VERSION 5.8 ;
BUSBITCHARS "[]" ;
DIVIDERCHAR "/" ;
UNITS
    DATABASE MICRONS 1000 ;
END UNITS

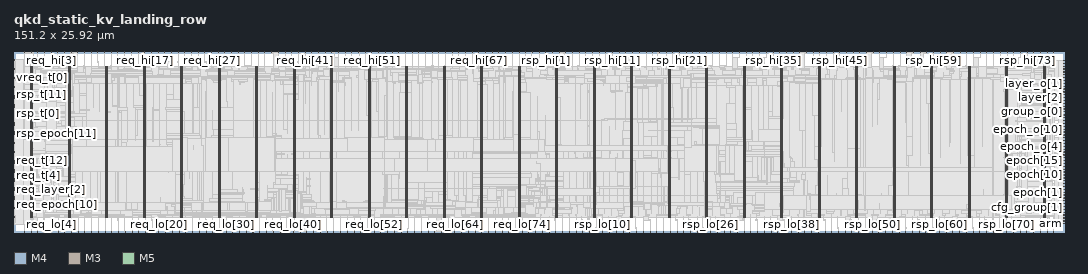
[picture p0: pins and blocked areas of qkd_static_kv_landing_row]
MACRO qkd_static_kv_landing_row
  FOREIGN qkd_static_kv_landing_row 0 0 ;
  CLASS BLOCK ;
  SIZE 151.2 BY 25.92 ;
  PIN arm
    DIRECTION INPUT ;
    USE SIGNAL ;
    PORT
      LAYER M4 ;
        RECT  151.116 1.2 151.2 1.224 ;
    END
  END arm
  PIN arm_o
    DIRECTION OUTPUT ;
    USE SIGNAL ;
    PORT
      LAYER M4 ;
        RECT  151.116 1.584 151.2 1.608 ;
    END
  END arm_o
  PIN cfg_group[0]
    DIRECTION INPUT ;
    USE SIGNAL ;
    PORT
      LAYER M4 ;
        RECT  151.116 2.016 151.2 2.04 ;
    END
  END cfg_group[0]
  PIN cfg_group[1]
    DIRECTION INPUT ;
    USE SIGNAL ;
    PORT
      LAYER M4 ;
        RECT  151.116 2.448 151.2 2.472 ;
    END
  END cfg_group[1]
  PIN cfg_group[2]
    DIRECTION INPUT ;
    USE SIGNAL ;
    PORT
      LAYER M4 ;
        RECT  151.116 2.832 151.2 2.856 ;
    END
  END cfg_group[2]
  PIN cfg_stack[0]
    DIRECTION INPUT ;
    USE SIGNAL ;
    PORT
      LAYER M4 ;
        RECT  151.116 3.264 151.2 3.288 ;
    END
  END cfg_stack[0]
  PIN cfg_stack[1]
    DIRECTION INPUT ;
    USE SIGNAL ;
    PORT
      LAYER M4 ;
        RECT  151.116 3.648 151.2 3.672 ;
    END
  END cfg_stack[1]
  PIN ck
    DIRECTION INPUT ;
    USE SIGNAL ;
    PORT
      LAYER M3 ;
        RECT  1.476 25.882 1.494 25.92 ;
    END
  END ck
  PIN epoch[0]
    DIRECTION INPUT ;
    USE SIGNAL ;
    PORT
      LAYER M4 ;
        RECT  151.116 4.08 151.2 4.104 ;
    END
  END epoch[0]
  PIN epoch[10]
    DIRECTION INPUT ;
    USE SIGNAL ;
    PORT
      LAYER M4 ;
        RECT  151.116 8.208 151.2 8.232 ;
    END
  END epoch[10]
  PIN epoch[11]
    DIRECTION INPUT ;
    USE SIGNAL ;
    PORT
      LAYER M4 ;
        RECT  151.116 8.64 151.2 8.664 ;
    END
  END epoch[11]
  PIN epoch[12]
    DIRECTION INPUT ;
    USE SIGNAL ;
    PORT
      LAYER M4 ;
        RECT  151.116 9.024 151.2 9.048 ;
    END
  END epoch[12]
  PIN epoch[13]
    DIRECTION INPUT ;
    USE SIGNAL ;
    PORT
      LAYER M4 ;
        RECT  151.116 9.456 151.2 9.48 ;
    END
  END epoch[13]
  PIN epoch[14]
    DIRECTION INPUT ;
    USE SIGNAL ;
    PORT
      LAYER M4 ;
        RECT  151.116 9.84 151.2 9.864 ;
    END
  END epoch[14]
  PIN epoch[15]
    DIRECTION INPUT ;
    USE SIGNAL ;
    PORT
      LAYER M4 ;
        RECT  151.116 10.272 151.2 10.296 ;
    END
  END epoch[15]
  PIN epoch[1]
    DIRECTION INPUT ;
    USE SIGNAL ;
    PORT
      LAYER M4 ;
        RECT  151.116 4.512 151.2 4.536 ;
    END
  END epoch[1]
  PIN epoch[2]
    DIRECTION INPUT ;
    USE SIGNAL ;
    PORT
      LAYER M4 ;
        RECT  151.116 4.896 151.2 4.92 ;
    END
  END epoch[2]
  PIN epoch[3]
    DIRECTION INPUT ;
    USE SIGNAL ;
    PORT
      LAYER M4 ;
        RECT  151.116 5.328 151.2 5.352 ;
    END
  END epoch[3]
  PIN epoch[4]
    DIRECTION INPUT ;
    USE SIGNAL ;
    PORT
      LAYER M4 ;
        RECT  151.116 5.712 151.2 5.736 ;
    END
  END epoch[4]
  PIN epoch[5]
    DIRECTION INPUT ;
    USE SIGNAL ;
    PORT
      LAYER M4 ;
        RECT  151.116 6.144 151.2 6.168 ;
    END
  END epoch[5]
  PIN epoch[6]
    DIRECTION INPUT ;
    USE SIGNAL ;
    PORT
      LAYER M4 ;
        RECT  151.116 6.576 151.2 6.6 ;
    END
  END epoch[6]
  PIN epoch[7]
    DIRECTION INPUT ;
    USE SIGNAL ;
    PORT
      LAYER M4 ;
        RECT  151.116 6.96 151.2 6.984 ;
    END
  END epoch[7]
  PIN epoch[8]
    DIRECTION INPUT ;
    USE SIGNAL ;
    PORT
      LAYER M4 ;
        RECT  151.116 7.392 151.2 7.416 ;
    END
  END epoch[8]
  PIN epoch[9]
    DIRECTION INPUT ;
    USE SIGNAL ;
    PORT
      LAYER M4 ;
        RECT  151.116 7.776 151.2 7.8 ;
    END
  END epoch[9]
  PIN epoch_o[0]
    DIRECTION OUTPUT ;
    USE SIGNAL ;
    PORT
      LAYER M4 ;
        RECT  151.116 10.704 151.2 10.728 ;
    END
  END epoch_o[0]
  PIN epoch_o[10]
    DIRECTION OUTPUT ;
    USE SIGNAL ;
    PORT
      LAYER M4 ;
        RECT  151.116 14.784 151.2 14.808 ;
    END
  END epoch_o[10]
  PIN epoch_o[11]
    DIRECTION OUTPUT ;
    USE SIGNAL ;
    PORT
      LAYER M4 ;
        RECT  151.116 15.216 151.2 15.24 ;
    END
  END epoch_o[11]
  PIN epoch_o[12]
    DIRECTION OUTPUT ;
    USE SIGNAL ;
    PORT
      LAYER M4 ;
        RECT  151.116 15.648 151.2 15.672 ;
    END
  END epoch_o[12]
  PIN epoch_o[13]
    DIRECTION OUTPUT ;
    USE SIGNAL ;
    PORT
      LAYER M4 ;
        RECT  151.116 16.032 151.2 16.056 ;
    END
  END epoch_o[13]
  PIN epoch_o[14]
    DIRECTION OUTPUT ;
    USE SIGNAL ;
    PORT
      LAYER M4 ;
        RECT  151.116 16.464 151.2 16.488 ;
    END
  END epoch_o[14]
  PIN epoch_o[15]
    DIRECTION OUTPUT ;
    USE SIGNAL ;
    PORT
      LAYER M4 ;
        RECT  151.116 16.848 151.2 16.872 ;
    END
  END epoch_o[15]
  PIN epoch_o[1]
    DIRECTION OUTPUT ;
    USE SIGNAL ;
    PORT
      LAYER M4 ;
        RECT  151.116 11.088 151.2 11.112 ;
    END
  END epoch_o[1]
  PIN epoch_o[2]
    DIRECTION OUTPUT ;
    USE SIGNAL ;
    PORT
      LAYER M4 ;
        RECT  151.116 11.52 151.2 11.544 ;
    END
  END epoch_o[2]
  PIN epoch_o[3]
    DIRECTION OUTPUT ;
    USE SIGNAL ;
    PORT
      LAYER M4 ;
        RECT  151.116 11.904 151.2 11.928 ;
    END
  END epoch_o[3]
  PIN epoch_o[4]
    DIRECTION OUTPUT ;
    USE SIGNAL ;
    PORT
      LAYER M4 ;
        RECT  151.116 12.336 151.2 12.36 ;
    END
  END epoch_o[4]
  PIN epoch_o[5]
    DIRECTION OUTPUT ;
    USE SIGNAL ;
    PORT
      LAYER M4 ;
        RECT  151.116 12.72 151.2 12.744 ;
    END
  END epoch_o[5]
  PIN epoch_o[6]
    DIRECTION OUTPUT ;
    USE SIGNAL ;
    PORT
      LAYER M4 ;
        RECT  151.116 13.152 151.2 13.176 ;
    END
  END epoch_o[6]
  PIN epoch_o[7]
    DIRECTION OUTPUT ;
    USE SIGNAL ;
    PORT
      LAYER M4 ;
        RECT  151.116 13.584 151.2 13.608 ;
    END
  END epoch_o[7]
  PIN epoch_o[8]
    DIRECTION OUTPUT ;
    USE SIGNAL ;
    PORT
      LAYER M4 ;
        RECT  151.116 13.968 151.2 13.992 ;
    END
  END epoch_o[8]
  PIN epoch_o[9]
    DIRECTION OUTPUT ;
    USE SIGNAL ;
    PORT
      LAYER M4 ;
        RECT  151.116 14.4 151.2 14.424 ;
    END
  END epoch_o[9]
  PIN fault
    DIRECTION OUTPUT ;
    USE SIGNAL ;
    PORT
      LAYER M4 ;
        RECT  0 1.104 0.084 1.128 ;
    END
  END fault
  PIN group_o[0]
    DIRECTION OUTPUT ;
    USE SIGNAL ;
    PORT
      LAYER M4 ;
        RECT  151.116 17.28 151.2 17.304 ;
    END
  END group_o[0]
  PIN group_o[1]
    DIRECTION OUTPUT ;
    USE SIGNAL ;
    PORT
      LAYER M4 ;
        RECT  151.116 17.712 151.2 17.736 ;
    END
  END group_o[1]
  PIN group_o[2]
    DIRECTION OUTPUT ;
    USE SIGNAL ;
    PORT
      LAYER M4 ;
        RECT  151.116 18.096 151.2 18.12 ;
    END
  END group_o[2]
  PIN layer[0]
    DIRECTION INPUT ;
    USE SIGNAL ;
    PORT
      LAYER M4 ;
        RECT  151.116 18.528 151.2 18.552 ;
    END
  END layer[0]
  PIN layer[1]
    DIRECTION INPUT ;
    USE SIGNAL ;
    PORT
      LAYER M4 ;
        RECT  151.116 18.912 151.2 18.936 ;
    END
  END layer[1]
  PIN layer[2]
    DIRECTION INPUT ;
    USE SIGNAL ;
    PORT
      LAYER M4 ;
        RECT  151.116 19.344 151.2 19.368 ;
    END
  END layer[2]
  PIN layer[3]
    DIRECTION INPUT ;
    USE SIGNAL ;
    PORT
      LAYER M4 ;
        RECT  151.116 19.776 151.2 19.8 ;
    END
  END layer[3]
  PIN layer[4]
    DIRECTION INPUT ;
    USE SIGNAL ;
    PORT
      LAYER M4 ;
        RECT  151.116 20.16 151.2 20.184 ;
    END
  END layer[4]
  PIN layer[5]
    DIRECTION INPUT ;
    USE SIGNAL ;
    PORT
      LAYER M4 ;
        RECT  151.116 20.592 151.2 20.616 ;
    END
  END layer[5]
  PIN layer_o[0]
    DIRECTION OUTPUT ;
    USE SIGNAL ;
    PORT
      LAYER M4 ;
        RECT  151.116 20.976 151.2 21 ;
    END
  END layer_o[0]
  PIN layer_o[1]
    DIRECTION OUTPUT ;
    USE SIGNAL ;
    PORT
      LAYER M4 ;
        RECT  151.116 21.408 151.2 21.432 ;
    END
  END layer_o[1]
  PIN layer_o[2]
    DIRECTION OUTPUT ;
    USE SIGNAL ;
    PORT
      LAYER M4 ;
        RECT  151.116 21.792 151.2 21.816 ;
    END
  END layer_o[2]
  PIN layer_o[3]
    DIRECTION OUTPUT ;
    USE SIGNAL ;
    PORT
      LAYER M4 ;
        RECT  151.116 22.224 151.2 22.248 ;
    END
  END layer_o[3]
  PIN layer_o[4]
    DIRECTION OUTPUT ;
    USE SIGNAL ;
    PORT
      LAYER M4 ;
        RECT  151.116 22.656 151.2 22.68 ;
    END
  END layer_o[4]
  PIN layer_o[5]
    DIRECTION OUTPUT ;
    USE SIGNAL ;
    PORT
      LAYER M4 ;
        RECT  151.116 23.04 151.2 23.064 ;
    END
  END layer_o[5]
  PIN req_epoch[0]
    DIRECTION INPUT ;
    USE SIGNAL ;
    PORT
      LAYER M4 ;
        RECT  0 1.392 0.084 1.416 ;
    END
  END req_epoch[0]
  PIN req_epoch[10]
    DIRECTION INPUT ;
    USE SIGNAL ;
    PORT
      LAYER M4 ;
        RECT  0 3.984 0.084 4.008 ;
    END
  END req_epoch[10]
  PIN req_epoch[11]
    DIRECTION INPUT ;
    USE SIGNAL ;
    PORT
      LAYER M4 ;
        RECT  0 4.224 0.084 4.248 ;
    END
  END req_epoch[11]
  PIN req_epoch[12]
    DIRECTION INPUT ;
    USE SIGNAL ;
    PORT
      LAYER M4 ;
        RECT  0 4.512 0.084 4.536 ;
    END
  END req_epoch[12]
  PIN req_epoch[13]
    DIRECTION INPUT ;
    USE SIGNAL ;
    PORT
      LAYER M4 ;
        RECT  0 4.752 0.084 4.776 ;
    END
  END req_epoch[13]
  PIN req_epoch[14]
    DIRECTION INPUT ;
    USE SIGNAL ;
    PORT
      LAYER M4 ;
        RECT  0 5.04 0.084 5.064 ;
    END
  END req_epoch[14]
  PIN req_epoch[15]
    DIRECTION INPUT ;
    USE SIGNAL ;
    PORT
      LAYER M4 ;
        RECT  0 5.28 0.084 5.304 ;
    END
  END req_epoch[15]
  PIN req_epoch[1]
    DIRECTION INPUT ;
    USE SIGNAL ;
    PORT
      LAYER M4 ;
        RECT  0 1.632 0.084 1.656 ;
    END
  END req_epoch[1]
  PIN req_epoch[2]
    DIRECTION INPUT ;
    USE SIGNAL ;
    PORT
      LAYER M4 ;
        RECT  0 1.92 0.084 1.944 ;
    END
  END req_epoch[2]
  PIN req_epoch[3]
    DIRECTION INPUT ;
    USE SIGNAL ;
    PORT
      LAYER M4 ;
        RECT  0 2.16 0.084 2.184 ;
    END
  END req_epoch[3]
  PIN req_epoch[4]
    DIRECTION INPUT ;
    USE SIGNAL ;
    PORT
      LAYER M4 ;
        RECT  0 2.4 0.084 2.424 ;
    END
  END req_epoch[4]
  PIN req_epoch[5]
    DIRECTION INPUT ;
    USE SIGNAL ;
    PORT
      LAYER M4 ;
        RECT  0 2.688 0.084 2.712 ;
    END
  END req_epoch[5]
  PIN req_epoch[6]
    DIRECTION INPUT ;
    USE SIGNAL ;
    PORT
      LAYER M4 ;
        RECT  0 2.928 0.084 2.952 ;
    END
  END req_epoch[6]
  PIN req_epoch[7]
    DIRECTION INPUT ;
    USE SIGNAL ;
    PORT
      LAYER M4 ;
        RECT  0 3.216 0.084 3.24 ;
    END
  END req_epoch[7]
  PIN req_epoch[8]
    DIRECTION INPUT ;
    USE SIGNAL ;
    PORT
      LAYER M4 ;
        RECT  0 3.456 0.084 3.48 ;
    END
  END req_epoch[8]
  PIN req_epoch[9]
    DIRECTION INPUT ;
    USE SIGNAL ;
    PORT
      LAYER M4 ;
        RECT  0 3.696 0.084 3.72 ;
    END
  END req_epoch[9]
  PIN req_hi[0]
    DIRECTION OUTPUT ;
    USE SIGNAL ;
    PORT
      LAYER M5 ;
        RECT  2.448 25.836 2.472 25.92 ;
    END
  END req_hi[0]
  PIN req_hi[10]
    DIRECTION OUTPUT ;
    USE SIGNAL ;
    PORT
      LAYER M5 ;
        RECT  12.048 25.836 12.072 25.92 ;
    END
  END req_hi[10]
  PIN req_hi[11]
    DIRECTION OUTPUT ;
    USE SIGNAL ;
    PORT
      LAYER M3 ;
        RECT  13.032 25.882 13.05 25.92 ;
    END
  END req_hi[11]
  PIN req_hi[12]
    DIRECTION OUTPUT ;
    USE SIGNAL ;
    PORT
      LAYER M5 ;
        RECT  13.968 25.836 13.992 25.92 ;
    END
  END req_hi[12]
  PIN req_hi[13]
    DIRECTION OUTPUT ;
    USE SIGNAL ;
    PORT
      LAYER M3 ;
        RECT  14.94 25.882 14.958 25.92 ;
    END
  END req_hi[13]
  PIN req_hi[14]
    DIRECTION OUTPUT ;
    USE SIGNAL ;
    PORT
      LAYER M5 ;
        RECT  15.888 25.836 15.912 25.92 ;
    END
  END req_hi[14]
  PIN req_hi[15]
    DIRECTION OUTPUT ;
    USE SIGNAL ;
    PORT
      LAYER M3 ;
        RECT  16.884 25.882 16.902 25.92 ;
    END
  END req_hi[15]
  PIN req_hi[16]
    DIRECTION OUTPUT ;
    USE SIGNAL ;
    PORT
      LAYER M5 ;
        RECT  17.856 25.836 17.88 25.92 ;
    END
  END req_hi[16]
  PIN req_hi[17]
    DIRECTION OUTPUT ;
    USE SIGNAL ;
    PORT
      LAYER M3 ;
        RECT  18.792 25.882 18.81 25.92 ;
    END
  END req_hi[17]
  PIN req_hi[18]
    DIRECTION OUTPUT ;
    USE SIGNAL ;
    PORT
      LAYER M5 ;
        RECT  19.776 25.836 19.8 25.92 ;
    END
  END req_hi[18]
  PIN req_hi[19]
    DIRECTION OUTPUT ;
    USE SIGNAL ;
    PORT
      LAYER M3 ;
        RECT  20.736 25.882 20.754 25.92 ;
    END
  END req_hi[19]
  PIN req_hi[1]
    DIRECTION OUTPUT ;
    USE SIGNAL ;
    PORT
      LAYER M3 ;
        RECT  3.384 25.882 3.402 25.92 ;
    END
  END req_hi[1]
  PIN req_hi[20]
    DIRECTION OUTPUT ;
    USE SIGNAL ;
    PORT
      LAYER M5 ;
        RECT  21.696 25.836 21.72 25.92 ;
    END
  END req_hi[20]
  PIN req_hi[21]
    DIRECTION OUTPUT ;
    USE SIGNAL ;
    PORT
      LAYER M3 ;
        RECT  22.644 25.882 22.662 25.92 ;
    END
  END req_hi[21]
  PIN req_hi[22]
    DIRECTION OUTPUT ;
    USE SIGNAL ;
    PORT
      LAYER M5 ;
        RECT  23.616 25.836 23.64 25.92 ;
    END
  END req_hi[22]
  PIN req_hi[23]
    DIRECTION OUTPUT ;
    USE SIGNAL ;
    PORT
      LAYER M3 ;
        RECT  24.588 25.882 24.606 25.92 ;
    END
  END req_hi[23]
  PIN req_hi[24]
    DIRECTION OUTPUT ;
    USE SIGNAL ;
    PORT
      LAYER M5 ;
        RECT  25.536 25.836 25.56 25.92 ;
    END
  END req_hi[24]
  PIN req_hi[25]
    DIRECTION OUTPUT ;
    USE SIGNAL ;
    PORT
      LAYER M3 ;
        RECT  26.496 25.882 26.514 25.92 ;
    END
  END req_hi[25]
  PIN req_hi[26]
    DIRECTION OUTPUT ;
    USE SIGNAL ;
    PORT
      LAYER M5 ;
        RECT  27.456 25.836 27.48 25.92 ;
    END
  END req_hi[26]
  PIN req_hi[27]
    DIRECTION OUTPUT ;
    USE SIGNAL ;
    PORT
      LAYER M3 ;
        RECT  28.44 25.882 28.458 25.92 ;
    END
  END req_hi[27]
  PIN req_hi[28]
    DIRECTION OUTPUT ;
    USE SIGNAL ;
    PORT
      LAYER M5 ;
        RECT  29.376 25.836 29.4 25.92 ;
    END
  END req_hi[28]
  PIN req_hi[29]
    DIRECTION OUTPUT ;
    USE SIGNAL ;
    PORT
      LAYER M3 ;
        RECT  30.348 25.882 30.366 25.92 ;
    END
  END req_hi[29]
  PIN req_hi[2]
    DIRECTION OUTPUT ;
    USE SIGNAL ;
    PORT
      LAYER M5 ;
        RECT  4.368 25.836 4.392 25.92 ;
    END
  END req_hi[2]
  PIN req_hi[30]
    DIRECTION OUTPUT ;
    USE SIGNAL ;
    PORT
      LAYER M5 ;
        RECT  31.296 25.836 31.32 25.92 ;
    END
  END req_hi[30]
  PIN req_hi[31]
    DIRECTION OUTPUT ;
    USE SIGNAL ;
    PORT
      LAYER M3 ;
        RECT  32.292 25.882 32.31 25.92 ;
    END
  END req_hi[31]
  PIN req_hi[32]
    DIRECTION OUTPUT ;
    USE SIGNAL ;
    PORT
      LAYER M5 ;
        RECT  33.216 25.836 33.24 25.92 ;
    END
  END req_hi[32]
  PIN req_hi[33]
    DIRECTION OUTPUT ;
    USE SIGNAL ;
    PORT
      LAYER M3 ;
        RECT  34.2 25.882 34.218 25.92 ;
    END
  END req_hi[33]
  PIN req_hi[34]
    DIRECTION OUTPUT ;
    USE SIGNAL ;
    PORT
      LAYER M5 ;
        RECT  35.184 25.836 35.208 25.92 ;
    END
  END req_hi[34]
  PIN req_hi[35]
    DIRECTION OUTPUT ;
    USE SIGNAL ;
    PORT
      LAYER M3 ;
        RECT  36.108 25.882 36.126 25.92 ;
    END
  END req_hi[35]
  PIN req_hi[36]
    DIRECTION OUTPUT ;
    USE SIGNAL ;
    PORT
      LAYER M5 ;
        RECT  37.104 25.836 37.128 25.92 ;
    END
  END req_hi[36]
  PIN req_hi[37]
    DIRECTION OUTPUT ;
    USE SIGNAL ;
    PORT
      LAYER M3 ;
        RECT  38.052 25.882 38.07 25.92 ;
    END
  END req_hi[37]
  PIN req_hi[38]
    DIRECTION OUTPUT ;
    USE SIGNAL ;
    PORT
      LAYER M5 ;
        RECT  39.024 25.836 39.048 25.92 ;
    END
  END req_hi[38]
  PIN req_hi[39]
    DIRECTION OUTPUT ;
    USE SIGNAL ;
    PORT
      LAYER M3 ;
        RECT  39.96 25.882 39.978 25.92 ;
    END
  END req_hi[39]
  PIN req_hi[3]
    DIRECTION OUTPUT ;
    USE SIGNAL ;
    PORT
      LAYER M3 ;
        RECT  5.328 25.882 5.346 25.92 ;
    END
  END req_hi[3]
  PIN req_hi[40]
    DIRECTION OUTPUT ;
    USE SIGNAL ;
    PORT
      LAYER M5 ;
        RECT  40.944 25.836 40.968 25.92 ;
    END
  END req_hi[40]
  PIN req_hi[41]
    DIRECTION OUTPUT ;
    USE SIGNAL ;
    PORT
      LAYER M3 ;
        RECT  41.904 25.882 41.922 25.92 ;
    END
  END req_hi[41]
  PIN req_hi[42]
    DIRECTION OUTPUT ;
    USE SIGNAL ;
    PORT
      LAYER M5 ;
        RECT  42.864 25.836 42.888 25.92 ;
    END
  END req_hi[42]
  PIN req_hi[43]
    DIRECTION OUTPUT ;
    USE SIGNAL ;
    PORT
      LAYER M3 ;
        RECT  43.812 25.882 43.83 25.92 ;
    END
  END req_hi[43]
  PIN req_hi[44]
    DIRECTION OUTPUT ;
    USE SIGNAL ;
    PORT
      LAYER M5 ;
        RECT  44.784 25.836 44.808 25.92 ;
    END
  END req_hi[44]
  PIN req_hi[45]
    DIRECTION OUTPUT ;
    USE SIGNAL ;
    PORT
      LAYER M3 ;
        RECT  45.756 25.882 45.774 25.92 ;
    END
  END req_hi[45]
  PIN req_hi[46]
    DIRECTION OUTPUT ;
    USE SIGNAL ;
    PORT
      LAYER M5 ;
        RECT  46.704 25.836 46.728 25.92 ;
    END
  END req_hi[46]
  PIN req_hi[47]
    DIRECTION OUTPUT ;
    USE SIGNAL ;
    PORT
      LAYER M3 ;
        RECT  47.664 25.882 47.682 25.92 ;
    END
  END req_hi[47]
  PIN req_hi[48]
    DIRECTION OUTPUT ;
    USE SIGNAL ;
    PORT
      LAYER M5 ;
        RECT  48.624 25.836 48.648 25.92 ;
    END
  END req_hi[48]
  PIN req_hi[49]
    DIRECTION OUTPUT ;
    USE SIGNAL ;
    PORT
      LAYER M3 ;
        RECT  49.608 25.882 49.626 25.92 ;
    END
  END req_hi[49]
  PIN req_hi[4]
    DIRECTION OUTPUT ;
    USE SIGNAL ;
    PORT
      LAYER M5 ;
        RECT  6.288 25.836 6.312 25.92 ;
    END
  END req_hi[4]
  PIN req_hi[50]
    DIRECTION OUTPUT ;
    USE SIGNAL ;
    PORT
      LAYER M5 ;
        RECT  50.544 25.836 50.568 25.92 ;
    END
  END req_hi[50]
  PIN req_hi[51]
    DIRECTION OUTPUT ;
    USE SIGNAL ;
    PORT
      LAYER M3 ;
        RECT  51.516 25.882 51.534 25.92 ;
    END
  END req_hi[51]
  PIN req_hi[52]
    DIRECTION OUTPUT ;
    USE SIGNAL ;
    PORT
      LAYER M5 ;
        RECT  52.464 25.836 52.488 25.92 ;
    END
  END req_hi[52]
  PIN req_hi[53]
    DIRECTION OUTPUT ;
    USE SIGNAL ;
    PORT
      LAYER M3 ;
        RECT  53.46 25.882 53.478 25.92 ;
    END
  END req_hi[53]
  PIN req_hi[54]
    DIRECTION OUTPUT ;
    USE SIGNAL ;
    PORT
      LAYER M5 ;
        RECT  54.432 25.836 54.456 25.92 ;
    END
  END req_hi[54]
  PIN req_hi[55]
    DIRECTION OUTPUT ;
    USE SIGNAL ;
    PORT
      LAYER M3 ;
        RECT  55.368 25.882 55.386 25.92 ;
    END
  END req_hi[55]
  PIN req_hi[56]
    DIRECTION OUTPUT ;
    USE SIGNAL ;
    PORT
      LAYER M5 ;
        RECT  56.352 25.836 56.376 25.92 ;
    END
  END req_hi[56]
  PIN req_hi[57]
    DIRECTION OUTPUT ;
    USE SIGNAL ;
    PORT
      LAYER M3 ;
        RECT  57.312 25.882 57.33 25.92 ;
    END
  END req_hi[57]
  PIN req_hi[58]
    DIRECTION OUTPUT ;
    USE SIGNAL ;
    PORT
      LAYER M5 ;
        RECT  58.272 25.836 58.296 25.92 ;
    END
  END req_hi[58]
  PIN req_hi[59]
    DIRECTION OUTPUT ;
    USE SIGNAL ;
    PORT
      LAYER M3 ;
        RECT  59.22 25.882 59.238 25.92 ;
    END
  END req_hi[59]
  PIN req_hi[5]
    DIRECTION OUTPUT ;
    USE SIGNAL ;
    PORT
      LAYER M3 ;
        RECT  7.236 25.882 7.254 25.92 ;
    END
  END req_hi[5]
  PIN req_hi[60]
    DIRECTION OUTPUT ;
    USE SIGNAL ;
    PORT
      LAYER M5 ;
        RECT  60.192 25.836 60.216 25.92 ;
    END
  END req_hi[60]
  PIN req_hi[61]
    DIRECTION OUTPUT ;
    USE SIGNAL ;
    PORT
      LAYER M3 ;
        RECT  61.164 25.882 61.182 25.92 ;
    END
  END req_hi[61]
  PIN req_hi[62]
    DIRECTION OUTPUT ;
    USE SIGNAL ;
    PORT
      LAYER M5 ;
        RECT  62.112 25.836 62.136 25.92 ;
    END
  END req_hi[62]
  PIN req_hi[63]
    DIRECTION OUTPUT ;
    USE SIGNAL ;
    PORT
      LAYER M3 ;
        RECT  63.072 25.882 63.09 25.92 ;
    END
  END req_hi[63]
  PIN req_hi[64]
    DIRECTION OUTPUT ;
    USE SIGNAL ;
    PORT
      LAYER M5 ;
        RECT  64.032 25.836 64.056 25.92 ;
    END
  END req_hi[64]
  PIN req_hi[65]
    DIRECTION OUTPUT ;
    USE SIGNAL ;
    PORT
      LAYER M3 ;
        RECT  65.016 25.882 65.034 25.92 ;
    END
  END req_hi[65]
  PIN req_hi[66]
    DIRECTION OUTPUT ;
    USE SIGNAL ;
    PORT
      LAYER M5 ;
        RECT  65.952 25.836 65.976 25.92 ;
    END
  END req_hi[66]
  PIN req_hi[67]
    DIRECTION OUTPUT ;
    USE SIGNAL ;
    PORT
      LAYER M3 ;
        RECT  66.924 25.882 66.942 25.92 ;
    END
  END req_hi[67]
  PIN req_hi[68]
    DIRECTION OUTPUT ;
    USE SIGNAL ;
    PORT
      LAYER M5 ;
        RECT  67.872 25.836 67.896 25.92 ;
    END
  END req_hi[68]
  PIN req_hi[69]
    DIRECTION OUTPUT ;
    USE SIGNAL ;
    PORT
      LAYER M3 ;
        RECT  68.868 25.882 68.886 25.92 ;
    END
  END req_hi[69]
  PIN req_hi[6]
    DIRECTION OUTPUT ;
    USE SIGNAL ;
    PORT
      LAYER M5 ;
        RECT  8.208 25.836 8.232 25.92 ;
    END
  END req_hi[6]
  PIN req_hi[70]
    DIRECTION OUTPUT ;
    USE SIGNAL ;
    PORT
      LAYER M5 ;
        RECT  69.792 25.836 69.816 25.92 ;
    END
  END req_hi[70]
  PIN req_hi[71]
    DIRECTION OUTPUT ;
    USE SIGNAL ;
    PORT
      LAYER M3 ;
        RECT  70.776 25.882 70.794 25.92 ;
    END
  END req_hi[71]
  PIN req_hi[72]
    DIRECTION OUTPUT ;
    USE SIGNAL ;
    PORT
      LAYER M5 ;
        RECT  71.76 25.836 71.784 25.92 ;
    END
  END req_hi[72]
  PIN req_hi[73]
    DIRECTION OUTPUT ;
    USE SIGNAL ;
    PORT
      LAYER M3 ;
        RECT  72.72 25.882 72.738 25.92 ;
    END
  END req_hi[73]
  PIN req_hi[74]
    DIRECTION OUTPUT ;
    USE SIGNAL ;
    PORT
      LAYER M5 ;
        RECT  73.68 25.836 73.704 25.92 ;
    END
  END req_hi[74]
  PIN req_hi[75]
    DIRECTION OUTPUT ;
    USE SIGNAL ;
    PORT
      LAYER M3 ;
        RECT  74.628 25.882 74.646 25.92 ;
    END
  END req_hi[75]
  PIN req_hi[7]
    DIRECTION OUTPUT ;
    USE SIGNAL ;
    PORT
      LAYER M3 ;
        RECT  9.18 25.882 9.198 25.92 ;
    END
  END req_hi[7]
  PIN req_hi[8]
    DIRECTION OUTPUT ;
    USE SIGNAL ;
    PORT
      LAYER M5 ;
        RECT  10.128 25.836 10.152 25.92 ;
    END
  END req_hi[8]
  PIN req_hi[9]
    DIRECTION OUTPUT ;
    USE SIGNAL ;
    PORT
      LAYER M3 ;
        RECT  11.088 25.882 11.106 25.92 ;
    END
  END req_hi[9]
  PIN req_layer[0]
    DIRECTION INPUT ;
    USE SIGNAL ;
    PORT
      LAYER M4 ;
        RECT  0 5.52 0.084 5.544 ;
    END
  END req_layer[0]
  PIN req_layer[1]
    DIRECTION INPUT ;
    USE SIGNAL ;
    PORT
      LAYER M4 ;
        RECT  0 5.808 0.084 5.832 ;
    END
  END req_layer[1]
  PIN req_layer[2]
    DIRECTION INPUT ;
    USE SIGNAL ;
    PORT
      LAYER M4 ;
        RECT  0 6.048 0.084 6.072 ;
    END
  END req_layer[2]
  PIN req_layer[3]
    DIRECTION INPUT ;
    USE SIGNAL ;
    PORT
      LAYER M4 ;
        RECT  0 6.336 0.084 6.36 ;
    END
  END req_layer[3]
  PIN req_layer[4]
    DIRECTION INPUT ;
    USE SIGNAL ;
    PORT
      LAYER M4 ;
        RECT  0 6.576 0.084 6.6 ;
    END
  END req_layer[4]
  PIN req_layer[5]
    DIRECTION INPUT ;
    USE SIGNAL ;
    PORT
      LAYER M4 ;
        RECT  0 6.816 0.084 6.84 ;
    END
  END req_layer[5]
  PIN req_lo[0]
    DIRECTION OUTPUT ;
    USE SIGNAL ;
    PORT
      LAYER M3 ;
        RECT  1.476 0 1.494 0.038 ;
    END
  END req_lo[0]
  PIN req_lo[10]
    DIRECTION OUTPUT ;
    USE SIGNAL ;
    PORT
      LAYER M3 ;
        RECT  11.16 0 11.178 0.038 ;
    END
  END req_lo[10]
  PIN req_lo[11]
    DIRECTION OUTPUT ;
    USE SIGNAL ;
    PORT
      LAYER M5 ;
        RECT  12.144 0 12.168 0.084 ;
    END
  END req_lo[11]
  PIN req_lo[12]
    DIRECTION OUTPUT ;
    USE SIGNAL ;
    PORT
      LAYER M3 ;
        RECT  13.104 0 13.122 0.038 ;
    END
  END req_lo[12]
  PIN req_lo[13]
    DIRECTION OUTPUT ;
    USE SIGNAL ;
    PORT
      LAYER M5 ;
        RECT  14.064 0 14.088 0.084 ;
    END
  END req_lo[13]
  PIN req_lo[14]
    DIRECTION OUTPUT ;
    USE SIGNAL ;
    PORT
      LAYER M3 ;
        RECT  15.048 0 15.066 0.038 ;
    END
  END req_lo[14]
  PIN req_lo[15]
    DIRECTION OUTPUT ;
    USE SIGNAL ;
    PORT
      LAYER M5 ;
        RECT  15.984 0 16.008 0.084 ;
    END
  END req_lo[15]
  PIN req_lo[16]
    DIRECTION OUTPUT ;
    USE SIGNAL ;
    PORT
      LAYER M3 ;
        RECT  16.992 0 17.01 0.038 ;
    END
  END req_lo[16]
  PIN req_lo[17]
    DIRECTION OUTPUT ;
    USE SIGNAL ;
    PORT
      LAYER M5 ;
        RECT  17.952 0 17.976 0.084 ;
    END
  END req_lo[17]
  PIN req_lo[18]
    DIRECTION OUTPUT ;
    USE SIGNAL ;
    PORT
      LAYER M3 ;
        RECT  18.9 0 18.918 0.038 ;
    END
  END req_lo[18]
  PIN req_lo[19]
    DIRECTION OUTPUT ;
    USE SIGNAL ;
    PORT
      LAYER M5 ;
        RECT  19.872 0 19.896 0.084 ;
    END
  END req_lo[19]
  PIN req_lo[1]
    DIRECTION OUTPUT ;
    USE SIGNAL ;
    PORT
      LAYER M5 ;
        RECT  2.448 0 2.472 0.084 ;
    END
  END req_lo[1]
  PIN req_lo[20]
    DIRECTION OUTPUT ;
    USE SIGNAL ;
    PORT
      LAYER M3 ;
        RECT  20.844 0 20.862 0.038 ;
    END
  END req_lo[20]
  PIN req_lo[21]
    DIRECTION OUTPUT ;
    USE SIGNAL ;
    PORT
      LAYER M5 ;
        RECT  21.84 0 21.864 0.084 ;
    END
  END req_lo[21]
  PIN req_lo[22]
    DIRECTION OUTPUT ;
    USE SIGNAL ;
    PORT
      LAYER M3 ;
        RECT  22.788 0 22.806 0.038 ;
    END
  END req_lo[22]
  PIN req_lo[23]
    DIRECTION OUTPUT ;
    USE SIGNAL ;
    PORT
      LAYER M5 ;
        RECT  23.76 0 23.784 0.084 ;
    END
  END req_lo[23]
  PIN req_lo[24]
    DIRECTION OUTPUT ;
    USE SIGNAL ;
    PORT
      LAYER M3 ;
        RECT  24.732 0 24.75 0.038 ;
    END
  END req_lo[24]
  PIN req_lo[25]
    DIRECTION OUTPUT ;
    USE SIGNAL ;
    PORT
      LAYER M5 ;
        RECT  25.68 0 25.704 0.084 ;
    END
  END req_lo[25]
  PIN req_lo[26]
    DIRECTION OUTPUT ;
    USE SIGNAL ;
    PORT
      LAYER M3 ;
        RECT  26.676 0 26.694 0.038 ;
    END
  END req_lo[26]
  PIN req_lo[27]
    DIRECTION OUTPUT ;
    USE SIGNAL ;
    PORT
      LAYER M5 ;
        RECT  27.648 0 27.672 0.084 ;
    END
  END req_lo[27]
  PIN req_lo[28]
    DIRECTION OUTPUT ;
    USE SIGNAL ;
    PORT
      LAYER M3 ;
        RECT  28.62 0 28.638 0.038 ;
    END
  END req_lo[28]
  PIN req_lo[29]
    DIRECTION OUTPUT ;
    USE SIGNAL ;
    PORT
      LAYER M5 ;
        RECT  29.568 0 29.592 0.084 ;
    END
  END req_lo[29]
  PIN req_lo[2]
    DIRECTION OUTPUT ;
    USE SIGNAL ;
    PORT
      LAYER M3 ;
        RECT  3.42 0 3.438 0.038 ;
    END
  END req_lo[2]
  PIN req_lo[30]
    DIRECTION OUTPUT ;
    USE SIGNAL ;
    PORT
      LAYER M3 ;
        RECT  30.528 0 30.546 0.038 ;
    END
  END req_lo[30]
  PIN req_lo[31]
    DIRECTION OUTPUT ;
    USE SIGNAL ;
    PORT
      LAYER M5 ;
        RECT  31.488 0 31.512 0.084 ;
    END
  END req_lo[31]
  PIN req_lo[32]
    DIRECTION OUTPUT ;
    USE SIGNAL ;
    PORT
      LAYER M3 ;
        RECT  32.472 0 32.49 0.038 ;
    END
  END req_lo[32]
  PIN req_lo[33]
    DIRECTION OUTPUT ;
    USE SIGNAL ;
    PORT
      LAYER M5 ;
        RECT  33.456 0 33.48 0.084 ;
    END
  END req_lo[33]
  PIN req_lo[34]
    DIRECTION OUTPUT ;
    USE SIGNAL ;
    PORT
      LAYER M3 ;
        RECT  34.416 0 34.434 0.038 ;
    END
  END req_lo[34]
  PIN req_lo[35]
    DIRECTION OUTPUT ;
    USE SIGNAL ;
    PORT
      LAYER M5 ;
        RECT  35.376 0 35.4 0.084 ;
    END
  END req_lo[35]
  PIN req_lo[36]
    DIRECTION OUTPUT ;
    USE SIGNAL ;
    PORT
      LAYER M3 ;
        RECT  36.36 0 36.378 0.038 ;
    END
  END req_lo[36]
  PIN req_lo[37]
    DIRECTION OUTPUT ;
    USE SIGNAL ;
    PORT
      LAYER M5 ;
        RECT  37.296 0 37.32 0.084 ;
    END
  END req_lo[37]
  PIN req_lo[38]
    DIRECTION OUTPUT ;
    USE SIGNAL ;
    PORT
      LAYER M3 ;
        RECT  38.304 0 38.322 0.038 ;
    END
  END req_lo[38]
  PIN req_lo[39]
    DIRECTION OUTPUT ;
    USE SIGNAL ;
    PORT
      LAYER M5 ;
        RECT  39.264 0 39.288 0.084 ;
    END
  END req_lo[39]
  PIN req_lo[3]
    DIRECTION OUTPUT ;
    USE SIGNAL ;
    PORT
      LAYER M5 ;
        RECT  4.368 0 4.392 0.084 ;
    END
  END req_lo[3]
  PIN req_lo[40]
    DIRECTION OUTPUT ;
    USE SIGNAL ;
    PORT
      LAYER M3 ;
        RECT  40.212 0 40.23 0.038 ;
    END
  END req_lo[40]
  PIN req_lo[41]
    DIRECTION OUTPUT ;
    USE SIGNAL ;
    PORT
      LAYER M5 ;
        RECT  41.184 0 41.208 0.084 ;
    END
  END req_lo[41]
  PIN req_lo[42]
    DIRECTION OUTPUT ;
    USE SIGNAL ;
    PORT
      LAYER M3 ;
        RECT  42.156 0 42.174 0.038 ;
    END
  END req_lo[42]
  PIN req_lo[43]
    DIRECTION OUTPUT ;
    USE SIGNAL ;
    PORT
      LAYER M5 ;
        RECT  43.152 0 43.176 0.084 ;
    END
  END req_lo[43]
  PIN req_lo[44]
    DIRECTION OUTPUT ;
    USE SIGNAL ;
    PORT
      LAYER M3 ;
        RECT  44.1 0 44.118 0.038 ;
    END
  END req_lo[44]
  PIN req_lo[45]
    DIRECTION OUTPUT ;
    USE SIGNAL ;
    PORT
      LAYER M5 ;
        RECT  45.072 0 45.096 0.084 ;
    END
  END req_lo[45]
  PIN req_lo[46]
    DIRECTION OUTPUT ;
    USE SIGNAL ;
    PORT
      LAYER M3 ;
        RECT  46.044 0 46.062 0.038 ;
    END
  END req_lo[46]
  PIN req_lo[47]
    DIRECTION OUTPUT ;
    USE SIGNAL ;
    PORT
      LAYER M5 ;
        RECT  46.992 0 47.016 0.084 ;
    END
  END req_lo[47]
  PIN req_lo[48]
    DIRECTION OUTPUT ;
    USE SIGNAL ;
    PORT
      LAYER M3 ;
        RECT  47.988 0 48.006 0.038 ;
    END
  END req_lo[48]
  PIN req_lo[49]
    DIRECTION OUTPUT ;
    USE SIGNAL ;
    PORT
      LAYER M5 ;
        RECT  48.96 0 48.984 0.084 ;
    END
  END req_lo[49]
  PIN req_lo[4]
    DIRECTION OUTPUT ;
    USE SIGNAL ;
    PORT
      LAYER M3 ;
        RECT  5.364 0 5.382 0.038 ;
    END
  END req_lo[4]
  PIN req_lo[50]
    DIRECTION OUTPUT ;
    USE SIGNAL ;
    PORT
      LAYER M3 ;
        RECT  49.932 0 49.95 0.038 ;
    END
  END req_lo[50]
  PIN req_lo[51]
    DIRECTION OUTPUT ;
    USE SIGNAL ;
    PORT
      LAYER M5 ;
        RECT  50.88 0 50.904 0.084 ;
    END
  END req_lo[51]
  PIN req_lo[52]
    DIRECTION OUTPUT ;
    USE SIGNAL ;
    PORT
      LAYER M3 ;
        RECT  51.84 0 51.858 0.038 ;
    END
  END req_lo[52]
  PIN req_lo[53]
    DIRECTION OUTPUT ;
    USE SIGNAL ;
    PORT
      LAYER M5 ;
        RECT  52.8 0 52.824 0.084 ;
    END
  END req_lo[53]
  PIN req_lo[54]
    DIRECTION OUTPUT ;
    USE SIGNAL ;
    PORT
      LAYER M3 ;
        RECT  53.784 0 53.802 0.038 ;
    END
  END req_lo[54]
  PIN req_lo[55]
    DIRECTION OUTPUT ;
    USE SIGNAL ;
    PORT
      LAYER M5 ;
        RECT  54.768 0 54.792 0.084 ;
    END
  END req_lo[55]
  PIN req_lo[56]
    DIRECTION OUTPUT ;
    USE SIGNAL ;
    PORT
      LAYER M3 ;
        RECT  55.728 0 55.746 0.038 ;
    END
  END req_lo[56]
  PIN req_lo[57]
    DIRECTION OUTPUT ;
    USE SIGNAL ;
    PORT
      LAYER M5 ;
        RECT  56.688 0 56.712 0.084 ;
    END
  END req_lo[57]
  PIN req_lo[58]
    DIRECTION OUTPUT ;
    USE SIGNAL ;
    PORT
      LAYER M3 ;
        RECT  57.672 0 57.69 0.038 ;
    END
  END req_lo[58]
  PIN req_lo[59]
    DIRECTION OUTPUT ;
    USE SIGNAL ;
    PORT
      LAYER M5 ;
        RECT  58.656 0 58.68 0.084 ;
    END
  END req_lo[59]
  PIN req_lo[5]
    DIRECTION OUTPUT ;
    USE SIGNAL ;
    PORT
      LAYER M5 ;
        RECT  6.336 0 6.36 0.084 ;
    END
  END req_lo[5]
  PIN req_lo[60]
    DIRECTION OUTPUT ;
    USE SIGNAL ;
    PORT
      LAYER M3 ;
        RECT  59.616 0 59.634 0.038 ;
    END
  END req_lo[60]
  PIN req_lo[61]
    DIRECTION OUTPUT ;
    USE SIGNAL ;
    PORT
      LAYER M5 ;
        RECT  60.576 0 60.6 0.084 ;
    END
  END req_lo[61]
  PIN req_lo[62]
    DIRECTION OUTPUT ;
    USE SIGNAL ;
    PORT
      LAYER M3 ;
        RECT  61.56 0 61.578 0.038 ;
    END
  END req_lo[62]
  PIN req_lo[63]
    DIRECTION OUTPUT ;
    USE SIGNAL ;
    PORT
      LAYER M5 ;
        RECT  62.496 0 62.52 0.084 ;
    END
  END req_lo[63]
  PIN req_lo[64]
    DIRECTION OUTPUT ;
    USE SIGNAL ;
    PORT
      LAYER M3 ;
        RECT  63.468 0 63.486 0.038 ;
    END
  END req_lo[64]
  PIN req_lo[65]
    DIRECTION OUTPUT ;
    USE SIGNAL ;
    PORT
      LAYER M5 ;
        RECT  64.464 0 64.488 0.084 ;
    END
  END req_lo[65]
  PIN req_lo[66]
    DIRECTION OUTPUT ;
    USE SIGNAL ;
    PORT
      LAYER M3 ;
        RECT  65.412 0 65.43 0.038 ;
    END
  END req_lo[66]
  PIN req_lo[67]
    DIRECTION OUTPUT ;
    USE SIGNAL ;
    PORT
      LAYER M5 ;
        RECT  66.384 0 66.408 0.084 ;
    END
  END req_lo[67]
  PIN req_lo[68]
    DIRECTION OUTPUT ;
    USE SIGNAL ;
    PORT
      LAYER M3 ;
        RECT  67.356 0 67.374 0.038 ;
    END
  END req_lo[68]
  PIN req_lo[69]
    DIRECTION OUTPUT ;
    USE SIGNAL ;
    PORT
      LAYER M5 ;
        RECT  68.304 0 68.328 0.084 ;
    END
  END req_lo[69]
  PIN req_lo[6]
    DIRECTION OUTPUT ;
    USE SIGNAL ;
    PORT
      LAYER M3 ;
        RECT  7.272 0 7.29 0.038 ;
    END
  END req_lo[6]
  PIN req_lo[70]
    DIRECTION OUTPUT ;
    USE SIGNAL ;
    PORT
      LAYER M3 ;
        RECT  69.3 0 69.318 0.038 ;
    END
  END req_lo[70]
  PIN req_lo[71]
    DIRECTION OUTPUT ;
    USE SIGNAL ;
    PORT
      LAYER M5 ;
        RECT  70.272 0 70.296 0.084 ;
    END
  END req_lo[71]
  PIN req_lo[72]
    DIRECTION OUTPUT ;
    USE SIGNAL ;
    PORT
      LAYER M3 ;
        RECT  71.244 0 71.262 0.038 ;
    END
  END req_lo[72]
  PIN req_lo[73]
    DIRECTION OUTPUT ;
    USE SIGNAL ;
    PORT
      LAYER M5 ;
        RECT  72.192 0 72.216 0.084 ;
    END
  END req_lo[73]
  PIN req_lo[74]
    DIRECTION OUTPUT ;
    USE SIGNAL ;
    PORT
      LAYER M3 ;
        RECT  73.152 0 73.17 0.038 ;
    END
  END req_lo[74]
  PIN req_lo[75]
    DIRECTION OUTPUT ;
    USE SIGNAL ;
    PORT
      LAYER M5 ;
        RECT  74.112 0 74.136 0.084 ;
    END
  END req_lo[75]
  PIN req_lo[7]
    DIRECTION OUTPUT ;
    USE SIGNAL ;
    PORT
      LAYER M5 ;
        RECT  8.256 0 8.28 0.084 ;
    END
  END req_lo[7]
  PIN req_lo[8]
    DIRECTION OUTPUT ;
    USE SIGNAL ;
    PORT
      LAYER M3 ;
        RECT  9.216 0 9.234 0.038 ;
    END
  END req_lo[8]
  PIN req_lo[9]
    DIRECTION OUTPUT ;
    USE SIGNAL ;
    PORT
      LAYER M5 ;
        RECT  10.176 0 10.2 0.084 ;
    END
  END req_lo[9]
  PIN req_t[0]
    DIRECTION INPUT ;
    USE SIGNAL ;
    PORT
      LAYER M4 ;
        RECT  0 7.104 0.084 7.128 ;
    END
  END req_t[0]
  PIN req_t[10]
    DIRECTION INPUT ;
    USE SIGNAL ;
    PORT
      LAYER M4 ;
        RECT  0 9.696 0.084 9.72 ;
    END
  END req_t[10]
  PIN req_t[11]
    DIRECTION INPUT ;
    USE SIGNAL ;
    PORT
      LAYER M4 ;
        RECT  0 9.936 0.084 9.96 ;
    END
  END req_t[11]
  PIN req_t[12]
    DIRECTION INPUT ;
    USE SIGNAL ;
    PORT
      LAYER M4 ;
        RECT  0 10.224 0.084 10.248 ;
    END
  END req_t[12]
  PIN req_t[13]
    DIRECTION INPUT ;
    USE SIGNAL ;
    PORT
      LAYER M4 ;
        RECT  0 10.464 0.084 10.488 ;
    END
  END req_t[13]
  PIN req_t[1]
    DIRECTION INPUT ;
    USE SIGNAL ;
    PORT
      LAYER M4 ;
        RECT  0 7.344 0.084 7.368 ;
    END
  END req_t[1]
  PIN req_t[2]
    DIRECTION INPUT ;
    USE SIGNAL ;
    PORT
      LAYER M4 ;
        RECT  0 7.632 0.084 7.656 ;
    END
  END req_t[2]
  PIN req_t[3]
    DIRECTION INPUT ;
    USE SIGNAL ;
    PORT
      LAYER M4 ;
        RECT  0 7.872 0.084 7.896 ;
    END
  END req_t[3]
  PIN req_t[4]
    DIRECTION INPUT ;
    USE SIGNAL ;
    PORT
      LAYER M4 ;
        RECT  0 8.16 0.084 8.184 ;
    END
  END req_t[4]
  PIN req_t[5]
    DIRECTION INPUT ;
    USE SIGNAL ;
    PORT
      LAYER M4 ;
        RECT  0 8.4 0.084 8.424 ;
    END
  END req_t[5]
  PIN req_t[6]
    DIRECTION INPUT ;
    USE SIGNAL ;
    PORT
      LAYER M4 ;
        RECT  0 8.64 0.084 8.664 ;
    END
  END req_t[6]
  PIN req_t[7]
    DIRECTION INPUT ;
    USE SIGNAL ;
    PORT
      LAYER M4 ;
        RECT  0 8.928 0.084 8.952 ;
    END
  END req_t[7]
  PIN req_t[8]
    DIRECTION INPUT ;
    USE SIGNAL ;
    PORT
      LAYER M4 ;
        RECT  0 9.168 0.084 9.192 ;
    END
  END req_t[8]
  PIN req_t[9]
    DIRECTION INPUT ;
    USE SIGNAL ;
    PORT
      LAYER M4 ;
        RECT  0 9.456 0.084 9.48 ;
    END
  END req_t[9]
  PIN req_v
    DIRECTION INPUT ;
    USE SIGNAL ;
    PORT
      LAYER M4 ;
        RECT  0 10.752 0.084 10.776 ;
    END
  END req_v
  PIN req_valid
    DIRECTION INPUT ;
    USE SIGNAL ;
    PORT
      LAYER M4 ;
        RECT  0 10.992 0.084 11.016 ;
    END
  END req_valid
  PIN rsp_epoch[0]
    DIRECTION OUTPUT ;
    USE SIGNAL ;
    PORT
      LAYER M4 ;
        RECT  0 11.28 0.084 11.304 ;
    END
  END rsp_epoch[0]
  PIN rsp_epoch[10]
    DIRECTION OUTPUT ;
    USE SIGNAL ;
    PORT
      LAYER M4 ;
        RECT  0 13.872 0.084 13.896 ;
    END
  END rsp_epoch[10]
  PIN rsp_epoch[11]
    DIRECTION OUTPUT ;
    USE SIGNAL ;
    PORT
      LAYER M4 ;
        RECT  0 14.112 0.084 14.136 ;
    END
  END rsp_epoch[11]
  PIN rsp_epoch[12]
    DIRECTION OUTPUT ;
    USE SIGNAL ;
    PORT
      LAYER M4 ;
        RECT  0 14.4 0.084 14.424 ;
    END
  END rsp_epoch[12]
  PIN rsp_epoch[13]
    DIRECTION OUTPUT ;
    USE SIGNAL ;
    PORT
      LAYER M4 ;
        RECT  0 14.64 0.084 14.664 ;
    END
  END rsp_epoch[13]
  PIN rsp_epoch[14]
    DIRECTION OUTPUT ;
    USE SIGNAL ;
    PORT
      LAYER M4 ;
        RECT  0 14.88 0.084 14.904 ;
    END
  END rsp_epoch[14]
  PIN rsp_epoch[15]
    DIRECTION OUTPUT ;
    USE SIGNAL ;
    PORT
      LAYER M4 ;
        RECT  0 15.168 0.084 15.192 ;
    END
  END rsp_epoch[15]
  PIN rsp_epoch[1]
    DIRECTION OUTPUT ;
    USE SIGNAL ;
    PORT
      LAYER M4 ;
        RECT  0 11.52 0.084 11.544 ;
    END
  END rsp_epoch[1]
  PIN rsp_epoch[2]
    DIRECTION OUTPUT ;
    USE SIGNAL ;
    PORT
      LAYER M4 ;
        RECT  0 11.76 0.084 11.784 ;
    END
  END rsp_epoch[2]
  PIN rsp_epoch[3]
    DIRECTION OUTPUT ;
    USE SIGNAL ;
    PORT
      LAYER M4 ;
        RECT  0 12.048 0.084 12.072 ;
    END
  END rsp_epoch[3]
  PIN rsp_epoch[4]
    DIRECTION OUTPUT ;
    USE SIGNAL ;
    PORT
      LAYER M4 ;
        RECT  0 12.288 0.084 12.312 ;
    END
  END rsp_epoch[4]
  PIN rsp_epoch[5]
    DIRECTION OUTPUT ;
    USE SIGNAL ;
    PORT
      LAYER M4 ;
        RECT  0 12.576 0.084 12.6 ;
    END
  END rsp_epoch[5]
  PIN rsp_epoch[6]
    DIRECTION OUTPUT ;
    USE SIGNAL ;
    PORT
      LAYER M4 ;
        RECT  0 12.816 0.084 12.84 ;
    END
  END rsp_epoch[6]
  PIN rsp_epoch[7]
    DIRECTION OUTPUT ;
    USE SIGNAL ;
    PORT
      LAYER M4 ;
        RECT  0 13.056 0.084 13.08 ;
    END
  END rsp_epoch[7]
  PIN rsp_epoch[8]
    DIRECTION OUTPUT ;
    USE SIGNAL ;
    PORT
      LAYER M4 ;
        RECT  0 13.344 0.084 13.368 ;
    END
  END rsp_epoch[8]
  PIN rsp_epoch[9]
    DIRECTION OUTPUT ;
    USE SIGNAL ;
    PORT
      LAYER M4 ;
        RECT  0 13.584 0.084 13.608 ;
    END
  END rsp_epoch[9]
  PIN rsp_hi[0]
    DIRECTION INPUT ;
    USE SIGNAL ;
    PORT
      LAYER M5 ;
        RECT  75.6 25.836 75.624 25.92 ;
    END
  END rsp_hi[0]
  PIN rsp_hi[10]
    DIRECTION INPUT ;
    USE SIGNAL ;
    PORT
      LAYER M5 ;
        RECT  85.2 25.836 85.224 25.92 ;
    END
  END rsp_hi[10]
  PIN rsp_hi[11]
    DIRECTION INPUT ;
    USE SIGNAL ;
    PORT
      LAYER M3 ;
        RECT  86.184 25.882 86.202 25.92 ;
    END
  END rsp_hi[11]
  PIN rsp_hi[12]
    DIRECTION INPUT ;
    USE SIGNAL ;
    PORT
      LAYER M5 ;
        RECT  87.12 25.836 87.144 25.92 ;
    END
  END rsp_hi[12]
  PIN rsp_hi[13]
    DIRECTION INPUT ;
    USE SIGNAL ;
    PORT
      LAYER M3 ;
        RECT  88.092 25.882 88.11 25.92 ;
    END
  END rsp_hi[13]
  PIN rsp_hi[14]
    DIRECTION INPUT ;
    USE SIGNAL ;
    PORT
      LAYER M5 ;
        RECT  89.088 25.836 89.112 25.92 ;
    END
  END rsp_hi[14]
  PIN rsp_hi[15]
    DIRECTION INPUT ;
    USE SIGNAL ;
    PORT
      LAYER M3 ;
        RECT  90.036 25.882 90.054 25.92 ;
    END
  END rsp_hi[15]
  PIN rsp_hi[16]
    DIRECTION INPUT ;
    USE SIGNAL ;
    PORT
      LAYER M5 ;
        RECT  91.008 25.836 91.032 25.92 ;
    END
  END rsp_hi[16]
  PIN rsp_hi[17]
    DIRECTION INPUT ;
    USE SIGNAL ;
    PORT
      LAYER M3 ;
        RECT  91.944 25.882 91.962 25.92 ;
    END
  END rsp_hi[17]
  PIN rsp_hi[18]
    DIRECTION INPUT ;
    USE SIGNAL ;
    PORT
      LAYER M5 ;
        RECT  92.928 25.836 92.952 25.92 ;
    END
  END rsp_hi[18]
  PIN rsp_hi[19]
    DIRECTION INPUT ;
    USE SIGNAL ;
    PORT
      LAYER M3 ;
        RECT  93.888 25.882 93.906 25.92 ;
    END
  END rsp_hi[19]
  PIN rsp_hi[1]
    DIRECTION INPUT ;
    USE SIGNAL ;
    PORT
      LAYER M3 ;
        RECT  76.572 25.882 76.59 25.92 ;
    END
  END rsp_hi[1]
  PIN rsp_hi[20]
    DIRECTION INPUT ;
    USE SIGNAL ;
    PORT
      LAYER M5 ;
        RECT  94.848 25.836 94.872 25.92 ;
    END
  END rsp_hi[20]
  PIN rsp_hi[21]
    DIRECTION INPUT ;
    USE SIGNAL ;
    PORT
      LAYER M3 ;
        RECT  95.796 25.882 95.814 25.92 ;
    END
  END rsp_hi[21]
  PIN rsp_hi[22]
    DIRECTION INPUT ;
    USE SIGNAL ;
    PORT
      LAYER M5 ;
        RECT  96.768 25.836 96.792 25.92 ;
    END
  END rsp_hi[22]
  PIN rsp_hi[23]
    DIRECTION INPUT ;
    USE SIGNAL ;
    PORT
      LAYER M3 ;
        RECT  97.74 25.882 97.758 25.92 ;
    END
  END rsp_hi[23]
  PIN rsp_hi[24]
    DIRECTION INPUT ;
    USE SIGNAL ;
    PORT
      LAYER M5 ;
        RECT  98.688 25.836 98.712 25.92 ;
    END
  END rsp_hi[24]
  PIN rsp_hi[25]
    DIRECTION INPUT ;
    USE SIGNAL ;
    PORT
      LAYER M3 ;
        RECT  99.648 25.882 99.666 25.92 ;
    END
  END rsp_hi[25]
  PIN rsp_hi[26]
    DIRECTION INPUT ;
    USE SIGNAL ;
    PORT
      LAYER M5 ;
        RECT  100.608 25.836 100.632 25.92 ;
    END
  END rsp_hi[26]
  PIN rsp_hi[27]
    DIRECTION INPUT ;
    USE SIGNAL ;
    PORT
      LAYER M3 ;
        RECT  101.592 25.882 101.61 25.92 ;
    END
  END rsp_hi[27]
  PIN rsp_hi[28]
    DIRECTION INPUT ;
    USE SIGNAL ;
    PORT
      LAYER M5 ;
        RECT  102.528 25.836 102.552 25.92 ;
    END
  END rsp_hi[28]
  PIN rsp_hi[29]
    DIRECTION INPUT ;
    USE SIGNAL ;
    PORT
      LAYER M3 ;
        RECT  103.5 25.882 103.518 25.92 ;
    END
  END rsp_hi[29]
  PIN rsp_hi[2]
    DIRECTION INPUT ;
    USE SIGNAL ;
    PORT
      LAYER M5 ;
        RECT  77.52 25.836 77.544 25.92 ;
    END
  END rsp_hi[2]
  PIN rsp_hi[30]
    DIRECTION INPUT ;
    USE SIGNAL ;
    PORT
      LAYER M5 ;
        RECT  104.448 25.836 104.472 25.92 ;
    END
  END rsp_hi[30]
  PIN rsp_hi[31]
    DIRECTION INPUT ;
    USE SIGNAL ;
    PORT
      LAYER M3 ;
        RECT  105.444 25.882 105.462 25.92 ;
    END
  END rsp_hi[31]
  PIN rsp_hi[32]
    DIRECTION INPUT ;
    USE SIGNAL ;
    PORT
      LAYER M5 ;
        RECT  106.368 25.836 106.392 25.92 ;
    END
  END rsp_hi[32]
  PIN rsp_hi[33]
    DIRECTION INPUT ;
    USE SIGNAL ;
    PORT
      LAYER M3 ;
        RECT  107.352 25.882 107.37 25.92 ;
    END
  END rsp_hi[33]
  PIN rsp_hi[34]
    DIRECTION INPUT ;
    USE SIGNAL ;
    PORT
      LAYER M5 ;
        RECT  108.336 25.836 108.36 25.92 ;
    END
  END rsp_hi[34]
  PIN rsp_hi[35]
    DIRECTION INPUT ;
    USE SIGNAL ;
    PORT
      LAYER M3 ;
        RECT  109.296 25.882 109.314 25.92 ;
    END
  END rsp_hi[35]
  PIN rsp_hi[36]
    DIRECTION INPUT ;
    USE SIGNAL ;
    PORT
      LAYER M5 ;
        RECT  110.256 25.836 110.28 25.92 ;
    END
  END rsp_hi[36]
  PIN rsp_hi[37]
    DIRECTION INPUT ;
    USE SIGNAL ;
    PORT
      LAYER M3 ;
        RECT  111.204 25.882 111.222 25.92 ;
    END
  END rsp_hi[37]
  PIN rsp_hi[38]
    DIRECTION INPUT ;
    USE SIGNAL ;
    PORT
      LAYER M5 ;
        RECT  112.176 25.836 112.2 25.92 ;
    END
  END rsp_hi[38]
  PIN rsp_hi[39]
    DIRECTION INPUT ;
    USE SIGNAL ;
    PORT
      LAYER M3 ;
        RECT  113.148 25.882 113.166 25.92 ;
    END
  END rsp_hi[39]
  PIN rsp_hi[3]
    DIRECTION INPUT ;
    USE SIGNAL ;
    PORT
      LAYER M3 ;
        RECT  78.48 25.882 78.498 25.92 ;
    END
  END rsp_hi[3]
  PIN rsp_hi[40]
    DIRECTION INPUT ;
    USE SIGNAL ;
    PORT
      LAYER M5 ;
        RECT  114.096 25.836 114.12 25.92 ;
    END
  END rsp_hi[40]
  PIN rsp_hi[41]
    DIRECTION INPUT ;
    USE SIGNAL ;
    PORT
      LAYER M3 ;
        RECT  115.056 25.882 115.074 25.92 ;
    END
  END rsp_hi[41]
  PIN rsp_hi[42]
    DIRECTION INPUT ;
    USE SIGNAL ;
    PORT
      LAYER M5 ;
        RECT  116.016 25.836 116.04 25.92 ;
    END
  END rsp_hi[42]
  PIN rsp_hi[43]
    DIRECTION INPUT ;
    USE SIGNAL ;
    PORT
      LAYER M3 ;
        RECT  117 25.882 117.018 25.92 ;
    END
  END rsp_hi[43]
  PIN rsp_hi[44]
    DIRECTION INPUT ;
    USE SIGNAL ;
    PORT
      LAYER M5 ;
        RECT  117.936 25.836 117.96 25.92 ;
    END
  END rsp_hi[44]
  PIN rsp_hi[45]
    DIRECTION INPUT ;
    USE SIGNAL ;
    PORT
      LAYER M3 ;
        RECT  118.908 25.882 118.926 25.92 ;
    END
  END rsp_hi[45]
  PIN rsp_hi[46]
    DIRECTION INPUT ;
    USE SIGNAL ;
    PORT
      LAYER M5 ;
        RECT  119.856 25.836 119.88 25.92 ;
    END
  END rsp_hi[46]
  PIN rsp_hi[47]
    DIRECTION INPUT ;
    USE SIGNAL ;
    PORT
      LAYER M3 ;
        RECT  120.816 25.882 120.834 25.92 ;
    END
  END rsp_hi[47]
  PIN rsp_hi[48]
    DIRECTION INPUT ;
    USE SIGNAL ;
    PORT
      LAYER M5 ;
        RECT  121.776 25.836 121.8 25.92 ;
    END
  END rsp_hi[48]
  PIN rsp_hi[49]
    DIRECTION INPUT ;
    USE SIGNAL ;
    PORT
      LAYER M3 ;
        RECT  122.76 25.882 122.778 25.92 ;
    END
  END rsp_hi[49]
  PIN rsp_hi[4]
    DIRECTION INPUT ;
    USE SIGNAL ;
    PORT
      LAYER M5 ;
        RECT  79.44 25.836 79.464 25.92 ;
    END
  END rsp_hi[4]
  PIN rsp_hi[50]
    DIRECTION INPUT ;
    USE SIGNAL ;
    PORT
      LAYER M5 ;
        RECT  123.696 25.836 123.72 25.92 ;
    END
  END rsp_hi[50]
  PIN rsp_hi[51]
    DIRECTION INPUT ;
    USE SIGNAL ;
    PORT
      LAYER M3 ;
        RECT  124.668 25.882 124.686 25.92 ;
    END
  END rsp_hi[51]
  PIN rsp_hi[52]
    DIRECTION INPUT ;
    USE SIGNAL ;
    PORT
      LAYER M5 ;
        RECT  125.664 25.836 125.688 25.92 ;
    END
  END rsp_hi[52]
  PIN rsp_hi[53]
    DIRECTION INPUT ;
    USE SIGNAL ;
    PORT
      LAYER M3 ;
        RECT  126.612 25.882 126.63 25.92 ;
    END
  END rsp_hi[53]
  PIN rsp_hi[54]
    DIRECTION INPUT ;
    USE SIGNAL ;
    PORT
      LAYER M5 ;
        RECT  127.584 25.836 127.608 25.92 ;
    END
  END rsp_hi[54]
  PIN rsp_hi[55]
    DIRECTION INPUT ;
    USE SIGNAL ;
    PORT
      LAYER M3 ;
        RECT  128.52 25.882 128.538 25.92 ;
    END
  END rsp_hi[55]
  PIN rsp_hi[56]
    DIRECTION INPUT ;
    USE SIGNAL ;
    PORT
      LAYER M5 ;
        RECT  129.504 25.836 129.528 25.92 ;
    END
  END rsp_hi[56]
  PIN rsp_hi[57]
    DIRECTION INPUT ;
    USE SIGNAL ;
    PORT
      LAYER M3 ;
        RECT  130.464 25.882 130.482 25.92 ;
    END
  END rsp_hi[57]
  PIN rsp_hi[58]
    DIRECTION INPUT ;
    USE SIGNAL ;
    PORT
      LAYER M5 ;
        RECT  131.424 25.836 131.448 25.92 ;
    END
  END rsp_hi[58]
  PIN rsp_hi[59]
    DIRECTION INPUT ;
    USE SIGNAL ;
    PORT
      LAYER M3 ;
        RECT  132.372 25.882 132.39 25.92 ;
    END
  END rsp_hi[59]
  PIN rsp_hi[5]
    DIRECTION INPUT ;
    USE SIGNAL ;
    PORT
      LAYER M3 ;
        RECT  80.388 25.882 80.406 25.92 ;
    END
  END rsp_hi[5]
  PIN rsp_hi[60]
    DIRECTION INPUT ;
    USE SIGNAL ;
    PORT
      LAYER M5 ;
        RECT  133.344 25.836 133.368 25.92 ;
    END
  END rsp_hi[60]
  PIN rsp_hi[61]
    DIRECTION INPUT ;
    USE SIGNAL ;
    PORT
      LAYER M3 ;
        RECT  134.316 25.882 134.334 25.92 ;
    END
  END rsp_hi[61]
  PIN rsp_hi[62]
    DIRECTION INPUT ;
    USE SIGNAL ;
    PORT
      LAYER M5 ;
        RECT  135.264 25.836 135.288 25.92 ;
    END
  END rsp_hi[62]
  PIN rsp_hi[63]
    DIRECTION INPUT ;
    USE SIGNAL ;
    PORT
      LAYER M3 ;
        RECT  136.224 25.882 136.242 25.92 ;
    END
  END rsp_hi[63]
  PIN rsp_hi[64]
    DIRECTION INPUT ;
    USE SIGNAL ;
    PORT
      LAYER M5 ;
        RECT  137.184 25.836 137.208 25.92 ;
    END
  END rsp_hi[64]
  PIN rsp_hi[65]
    DIRECTION INPUT ;
    USE SIGNAL ;
    PORT
      LAYER M3 ;
        RECT  138.168 25.882 138.186 25.92 ;
    END
  END rsp_hi[65]
  PIN rsp_hi[66]
    DIRECTION INPUT ;
    USE SIGNAL ;
    PORT
      LAYER M5 ;
        RECT  139.104 25.836 139.128 25.92 ;
    END
  END rsp_hi[66]
  PIN rsp_hi[67]
    DIRECTION INPUT ;
    USE SIGNAL ;
    PORT
      LAYER M3 ;
        RECT  140.076 25.882 140.094 25.92 ;
    END
  END rsp_hi[67]
  PIN rsp_hi[68]
    DIRECTION INPUT ;
    USE SIGNAL ;
    PORT
      LAYER M5 ;
        RECT  141.024 25.836 141.048 25.92 ;
    END
  END rsp_hi[68]
  PIN rsp_hi[69]
    DIRECTION INPUT ;
    USE SIGNAL ;
    PORT
      LAYER M3 ;
        RECT  142.02 25.882 142.038 25.92 ;
    END
  END rsp_hi[69]
  PIN rsp_hi[6]
    DIRECTION INPUT ;
    USE SIGNAL ;
    PORT
      LAYER M5 ;
        RECT  81.36 25.836 81.384 25.92 ;
    END
  END rsp_hi[6]
  PIN rsp_hi[70]
    DIRECTION INPUT ;
    USE SIGNAL ;
    PORT
      LAYER M5 ;
        RECT  142.992 25.836 143.016 25.92 ;
    END
  END rsp_hi[70]
  PIN rsp_hi[71]
    DIRECTION INPUT ;
    USE SIGNAL ;
    PORT
      LAYER M3 ;
        RECT  143.928 25.882 143.946 25.92 ;
    END
  END rsp_hi[71]
  PIN rsp_hi[72]
    DIRECTION INPUT ;
    USE SIGNAL ;
    PORT
      LAYER M5 ;
        RECT  144.912 25.836 144.936 25.92 ;
    END
  END rsp_hi[72]
  PIN rsp_hi[73]
    DIRECTION INPUT ;
    USE SIGNAL ;
    PORT
      LAYER M3 ;
        RECT  145.872 25.882 145.89 25.92 ;
    END
  END rsp_hi[73]
  PIN rsp_hi[74]
    DIRECTION INPUT ;
    USE SIGNAL ;
    PORT
      LAYER M5 ;
        RECT  146.832 25.836 146.856 25.92 ;
    END
  END rsp_hi[74]
  PIN rsp_hi[75]
    DIRECTION INPUT ;
    USE SIGNAL ;
    PORT
      LAYER M3 ;
        RECT  147.78 25.882 147.798 25.92 ;
    END
  END rsp_hi[75]
  PIN rsp_hi[76]
    DIRECTION INPUT ;
    USE SIGNAL ;
    PORT
      LAYER M5 ;
        RECT  148.752 25.836 148.776 25.92 ;
    END
  END rsp_hi[76]
  PIN rsp_hi[77]
    DIRECTION INPUT ;
    USE SIGNAL ;
    PORT
      LAYER M3 ;
        RECT  149.724 25.882 149.742 25.92 ;
    END
  END rsp_hi[77]
  PIN rsp_hi[7]
    DIRECTION INPUT ;
    USE SIGNAL ;
    PORT
      LAYER M3 ;
        RECT  82.332 25.882 82.35 25.92 ;
    END
  END rsp_hi[7]
  PIN rsp_hi[8]
    DIRECTION INPUT ;
    USE SIGNAL ;
    PORT
      LAYER M5 ;
        RECT  83.28 25.836 83.304 25.92 ;
    END
  END rsp_hi[8]
  PIN rsp_hi[9]
    DIRECTION INPUT ;
    USE SIGNAL ;
    PORT
      LAYER M3 ;
        RECT  84.24 25.882 84.258 25.92 ;
    END
  END rsp_hi[9]
  PIN rsp_layer[0]
    DIRECTION OUTPUT ;
    USE SIGNAL ;
    PORT
      LAYER M4 ;
        RECT  0 15.408 0.084 15.432 ;
    END
  END rsp_layer[0]
  PIN rsp_layer[1]
    DIRECTION OUTPUT ;
    USE SIGNAL ;
    PORT
      LAYER M4 ;
        RECT  0 15.696 0.084 15.72 ;
    END
  END rsp_layer[1]
  PIN rsp_layer[2]
    DIRECTION OUTPUT ;
    USE SIGNAL ;
    PORT
      LAYER M4 ;
        RECT  0 15.936 0.084 15.96 ;
    END
  END rsp_layer[2]
  PIN rsp_layer[3]
    DIRECTION OUTPUT ;
    USE SIGNAL ;
    PORT
      LAYER M4 ;
        RECT  0 16.176 0.084 16.2 ;
    END
  END rsp_layer[3]
  PIN rsp_layer[4]
    DIRECTION OUTPUT ;
    USE SIGNAL ;
    PORT
      LAYER M4 ;
        RECT  0 16.464 0.084 16.488 ;
    END
  END rsp_layer[4]
  PIN rsp_layer[5]
    DIRECTION OUTPUT ;
    USE SIGNAL ;
    PORT
      LAYER M4 ;
        RECT  0 16.704 0.084 16.728 ;
    END
  END rsp_layer[5]
  PIN rsp_lo[0]
    DIRECTION INPUT ;
    USE SIGNAL ;
    PORT
      LAYER M3 ;
        RECT  75.096 0 75.114 0.038 ;
    END
  END rsp_lo[0]
  PIN rsp_lo[10]
    DIRECTION INPUT ;
    USE SIGNAL ;
    PORT
      LAYER M3 ;
        RECT  84.78 0 84.798 0.038 ;
    END
  END rsp_lo[10]
  PIN rsp_lo[11]
    DIRECTION INPUT ;
    USE SIGNAL ;
    PORT
      LAYER M5 ;
        RECT  85.776 0 85.8 0.084 ;
    END
  END rsp_lo[11]
  PIN rsp_lo[12]
    DIRECTION INPUT ;
    USE SIGNAL ;
    PORT
      LAYER M3 ;
        RECT  86.724 0 86.742 0.038 ;
    END
  END rsp_lo[12]
  PIN rsp_lo[13]
    DIRECTION INPUT ;
    USE SIGNAL ;
    PORT
      LAYER M5 ;
        RECT  87.696 0 87.72 0.084 ;
    END
  END rsp_lo[13]
  PIN rsp_lo[14]
    DIRECTION INPUT ;
    USE SIGNAL ;
    PORT
      LAYER M3 ;
        RECT  88.668 0 88.686 0.038 ;
    END
  END rsp_lo[14]
  PIN rsp_lo[15]
    DIRECTION INPUT ;
    USE SIGNAL ;
    PORT
      LAYER M5 ;
        RECT  89.616 0 89.64 0.084 ;
    END
  END rsp_lo[15]
  PIN rsp_lo[16]
    DIRECTION INPUT ;
    USE SIGNAL ;
    PORT
      LAYER M3 ;
        RECT  90.612 0 90.63 0.038 ;
    END
  END rsp_lo[16]
  PIN rsp_lo[17]
    DIRECTION INPUT ;
    USE SIGNAL ;
    PORT
      LAYER M5 ;
        RECT  91.584 0 91.608 0.084 ;
    END
  END rsp_lo[17]
  PIN rsp_lo[18]
    DIRECTION INPUT ;
    USE SIGNAL ;
    PORT
      LAYER M3 ;
        RECT  92.556 0 92.574 0.038 ;
    END
  END rsp_lo[18]
  PIN rsp_lo[19]
    DIRECTION INPUT ;
    USE SIGNAL ;
    PORT
      LAYER M5 ;
        RECT  93.504 0 93.528 0.084 ;
    END
  END rsp_lo[19]
  PIN rsp_lo[1]
    DIRECTION INPUT ;
    USE SIGNAL ;
    PORT
      LAYER M5 ;
        RECT  76.08 0 76.104 0.084 ;
    END
  END rsp_lo[1]
  PIN rsp_lo[20]
    DIRECTION INPUT ;
    USE SIGNAL ;
    PORT
      LAYER M3 ;
        RECT  94.5 0 94.518 0.038 ;
    END
  END rsp_lo[20]
  PIN rsp_lo[21]
    DIRECTION INPUT ;
    USE SIGNAL ;
    PORT
      LAYER M5 ;
        RECT  95.472 0 95.496 0.084 ;
    END
  END rsp_lo[21]
  PIN rsp_lo[22]
    DIRECTION INPUT ;
    USE SIGNAL ;
    PORT
      LAYER M3 ;
        RECT  96.408 0 96.426 0.038 ;
    END
  END rsp_lo[22]
  PIN rsp_lo[23]
    DIRECTION INPUT ;
    USE SIGNAL ;
    PORT
      LAYER M5 ;
        RECT  97.392 0 97.416 0.084 ;
    END
  END rsp_lo[23]
  PIN rsp_lo[24]
    DIRECTION INPUT ;
    USE SIGNAL ;
    PORT
      LAYER M3 ;
        RECT  98.352 0 98.37 0.038 ;
    END
  END rsp_lo[24]
  PIN rsp_lo[25]
    DIRECTION INPUT ;
    USE SIGNAL ;
    PORT
      LAYER M5 ;
        RECT  99.312 0 99.336 0.084 ;
    END
  END rsp_lo[25]
  PIN rsp_lo[26]
    DIRECTION INPUT ;
    USE SIGNAL ;
    PORT
      LAYER M3 ;
        RECT  100.296 0 100.314 0.038 ;
    END
  END rsp_lo[26]
  PIN rsp_lo[27]
    DIRECTION INPUT ;
    USE SIGNAL ;
    PORT
      LAYER M5 ;
        RECT  101.28 0 101.304 0.084 ;
    END
  END rsp_lo[27]
  PIN rsp_lo[28]
    DIRECTION INPUT ;
    USE SIGNAL ;
    PORT
      LAYER M3 ;
        RECT  102.24 0 102.258 0.038 ;
    END
  END rsp_lo[28]
  PIN rsp_lo[29]
    DIRECTION INPUT ;
    USE SIGNAL ;
    PORT
      LAYER M5 ;
        RECT  103.2 0 103.224 0.084 ;
    END
  END rsp_lo[29]
  PIN rsp_lo[2]
    DIRECTION INPUT ;
    USE SIGNAL ;
    PORT
      LAYER M3 ;
        RECT  77.04 0 77.058 0.038 ;
    END
  END rsp_lo[2]
  PIN rsp_lo[30]
    DIRECTION INPUT ;
    USE SIGNAL ;
    PORT
      LAYER M3 ;
        RECT  104.184 0 104.202 0.038 ;
    END
  END rsp_lo[30]
  PIN rsp_lo[31]
    DIRECTION INPUT ;
    USE SIGNAL ;
    PORT
      LAYER M5 ;
        RECT  105.12 0 105.144 0.084 ;
    END
  END rsp_lo[31]
  PIN rsp_lo[32]
    DIRECTION INPUT ;
    USE SIGNAL ;
    PORT
      LAYER M3 ;
        RECT  106.092 0 106.11 0.038 ;
    END
  END rsp_lo[32]
  PIN rsp_lo[33]
    DIRECTION INPUT ;
    USE SIGNAL ;
    PORT
      LAYER M5 ;
        RECT  107.088 0 107.112 0.084 ;
    END
  END rsp_lo[33]
  PIN rsp_lo[34]
    DIRECTION INPUT ;
    USE SIGNAL ;
    PORT
      LAYER M3 ;
        RECT  108.036 0 108.054 0.038 ;
    END
  END rsp_lo[34]
  PIN rsp_lo[35]
    DIRECTION INPUT ;
    USE SIGNAL ;
    PORT
      LAYER M5 ;
        RECT  109.008 0 109.032 0.084 ;
    END
  END rsp_lo[35]
  PIN rsp_lo[36]
    DIRECTION INPUT ;
    USE SIGNAL ;
    PORT
      LAYER M3 ;
        RECT  109.98 0 109.998 0.038 ;
    END
  END rsp_lo[36]
  PIN rsp_lo[37]
    DIRECTION INPUT ;
    USE SIGNAL ;
    PORT
      LAYER M5 ;
        RECT  110.928 0 110.952 0.084 ;
    END
  END rsp_lo[37]
  PIN rsp_lo[38]
    DIRECTION INPUT ;
    USE SIGNAL ;
    PORT
      LAYER M3 ;
        RECT  111.924 0 111.942 0.038 ;
    END
  END rsp_lo[38]
  PIN rsp_lo[39]
    DIRECTION INPUT ;
    USE SIGNAL ;
    PORT
      LAYER M5 ;
        RECT  112.896 0 112.92 0.084 ;
    END
  END rsp_lo[39]
  PIN rsp_lo[3]
    DIRECTION INPUT ;
    USE SIGNAL ;
    PORT
      LAYER M5 ;
        RECT  78 0 78.024 0.084 ;
    END
  END rsp_lo[3]
  PIN rsp_lo[40]
    DIRECTION INPUT ;
    USE SIGNAL ;
    PORT
      LAYER M3 ;
        RECT  113.868 0 113.886 0.038 ;
    END
  END rsp_lo[40]
  PIN rsp_lo[41]
    DIRECTION INPUT ;
    USE SIGNAL ;
    PORT
      LAYER M5 ;
        RECT  114.816 0 114.84 0.084 ;
    END
  END rsp_lo[41]
  PIN rsp_lo[42]
    DIRECTION INPUT ;
    USE SIGNAL ;
    PORT
      LAYER M3 ;
        RECT  115.812 0 115.83 0.038 ;
    END
  END rsp_lo[42]
  PIN rsp_lo[43]
    DIRECTION INPUT ;
    USE SIGNAL ;
    PORT
      LAYER M5 ;
        RECT  116.784 0 116.808 0.084 ;
    END
  END rsp_lo[43]
  PIN rsp_lo[44]
    DIRECTION INPUT ;
    USE SIGNAL ;
    PORT
      LAYER M3 ;
        RECT  117.72 0 117.738 0.038 ;
    END
  END rsp_lo[44]
  PIN rsp_lo[45]
    DIRECTION INPUT ;
    USE SIGNAL ;
    PORT
      LAYER M5 ;
        RECT  118.704 0 118.728 0.084 ;
    END
  END rsp_lo[45]
  PIN rsp_lo[46]
    DIRECTION INPUT ;
    USE SIGNAL ;
    PORT
      LAYER M3 ;
        RECT  119.664 0 119.682 0.038 ;
    END
  END rsp_lo[46]
  PIN rsp_lo[47]
    DIRECTION INPUT ;
    USE SIGNAL ;
    PORT
      LAYER M5 ;
        RECT  120.624 0 120.648 0.084 ;
    END
  END rsp_lo[47]
  PIN rsp_lo[48]
    DIRECTION INPUT ;
    USE SIGNAL ;
    PORT
      LAYER M3 ;
        RECT  121.608 0 121.626 0.038 ;
    END
  END rsp_lo[48]
  PIN rsp_lo[49]
    DIRECTION INPUT ;
    USE SIGNAL ;
    PORT
      LAYER M5 ;
        RECT  122.592 0 122.616 0.084 ;
    END
  END rsp_lo[49]
  PIN rsp_lo[4]
    DIRECTION INPUT ;
    USE SIGNAL ;
    PORT
      LAYER M3 ;
        RECT  78.984 0 79.002 0.038 ;
    END
  END rsp_lo[4]
  PIN rsp_lo[50]
    DIRECTION INPUT ;
    USE SIGNAL ;
    PORT
      LAYER M3 ;
        RECT  123.552 0 123.57 0.038 ;
    END
  END rsp_lo[50]
  PIN rsp_lo[51]
    DIRECTION INPUT ;
    USE SIGNAL ;
    PORT
      LAYER M5 ;
        RECT  124.512 0 124.536 0.084 ;
    END
  END rsp_lo[51]
  PIN rsp_lo[52]
    DIRECTION INPUT ;
    USE SIGNAL ;
    PORT
      LAYER M3 ;
        RECT  125.496 0 125.514 0.038 ;
    END
  END rsp_lo[52]
  PIN rsp_lo[53]
    DIRECTION INPUT ;
    USE SIGNAL ;
    PORT
      LAYER M5 ;
        RECT  126.432 0 126.456 0.084 ;
    END
  END rsp_lo[53]
  PIN rsp_lo[54]
    DIRECTION INPUT ;
    USE SIGNAL ;
    PORT
      LAYER M3 ;
        RECT  127.44 0 127.458 0.038 ;
    END
  END rsp_lo[54]
  PIN rsp_lo[55]
    DIRECTION INPUT ;
    USE SIGNAL ;
    PORT
      LAYER M5 ;
        RECT  128.4 0 128.424 0.084 ;
    END
  END rsp_lo[55]
  PIN rsp_lo[56]
    DIRECTION INPUT ;
    USE SIGNAL ;
    PORT
      LAYER M3 ;
        RECT  129.348 0 129.366 0.038 ;
    END
  END rsp_lo[56]
  PIN rsp_lo[57]
    DIRECTION INPUT ;
    USE SIGNAL ;
    PORT
      LAYER M5 ;
        RECT  130.32 0 130.344 0.084 ;
    END
  END rsp_lo[57]
  PIN rsp_lo[58]
    DIRECTION INPUT ;
    USE SIGNAL ;
    PORT
      LAYER M3 ;
        RECT  131.292 0 131.31 0.038 ;
    END
  END rsp_lo[58]
  PIN rsp_lo[59]
    DIRECTION INPUT ;
    USE SIGNAL ;
    PORT
      LAYER M5 ;
        RECT  132.288 0 132.312 0.084 ;
    END
  END rsp_lo[59]
  PIN rsp_lo[5]
    DIRECTION INPUT ;
    USE SIGNAL ;
    PORT
      LAYER M5 ;
        RECT  79.968 0 79.992 0.084 ;
    END
  END rsp_lo[5]
  PIN rsp_lo[60]
    DIRECTION INPUT ;
    USE SIGNAL ;
    PORT
      LAYER M3 ;
        RECT  133.236 0 133.254 0.038 ;
    END
  END rsp_lo[60]
  PIN rsp_lo[61]
    DIRECTION INPUT ;
    USE SIGNAL ;
    PORT
      LAYER M5 ;
        RECT  134.208 0 134.232 0.084 ;
    END
  END rsp_lo[61]
  PIN rsp_lo[62]
    DIRECTION INPUT ;
    USE SIGNAL ;
    PORT
      LAYER M3 ;
        RECT  135.18 0 135.198 0.038 ;
    END
  END rsp_lo[62]
  PIN rsp_lo[63]
    DIRECTION INPUT ;
    USE SIGNAL ;
    PORT
      LAYER M5 ;
        RECT  136.128 0 136.152 0.084 ;
    END
  END rsp_lo[63]
  PIN rsp_lo[64]
    DIRECTION INPUT ;
    USE SIGNAL ;
    PORT
      LAYER M3 ;
        RECT  137.124 0 137.142 0.038 ;
    END
  END rsp_lo[64]
  PIN rsp_lo[65]
    DIRECTION INPUT ;
    USE SIGNAL ;
    PORT
      LAYER M5 ;
        RECT  138.096 0 138.12 0.084 ;
    END
  END rsp_lo[65]
  PIN rsp_lo[66]
    DIRECTION INPUT ;
    USE SIGNAL ;
    PORT
      LAYER M3 ;
        RECT  139.032 0 139.05 0.038 ;
    END
  END rsp_lo[66]
  PIN rsp_lo[67]
    DIRECTION INPUT ;
    USE SIGNAL ;
    PORT
      LAYER M5 ;
        RECT  140.016 0 140.04 0.084 ;
    END
  END rsp_lo[67]
  PIN rsp_lo[68]
    DIRECTION INPUT ;
    USE SIGNAL ;
    PORT
      LAYER M3 ;
        RECT  140.976 0 140.994 0.038 ;
    END
  END rsp_lo[68]
  PIN rsp_lo[69]
    DIRECTION INPUT ;
    USE SIGNAL ;
    PORT
      LAYER M5 ;
        RECT  141.936 0 141.96 0.084 ;
    END
  END rsp_lo[69]
  PIN rsp_lo[6]
    DIRECTION INPUT ;
    USE SIGNAL ;
    PORT
      LAYER M3 ;
        RECT  80.928 0 80.946 0.038 ;
    END
  END rsp_lo[6]
  PIN rsp_lo[70]
    DIRECTION INPUT ;
    USE SIGNAL ;
    PORT
      LAYER M3 ;
        RECT  142.92 0 142.938 0.038 ;
    END
  END rsp_lo[70]
  PIN rsp_lo[71]
    DIRECTION INPUT ;
    USE SIGNAL ;
    PORT
      LAYER M5 ;
        RECT  143.904 0 143.928 0.084 ;
    END
  END rsp_lo[71]
  PIN rsp_lo[72]
    DIRECTION INPUT ;
    USE SIGNAL ;
    PORT
      LAYER M3 ;
        RECT  144.864 0 144.882 0.038 ;
    END
  END rsp_lo[72]
  PIN rsp_lo[73]
    DIRECTION INPUT ;
    USE SIGNAL ;
    PORT
      LAYER M5 ;
        RECT  145.824 0 145.848 0.084 ;
    END
  END rsp_lo[73]
  PIN rsp_lo[74]
    DIRECTION INPUT ;
    USE SIGNAL ;
    PORT
      LAYER M3 ;
        RECT  146.808 0 146.826 0.038 ;
    END
  END rsp_lo[74]
  PIN rsp_lo[75]
    DIRECTION INPUT ;
    USE SIGNAL ;
    PORT
      LAYER M5 ;
        RECT  147.744 0 147.768 0.084 ;
    END
  END rsp_lo[75]
  PIN rsp_lo[76]
    DIRECTION INPUT ;
    USE SIGNAL ;
    PORT
      LAYER M3 ;
        RECT  148.752 0 148.77 0.038 ;
    END
  END rsp_lo[76]
  PIN rsp_lo[77]
    DIRECTION INPUT ;
    USE SIGNAL ;
    PORT
      LAYER M5 ;
        RECT  149.712 0 149.736 0.084 ;
    END
  END rsp_lo[77]
  PIN rsp_lo[7]
    DIRECTION INPUT ;
    USE SIGNAL ;
    PORT
      LAYER M5 ;
        RECT  81.888 0 81.912 0.084 ;
    END
  END rsp_lo[7]
  PIN rsp_lo[8]
    DIRECTION INPUT ;
    USE SIGNAL ;
    PORT
      LAYER M3 ;
        RECT  82.872 0 82.89 0.038 ;
    END
  END rsp_lo[8]
  PIN rsp_lo[9]
    DIRECTION INPUT ;
    USE SIGNAL ;
    PORT
      LAYER M5 ;
        RECT  83.808 0 83.832 0.084 ;
    END
  END rsp_lo[9]
  PIN rsp_t[0]
    DIRECTION OUTPUT ;
    USE SIGNAL ;
    PORT
      LAYER M4 ;
        RECT  0 16.992 0.084 17.016 ;
    END
  END rsp_t[0]
  PIN rsp_t[10]
    DIRECTION OUTPUT ;
    USE SIGNAL ;
    PORT
      LAYER M4 ;
        RECT  0 19.584 0.084 19.608 ;
    END
  END rsp_t[10]
  PIN rsp_t[11]
    DIRECTION OUTPUT ;
    USE SIGNAL ;
    PORT
      LAYER M4 ;
        RECT  0 19.824 0.084 19.848 ;
    END
  END rsp_t[11]
  PIN rsp_t[12]
    DIRECTION OUTPUT ;
    USE SIGNAL ;
    PORT
      LAYER M4 ;
        RECT  0 20.112 0.084 20.136 ;
    END
  END rsp_t[12]
  PIN rsp_t[13]
    DIRECTION OUTPUT ;
    USE SIGNAL ;
    PORT
      LAYER M4 ;
        RECT  0 20.352 0.084 20.376 ;
    END
  END rsp_t[13]
  PIN rsp_t[1]
    DIRECTION OUTPUT ;
    USE SIGNAL ;
    PORT
      LAYER M4 ;
        RECT  0 17.232 0.084 17.256 ;
    END
  END rsp_t[1]
  PIN rsp_t[2]
    DIRECTION OUTPUT ;
    USE SIGNAL ;
    PORT
      LAYER M4 ;
        RECT  0 17.52 0.084 17.544 ;
    END
  END rsp_t[2]
  PIN rsp_t[3]
    DIRECTION OUTPUT ;
    USE SIGNAL ;
    PORT
      LAYER M4 ;
        RECT  0 17.76 0.084 17.784 ;
    END
  END rsp_t[3]
  PIN rsp_t[4]
    DIRECTION OUTPUT ;
    USE SIGNAL ;
    PORT
      LAYER M4 ;
        RECT  0 18 0.084 18.024 ;
    END
  END rsp_t[4]
  PIN rsp_t[5]
    DIRECTION OUTPUT ;
    USE SIGNAL ;
    PORT
      LAYER M4 ;
        RECT  0 18.288 0.084 18.312 ;
    END
  END rsp_t[5]
  PIN rsp_t[6]
    DIRECTION OUTPUT ;
    USE SIGNAL ;
    PORT
      LAYER M4 ;
        RECT  0 18.528 0.084 18.552 ;
    END
  END rsp_t[6]
  PIN rsp_t[7]
    DIRECTION OUTPUT ;
    USE SIGNAL ;
    PORT
      LAYER M4 ;
        RECT  0 18.816 0.084 18.84 ;
    END
  END rsp_t[7]
  PIN rsp_t[8]
    DIRECTION OUTPUT ;
    USE SIGNAL ;
    PORT
      LAYER M4 ;
        RECT  0 19.056 0.084 19.08 ;
    END
  END rsp_t[8]
  PIN rsp_t[9]
    DIRECTION OUTPUT ;
    USE SIGNAL ;
    PORT
      LAYER M4 ;
        RECT  0 19.296 0.084 19.32 ;
    END
  END rsp_t[9]
  PIN rsp_v
    DIRECTION OUTPUT ;
    USE SIGNAL ;
    PORT
      LAYER M4 ;
        RECT  0 20.64 0.084 20.664 ;
    END
  END rsp_v
  PIN rsp_valid
    DIRECTION OUTPUT ;
    USE SIGNAL ;
    PORT
      LAYER M4 ;
        RECT  0 20.88 0.084 20.904 ;
    END
  END rsp_valid
  PIN rst_n
    DIRECTION INPUT ;
    USE SIGNAL ;
    PORT
      LAYER M4 ;
        RECT  151.116 23.472 151.2 23.496 ;
    END
  END rst_n
  PIN rst_o
    DIRECTION OUTPUT ;
    USE SIGNAL ;
    PORT
      LAYER M4 ;
        RECT  151.116 23.856 151.2 23.88 ;
    END
  END rst_o
  PIN stack_o[0]
    DIRECTION OUTPUT ;
    USE SIGNAL ;
    PORT
      LAYER M4 ;
        RECT  151.116 24.288 151.2 24.312 ;
    END
  END stack_o[0]
  PIN stack_o[1]
    DIRECTION OUTPUT ;
    USE SIGNAL ;
    PORT
      LAYER M4 ;
        RECT  151.116 24.72 151.2 24.744 ;
    END
  END stack_o[1]
  PIN vreq_t[0]
    DIRECTION INPUT ;
    USE SIGNAL ;
    PORT
      LAYER M4 ;
        RECT  0 21.12 0.084 21.144 ;
    END
  END vreq_t[0]
  PIN vreq_t[10]
    DIRECTION INPUT ;
    USE SIGNAL ;
    PORT
      LAYER M4 ;
        RECT  0 23.76 0.084 23.784 ;
    END
  END vreq_t[10]
  PIN vreq_t[11]
    DIRECTION INPUT ;
    USE SIGNAL ;
    PORT
      LAYER M4 ;
        RECT  0 24 0.084 24.024 ;
    END
  END vreq_t[11]
  PIN vreq_t[12]
    DIRECTION INPUT ;
    USE SIGNAL ;
    PORT
      LAYER M4 ;
        RECT  0 24.24 0.084 24.264 ;
    END
  END vreq_t[12]
  PIN vreq_t[13]
    DIRECTION INPUT ;
    USE SIGNAL ;
    PORT
      LAYER M4 ;
        RECT  0 24.528 0.084 24.552 ;
    END
  END vreq_t[13]
  PIN vreq_t[1]
    DIRECTION INPUT ;
    USE SIGNAL ;
    PORT
      LAYER M4 ;
        RECT  0 21.408 0.084 21.432 ;
    END
  END vreq_t[1]
  PIN vreq_t[2]
    DIRECTION INPUT ;
    USE SIGNAL ;
    PORT
      LAYER M4 ;
        RECT  0 21.648 0.084 21.672 ;
    END
  END vreq_t[2]
  PIN vreq_t[3]
    DIRECTION INPUT ;
    USE SIGNAL ;
    PORT
      LAYER M4 ;
        RECT  0 21.936 0.084 21.96 ;
    END
  END vreq_t[3]
  PIN vreq_t[4]
    DIRECTION INPUT ;
    USE SIGNAL ;
    PORT
      LAYER M4 ;
        RECT  0 22.176 0.084 22.2 ;
    END
  END vreq_t[4]
  PIN vreq_t[5]
    DIRECTION INPUT ;
    USE SIGNAL ;
    PORT
      LAYER M4 ;
        RECT  0 22.416 0.084 22.44 ;
    END
  END vreq_t[5]
  PIN vreq_t[6]
    DIRECTION INPUT ;
    USE SIGNAL ;
    PORT
      LAYER M4 ;
        RECT  0 22.704 0.084 22.728 ;
    END
  END vreq_t[6]
  PIN vreq_t[7]
    DIRECTION INPUT ;
    USE SIGNAL ;
    PORT
      LAYER M4 ;
        RECT  0 22.944 0.084 22.968 ;
    END
  END vreq_t[7]
  PIN vreq_t[8]
    DIRECTION INPUT ;
    USE SIGNAL ;
    PORT
      LAYER M4 ;
        RECT  0 23.232 0.084 23.256 ;
    END
  END vreq_t[8]
  PIN vreq_t[9]
    DIRECTION INPUT ;
    USE SIGNAL ;
    PORT
      LAYER M4 ;
        RECT  0 23.472 0.084 23.496 ;
    END
  END vreq_t[9]
  PIN vreq_valid
    DIRECTION INPUT ;
    USE SIGNAL ;
    PORT
      LAYER M4 ;
        RECT  0 24.768 0.084 24.792 ;
    END
  END vreq_valid
  PIN VDD
    DIRECTION INOUT ;
    USE POWER ;
    PORT
      LAYER M5 ;
        RECT  148.392 2.151 148.512 23.769 ;
        RECT  142.992 2.151 143.112 23.769 ;
        RECT  137.592 2.151 137.712 23.769 ;
        RECT  132.192 2.151 132.312 23.769 ;
        RECT  126.792 2.151 126.912 23.769 ;
        RECT  121.392 2.151 121.512 23.769 ;
        RECT  115.992 2.151 116.112 23.769 ;
        RECT  110.592 2.151 110.712 23.769 ;
        RECT  105.192 2.151 105.312 23.769 ;
        RECT  99.792 2.151 99.912 23.769 ;
        RECT  94.392 2.151 94.512 23.769 ;
        RECT  88.992 2.151 89.112 23.769 ;
        RECT  83.592 2.151 83.712 23.769 ;
        RECT  78.192 2.151 78.312 23.769 ;
        RECT  72.792 2.151 72.912 23.769 ;
        RECT  67.392 2.151 67.512 23.769 ;
        RECT  61.992 2.151 62.112 23.769 ;
        RECT  56.592 2.151 56.712 23.769 ;
        RECT  51.192 2.151 51.312 23.769 ;
        RECT  45.792 2.151 45.912 23.769 ;
        RECT  40.392 2.151 40.512 23.769 ;
        RECT  34.992 2.151 35.112 23.769 ;
        RECT  29.592 2.151 29.712 23.769 ;
        RECT  24.192 2.151 24.312 23.769 ;
        RECT  18.792 2.151 18.912 23.769 ;
        RECT  13.392 2.151 13.512 23.769 ;
        RECT  7.992 2.151 8.112 23.769 ;
        RECT  2.592 2.151 2.712 23.769 ;
    END
  END VDD
  PIN VSS
    DIRECTION INOUT ;
    USE GROUND ;
    PORT
      LAYER M5 ;
        RECT  148.2 2.137 148.32 23.783 ;
        RECT  142.8 2.137 142.92 23.783 ;
        RECT  137.4 2.137 137.52 23.783 ;
        RECT  132 2.137 132.12 23.783 ;
        RECT  126.6 2.137 126.72 23.783 ;
        RECT  121.2 2.137 121.32 23.783 ;
        RECT  115.8 2.137 115.92 23.783 ;
        RECT  110.4 2.137 110.52 23.783 ;
        RECT  105 2.137 105.12 23.783 ;
        RECT  99.6 2.137 99.72 23.783 ;
        RECT  94.2 2.137 94.32 23.783 ;
        RECT  88.8 2.137 88.92 23.783 ;
        RECT  83.4 2.137 83.52 23.783 ;
        RECT  78 2.137 78.12 23.783 ;
        RECT  72.6 2.137 72.72 23.783 ;
        RECT  67.2 2.137 67.32 23.783 ;
        RECT  61.8 2.137 61.92 23.783 ;
        RECT  56.4 2.137 56.52 23.783 ;
        RECT  51 2.137 51.12 23.783 ;
        RECT  45.6 2.137 45.72 23.783 ;
        RECT  40.2 2.137 40.32 23.783 ;
        RECT  34.8 2.137 34.92 23.783 ;
        RECT  29.4 2.137 29.52 23.783 ;
        RECT  24 2.137 24.12 23.783 ;
        RECT  18.6 2.137 18.72 23.783 ;
        RECT  13.2 2.137 13.32 23.783 ;
        RECT  7.8 2.137 7.92 23.783 ;
        RECT  2.4 2.137 2.52 23.783 ;
    END
  END VSS
  OBS
    LAYER RVTN ;
     RECT  2.16 2.16 149.04 2.295 ;
     RECT  2.16 2.565 149.04 2.835 ;
     RECT  2.16 3.105 149.04 3.375 ;
     RECT  2.16 3.645 149.04 3.915 ;
     RECT  2.16 4.185 149.04 4.455 ;
     RECT  2.16 4.725 149.04 4.995 ;
     RECT  2.16 5.265 149.04 5.535 ;
     RECT  2.16 5.805 149.04 6.075 ;
     RECT  2.16 6.345 149.04 6.615 ;
     RECT  2.16 6.885 149.04 7.155 ;
     RECT  2.16 7.425 149.04 7.695 ;
     RECT  2.16 7.965 149.04 8.235 ;
     RECT  2.16 8.505 149.04 8.775 ;
     RECT  2.16 9.045 149.04 9.315 ;
     RECT  2.16 9.585 149.04 9.855 ;
     RECT  2.16 10.125 149.04 10.395 ;
     RECT  2.16 10.665 149.04 10.935 ;
     RECT  2.16 11.205 149.04 11.475 ;
     RECT  2.16 11.745 149.04 12.015 ;
     RECT  2.16 12.285 149.04 12.555 ;
     RECT  2.16 12.825 149.04 13.095 ;
     RECT  2.16 13.365 149.04 13.635 ;
     RECT  2.16 13.905 149.04 14.175 ;
     RECT  2.16 14.445 149.04 14.715 ;
     RECT  2.16 14.985 149.04 15.255 ;
     RECT  2.16 15.525 149.04 15.795 ;
     RECT  2.16 16.065 149.04 16.335 ;
     RECT  2.16 16.605 149.04 16.875 ;
     RECT  2.16 17.145 149.04 17.415 ;
     RECT  2.16 17.685 149.04 17.955 ;
     RECT  2.16 18.225 149.04 18.495 ;
     RECT  2.16 18.765 149.04 19.035 ;
     RECT  2.16 19.305 149.04 19.575 ;
     RECT  2.16 19.845 149.04 20.115 ;
     RECT  2.16 20.385 149.04 20.655 ;
     RECT  2.16 20.925 149.04 21.195 ;
     RECT  2.16 21.465 149.04 21.735 ;
     RECT  2.16 22.005 149.04 22.275 ;
     RECT  2.16 22.545 149.04 22.815 ;
     RECT  2.16 23.085 149.04 23.355 ;
     RECT  2.16 23.625 149.04 23.76 ;
    LAYER RVTP ;
     RECT  2.16 2.295 149.04 2.565 ;
     RECT  2.16 2.835 149.04 3.105 ;
     RECT  2.16 3.375 149.04 3.645 ;
     RECT  2.16 3.915 149.04 4.185 ;
     RECT  2.16 4.455 149.04 4.725 ;
     RECT  2.16 4.995 149.04 5.265 ;
     RECT  2.16 5.535 149.04 5.805 ;
     RECT  2.16 6.075 149.04 6.345 ;
     RECT  2.16 6.615 149.04 6.885 ;
     RECT  2.16 7.155 149.04 7.425 ;
     RECT  2.16 7.695 149.04 7.965 ;
     RECT  2.16 8.235 149.04 8.505 ;
     RECT  2.16 8.775 149.04 9.045 ;
     RECT  2.16 9.315 149.04 9.585 ;
     RECT  2.16 9.855 149.04 10.125 ;
     RECT  2.16 10.395 149.04 10.665 ;
     RECT  2.16 10.935 149.04 11.205 ;
     RECT  2.16 11.475 149.04 11.745 ;
     RECT  2.16 12.015 149.04 12.285 ;
     RECT  2.16 12.555 149.04 12.825 ;
     RECT  2.16 13.095 149.04 13.365 ;
     RECT  2.16 13.635 149.04 13.905 ;
     RECT  2.16 14.175 149.04 14.445 ;
     RECT  2.16 14.715 149.04 14.985 ;
     RECT  2.16 15.255 149.04 15.525 ;
     RECT  2.16 15.795 149.04 16.065 ;
     RECT  2.16 16.335 149.04 16.605 ;
     RECT  2.16 16.875 149.04 17.145 ;
     RECT  2.16 17.415 149.04 17.685 ;
     RECT  2.16 17.955 149.04 18.225 ;
     RECT  2.16 18.495 149.04 18.765 ;
     RECT  2.16 19.035 149.04 19.305 ;
     RECT  2.16 19.575 149.04 19.845 ;
     RECT  2.16 20.115 149.04 20.385 ;
     RECT  2.16 20.655 149.04 20.925 ;
     RECT  2.16 21.195 149.04 21.465 ;
     RECT  2.16 21.735 149.04 22.005 ;
     RECT  2.16 22.275 149.04 22.545 ;
     RECT  2.16 22.815 149.04 23.085 ;
     RECT  2.16 23.355 149.04 23.625 ;
    LAYER M1 ;
     RECT  2.16 2.151 149.04 23.769 ;
    LAYER M2 ;
     RECT  0.103 22.788 0.139 22.806 ;
     RECT  0.139 22.752 1.399 22.806 ;
     RECT  1.471 3.276 2.16 3.294 ;
     RECT  0.535 11.376 2.16 11.394 ;
     RECT  0.535 12.294 2.16 12.312 ;
     RECT  0.535 14.184 2.16 14.202 ;
     RECT  0.103 20.196 2.16 20.214 ;
     RECT  0.103 21.51 2.16 21.528 ;
     RECT  1.399 22.482 2.16 22.806 ;
     RECT  0.139 23.67 2.16 23.688 ;
     RECT  2.16 2.151 3.235 23.769 ;
     RECT  3.235 2.151 3.407 23.814 ;
     RECT  3.407 2.151 4.387 23.769 ;
     RECT  4.387 2.106 5.027 23.769 ;
     RECT  5.027 2.151 7.231 23.769 ;
     RECT  7.231 2.151 7.403 23.922 ;
     RECT  7.403 2.151 14.935 23.769 ;
     RECT  14.935 1.728 15.071 23.769 ;
     RECT  16.987 0.036 17.087 0.054 ;
     RECT  18.571 25.866 18.815 25.884 ;
     RECT  15.071 2.151 25.663 23.769 ;
     RECT  25.663 2.106 26.483 23.769 ;
     RECT  40.207 0.036 40.379 0.054 ;
     RECT  26.483 2.151 41.719 23.769 ;
     RECT  41.719 2.106 42.575 23.769 ;
     RECT  42.575 2.151 45.499 23.769 ;
     RECT  45.751 25.866 46.139 25.884 ;
     RECT  45.499 2.106 46.391 23.769 ;
     RECT  49.603 25.866 49.703 25.884 ;
     RECT  46.391 2.151 53.707 23.769 ;
     RECT  53.707 1.728 53.807 23.769 ;
     RECT  53.807 2.151 69.799 23.769 ;
     RECT  69.799 2.106 70.547 23.769 ;
     RECT  70.547 2.151 72.715 23.769 ;
     RECT  72.715 2.151 72.995 23.85 ;
     RECT  74.551 25.866 74.651 25.884 ;
     RECT  72.995 2.151 82.651 23.769 ;
     RECT  82.651 1.728 82.895 23.769 ;
     RECT  82.895 2.151 93.271 23.769 ;
     RECT  93.271 2.106 93.515 23.769 ;
     RECT  93.515 2.151 99.427 23.769 ;
     RECT  99.427 2.151 99.671 23.922 ;
     RECT  99.671 2.151 113.647 23.769 ;
     RECT  113.647 1.728 113.891 23.769 ;
     RECT  113.891 2.151 115.735 23.769 ;
     RECT  115.735 1.728 115.835 23.769 ;
     RECT  115.835 2.151 122.323 23.769 ;
     RECT  122.323 2.106 122.603 23.769 ;
     RECT  122.603 2.151 126.535 23.769 ;
     RECT  126.535 2.151 126.635 23.922 ;
     RECT  126.635 2.151 140.863 23.769 ;
     RECT  140.863 1.728 140.999 23.769 ;
     RECT  140.999 2.151 142.699 23.769 ;
     RECT  142.699 1.728 142.943 23.769 ;
     RECT  142.943 2.151 146.587 23.769 ;
     RECT  146.587 1.728 146.831 23.769 ;
     RECT  146.831 2.106 146.983 23.769 ;
     RECT  146.983 2.106 148.595 23.814 ;
     RECT  148.595 2.151 149.04 23.814 ;
     RECT  149.04 2.268 149.243 17.064 ;
     RECT  149.243 2.268 149.387 9.036 ;
     RECT  149.04 17.856 149.387 21.294 ;
     RECT  149.387 2.268 149.423 3.672 ;
     RECT  149.387 6.048 149.459 9.036 ;
     RECT  149.459 6.048 149.531 7.956 ;
     RECT  149.243 9.9 149.567 17.064 ;
     RECT  149.04 22.788 149.747 23.814 ;
     RECT  149.423 2.268 149.891 3.366 ;
     RECT  149.387 4.428 149.891 4.788 ;
     RECT  149.531 6.048 149.891 6.606 ;
     RECT  149.531 7.398 149.891 7.956 ;
     RECT  149.459 8.748 149.891 9.036 ;
     RECT  149.567 10.476 149.891 17.064 ;
     RECT  149.387 17.856 149.891 20.376 ;
     RECT  149.891 10.476 149.927 11.934 ;
     RECT  149.387 21.276 149.927 21.294 ;
     RECT  149.747 22.788 149.927 22.806 ;
     RECT  149.927 10.476 150.467 10.494 ;
     RECT  149.927 11.286 150.467 11.934 ;
     RECT  149.891 12.726 150.467 13.59 ;
     RECT  149.891 14.886 150.467 15.624 ;
     RECT  149.891 16.506 150.467 16.524 ;
     RECT  149.891 17.856 150.467 18.414 ;
     RECT  150.467 11.286 150.503 11.304 ;
     RECT  150.467 13.068 150.503 13.086 ;
     RECT  149.747 23.796 150.503 23.814 ;
     RECT  149.891 2.646 151.115 2.664 ;
     RECT  149.891 4.77 151.115 4.788 ;
     RECT  149.891 19.62 151.115 19.638 ;
    LAYER M3 ;
     RECT  16.992 0.012 17.01 0.031 ;
     RECT  40.212 0.012 40.23 0.031 ;
     RECT  16.992 0.031 17.082 0.059 ;
     RECT  40.212 0.031 40.374 0.059 ;
     RECT  42.156 0.012 42.174 0.091 ;
     RECT  61.56 0.012 61.578 0.091 ;
     RECT  3.42 0.012 3.438 1.099 ;
     RECT  148.752 0.012 148.77 1.579 ;
     RECT  2.772 1.099 3.438 1.627 ;
     RECT  4.248 0.811 4.266 1.723 ;
     RECT  15.048 0.012 15.066 1.723 ;
     RECT  53.784 0.012 53.802 1.723 ;
     RECT  82.872 0.012 82.89 1.723 ;
     RECT  86.724 0.012 86.742 1.723 ;
     RECT  90.612 0.012 90.63 1.723 ;
     RECT  104.184 0.012 104.202 1.723 ;
     RECT  109.98 0.012 109.998 1.723 ;
     RECT  113.868 0.012 113.886 1.723 ;
     RECT  115.812 0.012 115.83 1.723 ;
     RECT  119.664 0.012 119.682 1.723 ;
     RECT  123.552 0.012 123.57 1.723 ;
     RECT  125.496 0.012 125.514 1.723 ;
     RECT  135.18 0.012 135.198 1.723 ;
     RECT  140.976 0.012 140.994 1.723 ;
     RECT  142.92 0.012 142.938 1.723 ;
     RECT  146.808 0.012 146.826 1.723 ;
     RECT  149.868 1.195 149.886 2.011 ;
     RECT  2.304 1.627 3.438 2.059 ;
     RECT  4.248 1.723 4.41 2.059 ;
     RECT  2.304 2.059 4.41 2.101 ;
     RECT  5.364 0.012 5.382 2.101 ;
     RECT  25.704 0.091 25.722 2.101 ;
     RECT  26.676 0.012 26.694 2.101 ;
     RECT  41.508 0.091 42.174 2.101 ;
     RECT  43.092 0.091 43.11 2.101 ;
     RECT  45 0.091 45.018 2.101 ;
     RECT  46.044 0.012 46.062 2.101 ;
     RECT  46.944 0.091 46.962 2.101 ;
     RECT  69.3 0.012 69.318 2.101 ;
     RECT  70.272 0.091 70.29 2.101 ;
     RECT  71.244 0.012 71.262 2.101 ;
     RECT  92.556 0.012 92.574 2.101 ;
     RECT  93.492 0.571 93.51 2.101 ;
     RECT  121.608 0.012 121.626 2.101 ;
     RECT  122.58 0.571 122.598 2.101 ;
     RECT  146.592 1.723 146.826 2.101 ;
     RECT  147.78 1.723 147.798 2.101 ;
     RECT  148.752 1.579 149.058 2.101 ;
     RECT  7.272 0.012 7.29 2.143 ;
     RECT  8.208 1.723 8.226 2.143 ;
     RECT  13.104 0.012 13.122 2.143 ;
     RECT  17.964 0.091 17.982 2.143 ;
     RECT  18.9 0.012 18.918 2.143 ;
     RECT  23.832 1.723 23.85 2.143 ;
     RECT  24.732 0.012 24.75 2.143 ;
     RECT  29.556 0.091 29.574 2.143 ;
     RECT  34.416 0.012 34.434 2.143 ;
     RECT  35.388 1.147 35.406 2.143 ;
     RECT  40.356 0.059 40.374 2.143 ;
     RECT  50.832 0.091 50.85 2.143 ;
     RECT  55.728 0.012 55.746 2.143 ;
     RECT  56.736 0.523 56.754 2.143 ;
     RECT  60.84 0.091 61.578 2.143 ;
     RECT  62.496 0.091 62.514 2.143 ;
     RECT  67.356 0.012 67.374 2.143 ;
     RECT  72.252 0.091 72.27 2.143 ;
     RECT  73.152 0.012 73.17 2.143 ;
     RECT  77.796 1.723 77.814 2.143 ;
     RECT  82.656 1.723 82.89 2.143 ;
     RECT  83.808 0.571 83.826 2.143 ;
     RECT  88.668 0.012 88.686 2.143 ;
     RECT  89.532 0.571 89.55 2.143 ;
     RECT  92.556 2.101 93.51 2.143 ;
     RECT  94.5 0.012 94.518 2.143 ;
     RECT  99.18 0.571 99.198 2.143 ;
     RECT  100.296 0.012 100.314 2.143 ;
     RECT  104.184 1.723 104.922 2.143 ;
     RECT  115.74 1.723 115.83 2.143 ;
     RECT  116.568 1.723 116.586 2.143 ;
     RECT  121.608 2.101 122.598 2.143 ;
     RECT  125.496 1.723 126.234 2.143 ;
     RECT  131.292 0.012 131.31 2.143 ;
     RECT  132.264 0.571 132.282 2.143 ;
     RECT  137.124 0.012 137.142 2.143 ;
     RECT  138.024 0.571 138.042 2.143 ;
     RECT  146.592 2.101 147.798 2.143 ;
     RECT  148.572 2.101 149.058 2.143 ;
     RECT  2.304 2.101 5.382 2.155 ;
     RECT  2.268 2.155 5.382 2.191 ;
     RECT  6.336 0.091 6.354 2.191 ;
     RECT  9.216 0.012 9.234 2.191 ;
     RECT  10.152 0.091 10.17 2.191 ;
     RECT  11.16 0.012 11.178 2.191 ;
     RECT  12.132 0.091 12.15 2.191 ;
     RECT  13.104 2.143 13.305 2.191 ;
     RECT  14.04 0.091 14.058 2.191 ;
     RECT  15.948 0.091 15.966 2.191 ;
     RECT  17.064 0.059 17.082 2.191 ;
     RECT  17.964 2.143 18.918 2.191 ;
     RECT  27.612 1.723 27.63 2.191 ;
     RECT  28.62 0.012 28.638 2.191 ;
     RECT  29.415 2.143 29.574 2.191 ;
     RECT  30.528 0.012 30.546 2.191 ;
     RECT  33.444 0.091 33.462 2.191 ;
     RECT  34.416 2.143 35.406 2.191 ;
     RECT  36.36 0.012 36.378 2.191 ;
     RECT  37.26 0.091 37.278 2.191 ;
     RECT  40.215 2.143 40.374 2.191 ;
     RECT  48.96 0.091 48.978 2.191 ;
     RECT  52.776 0.091 52.794 2.191 ;
     RECT  53.712 1.723 53.802 2.191 ;
     RECT  54.72 0.091 54.738 2.191 ;
     RECT  60.84 2.143 62.514 2.191 ;
     RECT  63.468 0.012 63.486 2.191 ;
     RECT  64.512 0.091 64.53 2.191 ;
     RECT  65.412 0.012 65.43 2.191 ;
     RECT  66.42 0.091 66.438 2.191 ;
     RECT  67.215 2.143 67.374 2.191 ;
     RECT  68.256 0.091 68.274 2.191 ;
     RECT  69.3 2.101 71.262 2.191 ;
     RECT  72.252 2.143 73.17 2.191 ;
     RECT  74.088 0.091 74.106 2.191 ;
     RECT  145.62 1.723 145.638 2.191 ;
     RECT  146.592 2.143 149.058 2.191 ;
     RECT  29.376 2.191 29.574 2.227 ;
     RECT  40.104 2.191 40.518 2.227 ;
     RECT  41.508 2.101 43.11 2.227 ;
     RECT  52.776 2.191 52.866 2.227 ;
     RECT  64.512 2.191 65.43 2.227 ;
     RECT  66.42 2.191 68.274 2.227 ;
     RECT  69.156 2.191 71.442 2.227 ;
     RECT  72.252 2.191 74.106 2.227 ;
     RECT  145.62 2.191 149.058 2.251 ;
     RECT  149.832 2.011 149.886 2.251 ;
     RECT  81.684 1.723 81.702 2.255 ;
     RECT  82.656 2.143 83.826 2.255 ;
     RECT  85.572 1.723 85.59 2.255 ;
     RECT  88.668 2.143 89.55 2.255 ;
     RECT  99.18 2.143 100.314 2.255 ;
     RECT  101.052 1.723 101.07 2.255 ;
     RECT  108.036 0.012 108.054 2.255 ;
     RECT  108.9 0.571 108.918 2.255 ;
     RECT  111.924 0.012 111.942 2.255 ;
     RECT  113.652 1.723 113.886 2.255 ;
     RECT  118.584 0.571 118.602 2.255 ;
     RECT  130.104 1.723 130.122 2.255 ;
     RECT  137.124 2.143 138.042 2.255 ;
     RECT  139.788 1.723 139.806 2.255 ;
     RECT  140.868 1.723 140.994 2.255 ;
     RECT  143.676 1.723 143.694 2.255 ;
     RECT  7.272 2.143 8.226 2.263 ;
     RECT  9.18 2.191 9.234 2.263 ;
     RECT  12.096 2.191 14.058 2.263 ;
     RECT  14.94 1.723 15.066 2.263 ;
     RECT  15.948 2.191 17.082 2.263 ;
     RECT  20.844 0.012 20.862 2.263 ;
     RECT  21.816 0.091 21.834 2.263 ;
     RECT  25.668 2.101 25.722 2.263 ;
     RECT  26.46 2.101 26.694 2.263 ;
     RECT  27.612 2.191 28.638 2.263 ;
     RECT  30.528 2.191 30.69 2.263 ;
     RECT  31.428 0.091 31.446 2.263 ;
     RECT  33.444 2.191 33.498 2.263 ;
     RECT  34.236 2.191 35.586 2.263 ;
     RECT  36.36 2.191 37.422 2.263 ;
     RECT  38.304 0.012 38.322 2.263 ;
     RECT  39.276 0.091 39.294 2.263 ;
     RECT  40.104 2.227 43.11 2.263 ;
     RECT  48.924 2.191 48.978 2.263 ;
     RECT  49.932 0.012 49.95 2.263 ;
     RECT  52.74 2.227 52.866 2.263 ;
     RECT  53.712 2.191 54.738 2.263 ;
     RECT  57.672 0.012 57.69 2.263 ;
     RECT  58.644 0.091 58.662 2.263 ;
     RECT  59.616 0.012 59.634 2.263 ;
     RECT  60.84 2.191 62.658 2.263 ;
     RECT  66.42 2.227 74.106 2.263 ;
     RECT  75.096 0.012 75.114 2.263 ;
     RECT  127.44 0.012 127.458 2.263 ;
     RECT  128.376 0.571 128.394 2.263 ;
     RECT  139.032 0.012 139.05 2.263 ;
     RECT  12.096 2.263 17.082 2.291 ;
     RECT  77.04 0.012 77.058 2.291 ;
     RECT  86.724 1.723 87.462 2.291 ;
     RECT  90.612 1.723 91.35 2.291 ;
     RECT  96.408 0.012 96.426 2.291 ;
     RECT  98.352 0.012 98.37 2.291 ;
     RECT  99.576 2.255 100.314 2.291 ;
     RECT  104.184 2.143 105.105 2.291 ;
     RECT  119.664 1.723 120.402 2.291 ;
     RECT  127.44 2.263 128.394 2.291 ;
     RECT  129.348 0.012 129.366 2.291 ;
     RECT  133.236 0.012 133.254 2.291 ;
     RECT  135.18 1.723 135.918 2.291 ;
     RECT  144.864 0.012 144.882 2.291 ;
     RECT  17.928 2.191 18.918 2.299 ;
     RECT  2.268 2.191 6.498 2.327 ;
     RECT  10.152 2.191 11.178 2.335 ;
     RECT  12.096 2.291 15.966 2.335 ;
     RECT  17.928 2.299 18.99 2.335 ;
     RECT  19.836 1.723 19.854 2.335 ;
     RECT  20.844 2.263 21.834 2.335 ;
     RECT  22.788 0.012 22.806 2.335 ;
     RECT  23.832 2.143 24.75 2.335 ;
     RECT  25.668 2.263 28.638 2.335 ;
     RECT  29.376 2.227 29.754 2.335 ;
     RECT  44.1 0.012 44.118 2.335 ;
     RECT  45 2.101 46.962 2.335 ;
     RECT  47.988 0.012 48.006 2.335 ;
     RECT  48.924 2.263 49.95 2.335 ;
     RECT  50.832 2.143 51.105 2.335 ;
     RECT  51.84 0.012 51.858 2.335 ;
     RECT  52.74 2.263 54.738 2.335 ;
     RECT  55.728 2.143 56.754 2.335 ;
     RECT  57.672 2.263 58.662 2.335 ;
     RECT  7.272 2.263 9.234 2.371 ;
     RECT  10.152 2.335 15.966 2.371 ;
     RECT  16.992 2.291 17.082 2.371 ;
     RECT  17.928 2.335 19.854 2.371 ;
     RECT  20.844 2.335 24.75 2.371 ;
     RECT  25.668 2.335 29.754 2.371 ;
     RECT  30.528 2.263 31.446 2.371 ;
     RECT  32.472 0.012 32.49 2.371 ;
     RECT  33.444 2.263 35.586 2.371 ;
     RECT  36.36 2.263 38.322 2.371 ;
     RECT  39.276 2.263 43.362 2.371 ;
     RECT  44.1 2.335 46.962 2.371 ;
     RECT  47.772 2.335 48.006 2.371 ;
     RECT  48.924 2.335 51.858 2.371 ;
     RECT  52.74 2.335 58.662 2.371 ;
     RECT  59.616 2.263 62.658 2.371 ;
     RECT  63.432 2.191 63.486 2.371 ;
     RECT  64.512 2.227 65.574 2.371 ;
     RECT  66.42 2.263 75.114 2.371 ;
     RECT  75.852 1.723 75.87 2.371 ;
     RECT  77.796 2.143 78.105 2.371 ;
     RECT  78.984 0.012 79.002 2.371 ;
     RECT  79.956 0.571 79.974 2.371 ;
     RECT  80.928 0.012 80.946 2.371 ;
     RECT  83.196 2.255 83.826 2.371 ;
     RECT  84.78 0.012 84.798 2.371 ;
     RECT  87.084 2.291 87.462 2.371 ;
     RECT  90.972 2.291 91.35 2.371 ;
     RECT  92.556 2.143 94.518 2.371 ;
     RECT  95.292 1.723 95.31 2.371 ;
     RECT  97.164 1.723 97.182 2.371 ;
     RECT  102.24 0.012 102.258 2.371 ;
     RECT  103.212 1.723 103.23 2.371 ;
     RECT  106.848 1.723 106.866 2.371 ;
     RECT  109.98 1.723 110.682 2.371 ;
     RECT  112.896 0.571 112.914 2.371 ;
     RECT  114.804 0.571 114.822 2.371 ;
     RECT  115.74 2.143 116.586 2.371 ;
     RECT  117.72 0.012 117.738 2.371 ;
     RECT  119.952 2.291 120.402 2.371 ;
     RECT  121.215 2.143 122.598 2.371 ;
     RECT  123.552 1.723 124.29 2.371 ;
     RECT  125.496 2.143 126.705 2.371 ;
     RECT  131.292 2.143 132.282 2.371 ;
     RECT  133.992 1.723 134.01 2.371 ;
     RECT  135.504 2.291 135.918 2.371 ;
     RECT  137.124 2.255 137.697 2.371 ;
     RECT  141.948 0.571 141.966 2.371 ;
     RECT  145.62 2.251 149.886 2.371 ;
     RECT  52.74 2.371 63.486 2.399 ;
     RECT  77.472 2.371 78.105 2.413 ;
     RECT  78.912 2.371 79.002 2.413 ;
     RECT  104.472 2.291 105.105 2.413 ;
     RECT  142.704 1.723 142.938 2.413 ;
     RECT  2.304 2.327 6.498 2.461 ;
     RECT  7.272 2.371 15.966 2.461 ;
     RECT  16.992 2.371 19.854 2.461 ;
     RECT  20.592 2.371 35.586 2.461 ;
     RECT  2.304 2.461 15.966 2.489 ;
     RECT  36.36 2.371 51.894 2.489 ;
     RECT  52.776 2.399 63.486 2.489 ;
     RECT  64.44 2.371 75.114 2.489 ;
     RECT  75.852 2.371 76.014 2.489 ;
     RECT  80.856 2.371 80.946 2.489 ;
     RECT  83.196 2.371 84.798 2.489 ;
     RECT  88.704 2.255 89.097 2.489 ;
     RECT  90.972 2.371 91.53 2.489 ;
     RECT  92.52 2.371 95.526 2.489 ;
     RECT  96.804 2.371 97.398 2.489 ;
     RECT  101.664 2.371 102.33 2.489 ;
     RECT  106.092 0.012 106.11 2.489 ;
     RECT  112.86 2.371 112.914 2.489 ;
     RECT  115.74 2.371 116.73 2.489 ;
     RECT  119.952 2.371 122.598 2.489 ;
     RECT  123.48 2.371 124.47 2.489 ;
     RECT  125.424 2.371 126.897 2.489 ;
     RECT  127.836 2.291 128.394 2.489 ;
     RECT  130.428 2.371 132.354 2.489 ;
     RECT  135.504 2.371 136.062 2.489 ;
     RECT  141.3 2.371 141.966 2.489 ;
     RECT  2.304 2.489 15.75 2.525 ;
     RECT  16.992 2.461 35.586 2.525 ;
     RECT  42.768 2.489 43.902 2.525 ;
     RECT  44.82 2.489 48.762 2.525 ;
     RECT  53.172 2.489 54.522 2.525 ;
     RECT  55.332 2.489 58.482 2.525 ;
     RECT  59.22 2.489 63.486 2.525 ;
     RECT  64.44 2.489 68.094 2.525 ;
     RECT  68.976 2.489 73.926 2.525 ;
     RECT  23.148 2.525 35.586 2.533 ;
     RECT  36.36 2.489 41.742 2.533 ;
     RECT  59.22 2.525 60.93 2.561 ;
     RECT  68.976 2.525 69.714 2.561 ;
     RECT  23.148 2.533 41.742 2.633 ;
     RECT  42.768 2.525 43.398 2.633 ;
     RECT  75.096 2.489 75.114 2.641 ;
     RECT  77.472 2.413 79.002 2.641 ;
     RECT  79.884 2.371 79.974 2.641 ;
     RECT  87.084 2.371 87.642 2.641 ;
     RECT  95.436 2.489 95.526 2.641 ;
     RECT  103.176 2.371 103.23 2.641 ;
     RECT  104.472 2.413 105.297 2.641 ;
     RECT  106.848 2.371 107.37 2.641 ;
     RECT  114.12 2.371 114.822 2.641 ;
     RECT  115.74 2.489 116.097 2.641 ;
     RECT  117.684 2.371 117.738 2.641 ;
     RECT  120.888 2.489 122.598 2.641 ;
     RECT  131.58 2.489 132.354 2.641 ;
     RECT  133.632 2.371 134.19 2.641 ;
     RECT  137.088 2.371 137.697 2.641 ;
     RECT  138.528 2.263 139.05 2.641 ;
     RECT  142.704 2.413 143.19 2.641 ;
     RECT  9.54 2.525 11.214 2.669 ;
     RECT  65.808 2.525 68.094 2.669 ;
     RECT  70.452 2.525 73.926 2.669 ;
     RECT  151.092 2.443 151.11 2.669 ;
     RECT  10.476 2.669 11.214 2.759 ;
     RECT  16.992 2.525 21.078 2.759 ;
     RECT  23.148 2.633 36.882 2.759 ;
     RECT  65.808 2.669 68.058 2.759 ;
     RECT  71.676 2.669 73.674 2.759 ;
     RECT  23.148 2.759 24.498 2.831 ;
     RECT  25.524 2.759 36.882 2.831 ;
     RECT  66.816 2.759 68.058 2.831 ;
     RECT  106.344 2.641 107.37 3.001 ;
     RECT  117.036 2.641 118.026 3.001 ;
     RECT  9.54 2.669 9.666 3.029 ;
     RECT  68.976 2.561 69.39 3.029 ;
     RECT  87.084 2.641 87.894 3.029 ;
     RECT  106.344 3.001 108.09 3.029 ;
     RECT  98.676 2.371 98.694 3.065 ;
     RECT  100.62 2.371 100.638 3.065 ;
     RECT  125.748 2.489 126.897 3.073 ;
     RECT  129.672 2.371 129.69 3.073 ;
     RECT  130.428 2.489 130.842 3.073 ;
     RECT  26.244 2.831 36.882 3.101 ;
     RECT  49.536 2.489 51.894 3.145 ;
     RECT  136.368 2.641 137.697 3.145 ;
     RECT  138.528 2.641 139.302 3.145 ;
     RECT  61.776 2.525 63.486 3.181 ;
     RECT  64.44 2.525 65.07 3.181 ;
     RECT  76.32 2.641 76.338 3.181 ;
     RECT  99.576 2.291 99.897 3.181 ;
     RECT  16.992 2.759 21.042 3.245 ;
     RECT  22.032 2.525 22.05 3.271 ;
     RECT  44.82 2.525 48.33 3.271 ;
     RECT  57.96 2.525 58.482 3.271 ;
     RECT  59.22 2.561 59.238 3.271 ;
     RECT  90.972 2.489 91.098 3.271 ;
     RECT  91.836 2.641 91.854 3.271 ;
     RECT  104.472 2.641 105.354 3.271 ;
     RECT  109.224 2.371 111.726 3.271 ;
     RECT  117.036 3.001 118.17 3.271 ;
     RECT  118.98 2.371 119.142 3.271 ;
     RECT  123.732 2.489 123.75 3.271 ;
     RECT  140.328 2.371 140.346 3.271 ;
     RECT  1.476 0.012 1.494 3.299 ;
     RECT  16.992 3.245 17.118 3.299 ;
     RECT  17.856 3.245 21.042 3.299 ;
     RECT  77.472 2.641 80.226 3.299 ;
     RECT  90.972 3.271 91.854 3.299 ;
     RECT  125.748 3.073 126.99 3.299 ;
     RECT  141.3 2.489 141.426 3.299 ;
     RECT  10.656 2.759 11.214 3.307 ;
     RECT  12.564 2.525 15.39 3.307 ;
     RECT  117.036 3.271 119.142 3.307 ;
     RECT  119.952 2.489 119.97 3.307 ;
     RECT  142.2 2.641 143.19 3.307 ;
     RECT  144.18 2.371 144.198 3.307 ;
     RECT  144.972 2.371 149.886 3.307 ;
     RECT  77.472 3.299 79.254 3.335 ;
     RECT  83.196 2.489 84.114 3.335 ;
     RECT  95.436 2.641 95.778 3.335 ;
     RECT  17.856 3.299 17.874 3.341 ;
     RECT  90.756 3.301 90.774 3.341 ;
     RECT  60.192 2.561 60.93 3.343 ;
     RECT  61.776 3.181 65.07 3.343 ;
     RECT  106.56 3.029 108.09 3.343 ;
     RECT  109.224 3.271 111.834 3.343 ;
     RECT  34.776 3.101 36.882 3.379 ;
     RECT  37.764 2.633 41.742 3.379 ;
     RECT  49.536 3.145 52.11 3.379 ;
     RECT  53.172 2.525 54.486 3.379 ;
     RECT  55.332 2.525 57.15 3.379 ;
     RECT  75.096 2.641 75.51 3.379 ;
     RECT  76.32 3.181 76.482 3.379 ;
     RECT  114.12 2.641 116.097 3.379 ;
     RECT  117.036 3.307 119.97 3.379 ;
     RECT  127.836 2.489 127.854 3.379 ;
     RECT  128.664 2.641 128.682 3.379 ;
     RECT  129.672 3.073 130.842 3.379 ;
     RECT  142.2 3.307 149.886 3.379 ;
     RECT  2.304 2.525 8.514 3.403 ;
     RECT  21.924 3.271 22.05 3.403 ;
     RECT  42.768 2.633 43.218 3.403 ;
     RECT  82.26 2.371 82.278 3.403 ;
     RECT  83.196 3.335 84.078 3.403 ;
     RECT  85.032 2.641 85.05 3.403 ;
     RECT  86.04 2.371 86.058 3.403 ;
     RECT  101.664 2.489 101.682 3.403 ;
     RECT  102.6 2.641 103.446 3.403 ;
     RECT  129.456 3.379 130.842 3.403 ;
     RECT  131.58 2.641 132.57 3.403 ;
     RECT  2.304 3.403 8.622 3.415 ;
     RECT  60.192 3.343 65.07 3.415 ;
     RECT  113.148 2.641 113.166 3.415 ;
     RECT  114.12 3.379 119.97 3.415 ;
     RECT  120.888 2.641 122.958 3.415 ;
     RECT  124.776 2.641 124.794 3.415 ;
     RECT  125.568 3.379 125.586 3.415 ;
     RECT  127.836 3.379 128.682 3.415 ;
     RECT  129.456 3.403 132.57 3.415 ;
     RECT  136.368 3.145 139.302 3.415 ;
     RECT  140.328 3.271 140.454 3.415 ;
     RECT  75.096 3.379 76.482 3.437 ;
     RECT  42.768 3.403 44.01 3.451 ;
     RECT  44.748 3.271 48.33 3.451 ;
     RECT  49.536 3.379 57.15 3.451 ;
     RECT  57.96 3.271 59.238 3.451 ;
     RECT  79.992 3.299 80.226 3.451 ;
     RECT  82.26 3.403 84.078 3.451 ;
     RECT  85.968 3.403 86.058 3.451 ;
     RECT  95.544 3.335 95.778 3.451 ;
     RECT  96.804 2.489 96.822 3.451 ;
     RECT  99.576 3.181 100.602 3.451 ;
     RECT  133.632 2.641 134.658 3.451 ;
     RECT  135.504 2.489 135.522 3.451 ;
     RECT  136.368 3.415 139.518 3.451 ;
     RECT  140.328 3.415 141.102 3.451 ;
     RECT  28.116 3.101 33.93 3.485 ;
     RECT  18.615 3.299 21.042 3.541 ;
     RECT  21.78 3.403 22.05 3.541 ;
     RECT  106.56 3.343 111.834 3.541 ;
     RECT  127.836 3.415 132.57 3.541 ;
     RECT  133.38 3.451 134.658 3.541 ;
     RECT  77.472 3.335 79.074 3.547 ;
     RECT  10.656 3.307 15.39 3.569 ;
     RECT  76.032 3.437 76.482 3.569 ;
     RECT  77.256 3.547 79.074 3.569 ;
     RECT  79.992 3.451 80.406 3.569 ;
     RECT  84.888 3.403 85.05 3.569 ;
     RECT  98.64 3.181 98.658 3.569 ;
     RECT  101.664 3.403 103.446 3.569 ;
     RECT  141.876 3.379 149.886 3.569 ;
     RECT  24.015 2.831 24.498 3.577 ;
     RECT  26.244 3.101 27.27 3.577 ;
     RECT  70.452 2.669 70.65 3.577 ;
     RECT  71.964 2.759 73.674 3.577 ;
     RECT  120.888 3.415 122.994 3.577 ;
     RECT  123.732 3.271 123.93 3.577 ;
     RECT  126.432 3.299 126.99 3.577 ;
     RECT  127.836 3.541 134.658 3.577 ;
     RECT  75.096 3.437 75.222 3.581 ;
     RECT  82.224 3.451 84.078 3.595 ;
     RECT  76.176 3.569 76.482 3.605 ;
     RECT  97.704 2.641 97.722 3.605 ;
     RECT  23.148 2.831 23.202 3.613 ;
     RECT  42.768 3.451 59.238 3.613 ;
     RECT  70.452 3.577 70.902 3.613 ;
     RECT  71.748 3.577 73.674 3.613 ;
     RECT  113.976 3.415 119.97 3.613 ;
     RECT  120.888 3.577 123.93 3.613 ;
     RECT  18.615 3.541 22.05 3.641 ;
     RECT  126.432 3.577 134.658 3.641 ;
     RECT  135.504 3.451 141.102 3.641 ;
     RECT  113.976 3.613 123.93 3.643 ;
     RECT  124.776 3.415 125.586 3.643 ;
     RECT  22.86 3.613 23.202 3.649 ;
     RECT  102.456 3.569 103.446 3.649 ;
     RECT  104.184 3.271 105.354 3.649 ;
     RECT  113.148 3.415 113.238 3.649 ;
     RECT  113.976 3.643 125.586 3.649 ;
     RECT  130.788 3.641 134.658 3.649 ;
     RECT  10.836 3.569 15.39 3.677 ;
     RECT  2.304 3.415 8.802 3.685 ;
     RECT  42.732 3.613 59.238 3.685 ;
     RECT  60.012 3.415 65.07 3.685 ;
     RECT  65.808 2.759 65.826 3.685 ;
     RECT  67.215 2.831 68.058 3.685 ;
     RECT  88.815 2.489 89.097 3.685 ;
     RECT  101.664 3.569 101.682 3.685 ;
     RECT  130.788 3.649 134.766 3.685 ;
     RECT  135.504 3.641 137.697 3.685 ;
     RECT  99.54 3.451 100.602 3.691 ;
     RECT  10.836 3.677 14.85 3.713 ;
     RECT  18.615 3.641 21.798 3.713 ;
     RECT  141.912 3.569 149.886 3.713 ;
     RECT  9.576 3.029 9.666 3.721 ;
     RECT  34.776 3.379 41.742 3.721 ;
     RECT  42.732 3.685 65.07 3.721 ;
     RECT  76.428 3.605 76.482 3.721 ;
     RECT  77.256 3.569 77.274 3.721 ;
     RECT  81.18 2.641 81.198 3.721 ;
     RECT  85.968 3.451 86.13 3.721 ;
     RECT  88.74 3.685 89.097 3.721 ;
     RECT  89.928 2.371 89.946 3.721 ;
     RECT  92.844 2.489 92.862 3.721 ;
     RECT  95.544 3.451 95.922 3.721 ;
     RECT  96.804 3.451 96.93 3.721 ;
     RECT  11.844 3.713 14.85 3.749 ;
     RECT  87.696 3.029 87.894 3.749 ;
     RECT  130.788 3.685 137.697 3.749 ;
     RECT  106.56 3.541 111.978 3.811 ;
     RECT  24.015 3.577 27.27 3.835 ;
     RECT  28.116 3.485 33.858 3.835 ;
     RECT  92.844 3.721 93.006 3.835 ;
     RECT  93.816 2.489 94.497 3.835 ;
     RECT  95.544 3.721 96.93 3.835 ;
     RECT  97.668 3.721 97.686 3.835 ;
     RECT  13.14 3.749 14.85 3.839 ;
     RECT  24.015 3.835 33.858 3.839 ;
     RECT  34.776 3.721 65.07 3.839 ;
     RECT  74.844 3.685 74.862 3.839 ;
     RECT  82.08 3.595 84.078 3.839 ;
     RECT  95.544 3.835 97.686 3.839 ;
     RECT  101.34 3.685 101.682 3.839 ;
     RECT  113.148 3.649 125.586 3.839 ;
     RECT  131.004 3.749 137.697 3.839 ;
     RECT  141.912 3.713 149.058 3.839 ;
     RECT  86.868 3.145 86.886 3.847 ;
     RECT  92.844 3.835 94.497 3.847 ;
     RECT  11.844 3.749 12.402 3.875 ;
     RECT  24.015 3.839 33.822 3.875 ;
     RECT  47.304 3.839 65.07 3.875 ;
     RECT  95.544 3.839 95.562 3.875 ;
     RECT  96.516 3.839 96.642 3.875 ;
     RECT  99.396 3.691 100.602 3.875 ;
     RECT  101.34 3.839 101.502 3.875 ;
     RECT  126.432 3.641 130.05 3.875 ;
     RECT  70.452 3.613 73.674 3.883 ;
     RECT  22.608 3.649 23.202 3.911 ;
     RECT  24.015 3.875 33.714 3.911 ;
     RECT  131.004 3.839 135.306 3.917 ;
     RECT  67.215 3.685 68.13 3.919 ;
     RECT  69.264 3.029 69.39 3.919 ;
     RECT  70.236 3.883 73.674 3.919 ;
     RECT  106.308 3.811 112.302 3.919 ;
     RECT  113.148 3.839 123.678 3.919 ;
     RECT  106.2 3.919 123.678 3.92 ;
     RECT  11.88 3.875 12.402 3.947 ;
     RECT  47.304 3.875 48.402 3.947 ;
     RECT  106.2 3.92 123.642 3.947 ;
     RECT  126.432 3.875 129.798 3.947 ;
     RECT  131.004 3.917 134.766 3.947 ;
     RECT  141.912 3.839 143.097 3.947 ;
     RECT  67.215 3.919 69.39 3.955 ;
     RECT  70.236 3.919 74.07 3.955 ;
     RECT  102.456 3.649 105.354 3.955 ;
     RECT  79.992 3.569 80.082 3.965 ;
     RECT  87.804 3.749 87.894 3.979 ;
     RECT  88.632 3.721 90.666 3.979 ;
     RECT  34.776 3.839 46.422 3.983 ;
     RECT  49.392 3.875 65.07 3.983 ;
     RECT  82.08 3.839 83.934 3.983 ;
     RECT  123.372 3.947 123.642 3.983 ;
     RECT  131.4 3.947 133.686 3.983 ;
     RECT  134.532 3.947 134.766 3.983 ;
     RECT  138.528 3.641 141.102 3.983 ;
     RECT  142.056 3.947 143.097 3.983 ;
     RECT  2.304 3.685 8.838 3.991 ;
     RECT  9.576 3.721 9.882 3.991 ;
     RECT  65.808 3.685 66.222 3.991 ;
     RECT  67.215 3.955 74.07 3.991 ;
     RECT  85.788 3.721 86.13 3.991 ;
     RECT  86.868 3.847 86.922 3.991 ;
     RECT  91.656 3.299 91.854 3.991 ;
     RECT  92.592 3.847 94.497 3.991 ;
     RECT  126.432 3.947 127.566 4.013 ;
     RECT  49.392 3.983 59.454 4.019 ;
     RECT  123.372 3.983 123.606 4.019 ;
     RECT  2.304 3.991 9.882 4.109 ;
     RECT  16.884 3.307 16.902 4.109 ;
     RECT  19.872 3.713 21.798 4.109 ;
     RECT  36.036 3.983 43.398 4.109 ;
     RECT  49.392 4.019 53.586 4.109 ;
     RECT  81 3.721 81.198 4.109 ;
     RECT  82.08 3.983 83.898 4.109 ;
     RECT  85.788 3.991 86.922 4.109 ;
     RECT  91.656 3.991 94.497 4.109 ;
     RECT  97.452 3.839 97.686 4.109 ;
     RECT  124.416 3.839 125.586 4.109 ;
     RECT  128.376 3.947 129.798 4.109 ;
     RECT  136.08 3.839 137.697 4.109 ;
     RECT  143.856 3.839 149.058 4.109 ;
     RECT  16.092 4.075 16.11 4.115 ;
     RECT  92.592 4.109 92.682 4.115 ;
     RECT  124.632 4.109 125.586 4.115 ;
     RECT  65.808 3.991 66.402 4.117 ;
     RECT  67.215 3.991 74.754 4.117 ;
     RECT  22.644 3.911 23.202 4.145 ;
     RECT  49.392 4.109 51.297 4.145 ;
     RECT  81 4.109 81.054 4.145 ;
     RECT  97.452 4.109 97.506 4.145 ;
     RECT  128.484 4.109 129.798 4.145 ;
     RECT  136.224 4.109 137.697 4.145 ;
     RECT  139.536 3.983 141.102 4.145 ;
     RECT  144 4.109 149.058 4.145 ;
     RECT  60.228 3.983 65.07 4.153 ;
     RECT  65.808 4.117 74.754 4.153 ;
     RECT  21.096 4.109 21.798 4.157 ;
     RECT  60.228 4.153 74.754 4.157 ;
     RECT  87.804 3.979 90.666 4.157 ;
     RECT  49.932 4.145 51.297 4.181 ;
     RECT  52.812 4.109 53.586 4.181 ;
     RECT  60.228 4.157 66.006 4.181 ;
     RECT  136.512 4.145 137.697 4.181 ;
     RECT  88.596 4.157 90.666 4.205 ;
     RECT  132.015 3.983 133.686 4.205 ;
     RECT  10.836 3.713 11.07 4.217 ;
     RECT  13.215 3.839 14.85 4.217 ;
     RECT  44.136 3.983 46.422 4.217 ;
     RECT  60.228 4.181 61.074 4.217 ;
     RECT  18.615 3.713 18.954 4.253 ;
     RECT  124.848 4.115 125.586 4.261 ;
     RECT  126.432 4.013 126.897 4.261 ;
     RECT  124.848 4.261 126.897 4.289 ;
     RECT  128.772 4.145 129.798 4.289 ;
     RECT  132.015 4.205 133.254 4.289 ;
     RECT  140.436 4.145 141.102 4.289 ;
     RECT  140.904 4.289 141.102 4.351 ;
     RECT  28.116 3.911 33.21 4.379 ;
     RECT  36.036 4.109 43.29 4.379 ;
     RECT  47.304 3.947 47.898 4.379 ;
     RECT  53.208 4.181 53.586 4.379 ;
     RECT  61.815 4.181 66.006 4.379 ;
     RECT  99.432 3.875 100.602 4.379 ;
     RECT  123.372 4.019 123.426 4.379 ;
     RECT  76.428 3.721 77.274 4.387 ;
     RECT  88.632 4.205 90.666 4.387 ;
     RECT  93.6 4.109 94.497 4.387 ;
     RECT  50.328 4.181 51.297 4.415 ;
     RECT  75.852 4.387 77.274 4.415 ;
     RECT  123.408 4.379 123.426 4.415 ;
     RECT  128.808 4.289 129.798 4.415 ;
     RECT  136.98 4.181 137.697 4.415 ;
     RECT  140.904 4.351 141.21 4.415 ;
     RECT  75.852 4.415 75.87 4.423 ;
     RECT  2.304 4.109 8.91 4.424 ;
     RECT  64.944 4.379 65.106 4.445 ;
     RECT  45.615 4.217 46.422 4.451 ;
     RECT  88.632 4.387 90.702 4.451 ;
     RECT  144.288 4.145 149.058 4.451 ;
     RECT  149.868 3.713 149.886 4.451 ;
     RECT  47.304 4.379 47.61 4.487 ;
     RECT  50.58 4.415 51.297 4.487 ;
     RECT  54.396 4.019 59.454 4.487 ;
     RECT  66.852 4.157 74.754 4.487 ;
     RECT  138.528 3.983 138.582 4.487 ;
     RECT  47.376 4.487 47.61 4.523 ;
     RECT  59.04 4.487 59.454 4.523 ;
     RECT  66.852 4.487 68.598 4.523 ;
     RECT  129.78 4.415 129.798 4.523 ;
     RECT  133.236 4.289 133.254 4.523 ;
     RECT  134.532 3.983 134.55 4.523 ;
     RECT  137.124 4.415 137.697 4.523 ;
     RECT  76.752 4.415 77.274 4.531 ;
     RECT  78.015 3.569 79.074 4.531 ;
     RECT  81 4.145 81.018 4.531 ;
     RECT  102.456 3.955 105.462 4.531 ;
     RECT  106.2 3.947 122.562 4.531 ;
     RECT  24.015 3.911 27.27 4.541 ;
     RECT  2.304 4.424 8.874 4.559 ;
     RECT  24.015 4.541 26.982 4.559 ;
     RECT  36.036 4.379 43.11 4.559 ;
     RECT  47.592 4.523 47.61 4.559 ;
     RECT  53.28 4.379 53.586 4.559 ;
     RECT  61.815 4.379 63.954 4.559 ;
     RECT  124.92 4.289 126.897 4.559 ;
     RECT  36.036 4.559 42.822 4.649 ;
     RECT  53.28 4.559 53.55 4.649 ;
     RECT  54.396 4.487 58.266 4.649 ;
     RECT  61.815 4.559 62.838 4.649 ;
     RECT  76.752 4.531 79.074 4.649 ;
     RECT  102.456 4.531 122.562 4.649 ;
     RECT  55.296 4.649 55.53 4.685 ;
     RECT  102.456 4.649 120.15 4.685 ;
     RECT  141.192 4.415 141.21 4.685 ;
     RECT  36.144 4.649 42.822 4.721 ;
     RECT  75.564 4.423 75.87 4.721 ;
     RECT  121.215 4.649 122.562 4.729 ;
     RECT  102.456 4.685 120.114 4.733 ;
     RECT  28.116 4.379 32.922 4.757 ;
     RECT  69.48 4.487 74.754 4.765 ;
     RECT  75.564 4.721 75.834 4.765 ;
     RECT  24.015 4.559 25.686 4.793 ;
     RECT  151.092 4.507 151.11 4.793 ;
     RECT  77.94 4.649 79.074 4.801 ;
     RECT  101.34 3.875 101.358 4.801 ;
     RECT  28.512 4.757 32.922 4.829 ;
     RECT  121.215 4.729 122.598 4.829 ;
     RECT  142.524 3.983 143.097 4.891 ;
     RECT  145.872 4.451 149.058 4.891 ;
     RECT  36.432 4.721 42.822 4.919 ;
     RECT  66.852 4.523 68.238 4.955 ;
     RECT  102.456 4.733 117.198 4.955 ;
     RECT  34.776 3.983 35.298 4.991 ;
     RECT  59.148 4.523 59.454 4.999 ;
     RECT  60.228 4.217 60.246 4.999 ;
     RECT  21.096 4.157 21.114 5.027 ;
     RECT  69.48 4.765 75.834 5.027 ;
     RECT  102.456 4.955 116.097 5.027 ;
     RECT  24.015 4.793 24.534 5.063 ;
     RECT  102.456 5.027 112.41 5.063 ;
     RECT  121.215 4.829 122.562 5.063 ;
     RECT  69.48 5.027 75.006 5.069 ;
     RECT  2.304 4.559 8.838 5.099 ;
     RECT  53.28 4.649 53.514 5.117 ;
     RECT  118.008 4.733 120.114 5.189 ;
     RECT  113.508 5.027 116.097 5.261 ;
     RECT  65.088 4.445 65.106 5.269 ;
     RECT  65.988 4.379 66.006 5.269 ;
     RECT  66.852 4.955 68.202 5.269 ;
     RECT  118.008 5.189 118.494 5.297 ;
     RECT  138.528 4.487 138.546 5.297 ;
     RECT  63.756 4.559 63.954 5.305 ;
     RECT  145.872 4.891 149.31 5.305 ;
     RECT  28.584 4.829 32.922 5.333 ;
     RECT  37.368 4.919 42.822 5.333 ;
     RECT  142.524 4.891 143.154 5.333 ;
     RECT  61.056 4.217 61.074 5.341 ;
     RECT  61.815 4.649 62.406 5.341 ;
     RECT  145.872 5.305 149.382 5.357 ;
     RECT  37.368 5.333 42.606 5.369 ;
     RECT  114.228 5.261 116.097 5.459 ;
     RECT  121.215 5.063 122.058 5.459 ;
     RECT  29.415 5.333 32.922 5.467 ;
     RECT  79.992 3.965 80.01 5.467 ;
     RECT  80.784 4.531 81.018 5.467 ;
     RECT  124.92 4.559 124.938 5.495 ;
     RECT  101.34 4.801 101.538 5.503 ;
     RECT  29.415 5.467 33.03 5.539 ;
     RECT  114.228 5.459 114.642 5.603 ;
     RECT  118.476 5.297 118.494 5.603 ;
     RECT  25.668 4.793 25.686 5.639 ;
     RECT  29.415 5.539 33.138 5.639 ;
     RECT  76.752 4.649 77.166 5.701 ;
     RECT  77.94 4.801 79.146 5.701 ;
     RECT  36.432 4.919 36.558 5.737 ;
     RECT  37.368 5.369 42.102 5.737 ;
     RECT  75.78 5.027 75.834 5.737 ;
     RECT  76.752 5.701 79.146 5.737 ;
     RECT  79.992 5.467 81.018 5.737 ;
     RECT  75.78 5.737 81.018 5.789 ;
     RECT  2.412 5.099 8.838 5.801 ;
     RECT  36.432 5.737 42.102 5.801 ;
     RECT  74.556 5.069 75.006 5.809 ;
     RECT  75.78 5.789 75.798 5.809 ;
     RECT  59.148 4.999 60.246 5.845 ;
     RECT  61.056 5.341 62.406 5.845 ;
     RECT  144.288 4.451 144.846 5.971 ;
     RECT  69.48 5.069 73.71 5.995 ;
     RECT  74.556 5.809 75.798 5.995 ;
     RECT  69.48 5.995 75.798 5.999 ;
     RECT  34.815 4.991 35.298 6.043 ;
     RECT  101.124 5.503 101.538 6.043 ;
     RECT  102.456 5.063 112.266 6.043 ;
     RECT  139.536 4.145 139.554 6.071 ;
     RECT  29.415 5.639 32.166 6.107 ;
     RECT  4.284 5.801 8.838 6.115 ;
     RECT  9.864 4.109 9.882 6.115 ;
     RECT  34.776 6.043 35.298 6.115 ;
     RECT  145.872 5.357 148.806 6.139 ;
     RECT  149.868 5.707 149.886 6.139 ;
     RECT  32.904 5.639 33.066 6.179 ;
     RECT  65.988 5.269 68.202 6.241 ;
     RECT  4.284 6.115 9.882 6.269 ;
     RECT  34.056 6.115 35.298 6.269 ;
     RECT  36.432 5.801 41.022 6.269 ;
     RECT  101.124 6.043 112.266 6.269 ;
     RECT  119.34 5.189 120.114 6.305 ;
     RECT  2.412 5.801 3.474 6.331 ;
     RECT  32.904 6.179 32.922 6.413 ;
     RECT  142.815 5.333 143.154 6.421 ;
     RECT  69.48 5.999 75.654 6.449 ;
     RECT  101.196 6.269 112.266 6.547 ;
     RECT  2.34 6.331 3.474 6.575 ;
     RECT  142.56 6.421 143.154 6.575 ;
     RECT  42.084 5.801 42.102 6.583 ;
     RECT  101.196 6.547 112.41 6.583 ;
     RECT  144.288 5.971 145.062 6.611 ;
     RECT  145.872 6.139 149.886 6.611 ;
     RECT  65.988 6.241 68.526 6.619 ;
     RECT  69.48 6.449 75.474 6.619 ;
     RECT  76.716 5.789 79.074 6.619 ;
     RECT  125.892 4.559 126.897 6.647 ;
     RECT  42.084 6.583 42.678 6.683 ;
     RECT  2.415 6.575 3.474 6.691 ;
     RECT  4.284 6.269 8.838 6.691 ;
     RECT  86.904 4.109 86.922 6.691 ;
     RECT  87.804 4.157 87.822 6.691 ;
     RECT  36.432 6.269 36.45 6.719 ;
     RECT  115.38 5.459 116.097 6.719 ;
     RECT  65.988 6.619 75.474 6.809 ;
     RECT  24.015 5.063 24.426 6.817 ;
     RECT  37.332 6.269 41.022 6.845 ;
     RECT  37.332 6.845 37.602 7.079 ;
     RECT  34.815 6.269 35.298 7.087 ;
     RECT  56.304 4.649 58.266 7.123 ;
     RECT  59.148 5.845 62.406 7.123 ;
     RECT  101.196 6.583 112.446 7.195 ;
     RECT  145.872 6.611 149.526 7.223 ;
     RECT  100.944 7.195 113.058 7.229 ;
     RECT  75.096 6.809 75.474 7.231 ;
     RECT  76.572 6.619 79.074 7.231 ;
     RECT  99.432 4.379 99.897 7.321 ;
     RECT  2.415 6.691 8.838 7.339 ;
     RECT  75.096 7.231 79.074 7.349 ;
     RECT  114.228 5.603 114.246 7.349 ;
     RECT  111.636 7.229 113.058 7.385 ;
     RECT  92.592 4.115 92.61 7.429 ;
     RECT  92.592 7.429 92.682 7.457 ;
     RECT  42.084 6.683 42.102 7.501 ;
     RECT  113.796 7.357 114.03 7.501 ;
     RECT  75.096 7.349 75.726 7.619 ;
     RECT  75.096 7.619 75.618 7.655 ;
     RECT  145.872 7.223 148.806 7.655 ;
     RECT  95.76 7.591 95.778 7.661 ;
     RECT  37.584 7.079 37.602 7.663 ;
     RECT  38.34 6.845 41.022 7.663 ;
     RECT  119.34 6.305 120.042 7.691 ;
     RECT  55.296 4.685 55.314 7.699 ;
     RECT  42.084 7.501 42.75 7.727 ;
     RECT  42.084 7.727 42.678 7.763 ;
     RECT  75.42 7.655 75.618 7.799 ;
     RECT  111.636 7.385 112.698 7.805 ;
     RECT  65.988 6.809 74.178 7.861 ;
     RECT  93.6 4.387 94.59 7.861 ;
     RECT  2.34 7.339 8.838 7.867 ;
     RECT  42.084 7.763 42.102 7.889 ;
     RECT  111.816 7.805 112.698 7.889 ;
     RECT  76.5 7.349 79.074 7.961 ;
     RECT  2.304 7.867 8.838 8.033 ;
     RECT  117.18 4.955 117.198 8.069 ;
     RECT  76.5 7.961 77.13 8.159 ;
     RECT  2.304 8.033 2.79 8.195 ;
     RECT  37.584 7.663 41.022 8.195 ;
     RECT  149.868 7.384 149.886 8.203 ;
     RECT  76.536 8.159 77.13 8.231 ;
     RECT  23.184 4.145 23.202 8.239 ;
     RECT  54.396 4.649 54.414 8.239 ;
     RECT  55.296 7.699 55.494 8.239 ;
     RECT  24.015 6.817 24.498 8.275 ;
     RECT  53.496 5.117 53.514 8.275 ;
     RECT  54.396 8.239 55.494 8.275 ;
     RECT  100.944 7.229 110.898 8.275 ;
     RECT  145.872 7.655 148.497 8.275 ;
     RECT  3.564 8.033 8.838 8.303 ;
     RECT  40.215 8.195 41.022 8.303 ;
     RECT  149.436 8.203 149.886 8.303 ;
     RECT  23.184 8.239 23.238 8.311 ;
     RECT  24.015 8.275 24.534 8.311 ;
     RECT  53.496 8.275 55.494 8.311 ;
     RECT  90.684 4.451 90.702 8.311 ;
     RECT  93.6 7.861 94.626 8.311 ;
     RECT  96.516 3.875 96.606 8.311 ;
     RECT  97.452 4.145 97.47 8.311 ;
     RECT  37.584 8.195 39.366 8.339 ;
     RECT  75.42 7.799 75.546 8.339 ;
     RECT  113.436 7.501 114.03 8.339 ;
     RECT  91.728 4.109 91.746 8.401 ;
     RECT  92.664 7.457 92.682 8.401 ;
     RECT  65.988 7.861 74.502 8.429 ;
     RECT  91.728 8.401 92.682 8.491 ;
     RECT  93.6 8.311 95.058 8.491 ;
     RECT  145.836 8.275 148.497 8.501 ;
     RECT  93.6 8.491 95.67 8.537 ;
     RECT  86.904 6.691 87.822 8.545 ;
     RECT  86.868 8.545 87.822 8.573 ;
     RECT  88.632 4.451 89.73 8.581 ;
     RECT  23.184 8.311 24.534 8.671 ;
     RECT  25.272 7.735 25.29 8.671 ;
     RECT  34.776 7.087 35.298 8.671 ;
     RECT  45.615 4.451 45.897 8.671 ;
     RECT  79.992 5.789 81.018 8.671 ;
     RECT  90.648 8.311 90.702 8.671 ;
     RECT  91.728 8.491 92.862 8.671 ;
     RECT  121.215 5.459 121.497 8.671 ;
     RECT  132.015 4.289 132.297 8.671 ;
     RECT  12.06 3.947 12.402 8.683 ;
     RECT  13.215 4.217 14.562 8.683 ;
     RECT  86.868 8.573 86.886 8.683 ;
     RECT  90.648 8.671 92.862 8.699 ;
     RECT  34.704 8.671 35.298 8.717 ;
     RECT  45.504 8.671 45.897 8.717 ;
     RECT  77.904 7.961 79.074 8.717 ;
     RECT  121.104 8.671 121.497 8.717 ;
     RECT  131.904 8.671 132.297 8.717 ;
     RECT  12.06 8.683 14.562 8.735 ;
     RECT  79.992 8.671 81.162 8.765 ;
     RECT  88.632 8.581 89.838 8.771 ;
     RECT  111.816 7.889 112.626 8.779 ;
     RECT  144.828 6.611 145.062 8.779 ;
     RECT  111.708 8.779 112.626 8.807 ;
     RECT  86.652 8.683 86.886 8.813 ;
     RECT  79.992 8.765 81.018 8.815 ;
     RECT  79.812 8.815 81.018 8.843 ;
     RECT  90.648 8.699 91.746 8.851 ;
     RECT  144.792 8.779 145.062 8.851 ;
     RECT  80.64 8.843 81.018 8.879 ;
     RECT  88.776 8.771 89.838 8.879 ;
     RECT  144.468 8.851 145.062 8.909 ;
     RECT  23.184 8.671 25.29 8.977 ;
     RECT  100.8 8.275 110.898 8.977 ;
     RECT  81.972 4.261 81.99 9.013 ;
     RECT  83.052 4.109 83.898 9.013 ;
     RECT  84.852 3.847 84.87 9.041 ;
     RECT  89.82 8.879 89.838 9.041 ;
     RECT  121.215 8.717 121.497 9.049 ;
     RECT  149.868 8.303 149.886 9.053 ;
     RECT  144.792 8.909 145.062 9.077 ;
     RECT  90.612 8.851 91.746 9.085 ;
     RECT  81.972 9.013 83.898 9.113 ;
     RECT  111.708 8.807 112.338 9.113 ;
     RECT  92.664 8.699 92.862 9.115 ;
     RECT  93.6 8.537 94.662 9.115 ;
     RECT  3.996 8.303 8.838 9.121 ;
     RECT  96.516 8.311 97.47 9.211 ;
     RECT  99.288 7.321 99.897 9.211 ;
     RECT  100.656 8.977 110.898 9.211 ;
     RECT  96.516 9.211 97.686 9.283 ;
     RECT  98.46 3.685 98.478 9.283 ;
     RECT  137.415 4.523 137.697 9.283 ;
     RECT  23.184 8.977 25.686 9.391 ;
     RECT  26.64 4.559 26.982 9.391 ;
     RECT  99.252 9.211 110.898 9.391 ;
     RECT  37.584 8.339 38.502 9.419 ;
     RECT  96.516 9.283 98.478 9.481 ;
     RECT  99.252 9.391 111.006 9.481 ;
     RECT  96.516 9.481 111.006 9.545 ;
     RECT  3.924 9.121 8.838 9.589 ;
     RECT  128.808 4.415 128.826 9.589 ;
     RECT  149.22 9.451 149.238 9.653 ;
     RECT  3.924 9.589 9.126 9.661 ;
     RECT  92.664 9.115 94.662 9.661 ;
     RECT  92.628 9.661 94.662 9.689 ;
     RECT  95.508 8.537 95.526 9.751 ;
     RECT  96.516 9.545 110.898 9.751 ;
     RECT  92.628 9.689 93.222 9.779 ;
     RECT  94.176 9.689 94.662 9.787 ;
     RECT  3.6 9.661 9.126 9.815 ;
     RECT  92.628 9.779 92.934 9.815 ;
     RECT  95.508 9.751 110.898 9.851 ;
     RECT  89.892 9.085 91.746 9.859 ;
     RECT  88.776 8.879 89.097 9.883 ;
     RECT  89.82 9.859 91.746 9.883 ;
     RECT  11.052 4.217 11.07 9.895 ;
     RECT  12.06 8.735 12.402 9.895 ;
     RECT  149.364 9.835 149.562 9.923 ;
     RECT  9.864 6.269 9.882 9.931 ;
     RECT  28.584 5.333 28.638 9.931 ;
     RECT  29.415 6.107 31.446 9.931 ;
     RECT  9.864 9.931 10.242 9.959 ;
     RECT  88.776 9.883 91.746 10.013 ;
     RECT  89.82 10.013 91.746 10.049 ;
     RECT  23.184 9.391 26.982 10.057 ;
     RECT  82.98 9.113 83.898 10.057 ;
     RECT  10.224 9.959 10.242 10.085 ;
     RECT  82.872 10.057 83.898 10.12 ;
     RECT  11.052 9.895 12.402 10.121 ;
     RECT  88.776 10.013 89.097 10.121 ;
     RECT  95.508 9.851 110.79 10.121 ;
     RECT  111.816 9.113 112.338 10.121 ;
     RECT  95.508 10.121 97.686 10.157 ;
     RECT  22.212 8.545 22.23 10.165 ;
     RECT  23.184 10.057 27.594 10.165 ;
     RECT  94.176 9.787 94.734 10.315 ;
     RECT  92.628 9.815 92.682 10.327 ;
     RECT  94.176 10.315 94.77 10.355 ;
     RECT  2.304 8.195 2.697 10.363 ;
     RECT  80.784 8.879 81.018 10.399 ;
     RECT  81.972 9.113 81.99 10.399 ;
     RECT  82.8 10.12 83.898 10.399 ;
     RECT  84.636 9.931 84.654 10.399 ;
     RECT  115.815 6.719 116.097 10.399 ;
     RECT  94.176 10.355 94.698 10.427 ;
     RECT  149.364 9.923 149.382 10.427 ;
     RECT  145.872 8.501 148.497 10.435 ;
     RECT  12.06 10.121 12.402 10.471 ;
     RECT  13.215 8.735 14.562 10.471 ;
     RECT  76.752 8.231 77.13 10.471 ;
     RECT  86.868 8.813 86.886 10.471 ;
     RECT  90.648 10.049 91.746 10.471 ;
     RECT  92.592 10.327 92.682 10.471 ;
     RECT  12.06 10.471 14.562 10.499 ;
     RECT  2.304 10.363 3.006 10.561 ;
     RECT  3.816 9.815 9.126 10.561 ;
     RECT  10.728 10.471 10.818 10.589 ;
     RECT  12.528 10.499 14.562 10.625 ;
     RECT  111.816 10.121 112.086 10.625 ;
     RECT  10.8 10.589 10.818 10.661 ;
     RECT  80.784 10.399 81.162 10.661 ;
     RECT  81.972 10.399 84.654 10.661 ;
     RECT  90.648 10.471 92.682 10.661 ;
     RECT  142.815 6.575 143.154 10.669 ;
     RECT  111.816 10.625 111.906 10.697 ;
     RECT  111.816 10.697 111.834 10.705 ;
     RECT  144.828 9.077 145.062 10.705 ;
     RECT  145.872 10.435 148.806 10.705 ;
     RECT  86.652 10.471 86.886 10.733 ;
     RECT  94.176 10.427 94.626 10.733 ;
     RECT  28.584 9.931 31.446 10.741 ;
     RECT  150.444 10.471 150.462 10.741 ;
     RECT  34.815 8.717 35.298 10.769 ;
     RECT  142.524 10.669 143.154 10.769 ;
     RECT  98.46 10.121 110.79 10.831 ;
     RECT  111.636 10.705 111.834 10.859 ;
     RECT  144.828 10.705 148.806 10.877 ;
     RECT  111.708 10.859 111.834 10.931 ;
     RECT  90.648 10.661 91.746 10.967 ;
     RECT  18.615 4.253 18.897 10.975 ;
     RECT  128.52 9.589 128.826 10.975 ;
     RECT  137.415 9.283 138.33 11.011 ;
     RECT  142.815 10.769 143.154 11.011 ;
     RECT  92.592 10.661 92.682 11.039 ;
     RECT  76.68 10.471 77.13 11.101 ;
     RECT  149.904 10.741 150.462 11.117 ;
     RECT  18.615 10.975 19.35 11.129 ;
     RECT  39.348 8.339 39.366 11.129 ;
     RECT  98.46 10.831 110.826 11.129 ;
     RECT  142.815 11.011 143.802 11.129 ;
     RECT  2.304 10.561 9.126 11.137 ;
     RECT  9.9 10.903 9.918 11.137 ;
     RECT  37.8 9.419 38.502 11.137 ;
     RECT  98.46 11.129 101.682 11.201 ;
     RECT  40.215 8.303 40.497 11.209 ;
     RECT  2.304 11.137 9.918 11.275 ;
     RECT  65.988 8.429 74.394 11.281 ;
     RECT  75.42 8.339 75.438 11.281 ;
     RECT  80.784 10.661 80.838 11.281 ;
     RECT  85.788 4.109 85.806 11.281 ;
     RECT  132.015 8.717 132.297 11.281 ;
     RECT  144.828 10.877 145.062 11.281 ;
     RECT  37.8 11.137 38.934 11.309 ;
     RECT  39.888 11.209 40.497 11.309 ;
     RECT  76.464 11.101 77.13 11.309 ;
     RECT  81.972 10.661 82.062 11.309 ;
     RECT  86.868 10.733 86.886 11.309 ;
     RECT  2.268 11.275 9.918 11.315 ;
     RECT  142.815 11.129 143.658 11.315 ;
     RECT  65.988 11.281 75.438 11.399 ;
     RECT  80.712 11.281 80.838 11.399 ;
     RECT  85.788 11.281 85.95 11.399 ;
     RECT  144.792 11.281 145.062 11.435 ;
     RECT  79.812 8.843 79.83 11.443 ;
     RECT  118.152 10.165 118.17 11.443 ;
     RECT  102.456 11.129 110.826 11.543 ;
     RECT  56.304 7.123 62.406 11.549 ;
     RECT  150.48 11.281 150.498 11.549 ;
     RECT  94.176 10.733 94.497 11.551 ;
     RECT  79.812 11.443 79.902 11.669 ;
     RECT  93.96 11.551 94.698 11.669 ;
     RECT  83.052 10.661 83.697 11.704 ;
     RECT  10.8 11.551 10.818 11.705 ;
     RECT  37.8 11.309 38.502 11.713 ;
     RECT  13.215 10.625 14.562 11.777 ;
     RECT  2.304 11.315 9.918 11.785 ;
     RECT  93.96 11.669 94.497 11.821 ;
     RECT  23.184 10.165 27.702 11.939 ;
     RECT  93.888 11.821 94.497 11.939 ;
     RECT  102.456 11.543 110.697 11.939 ;
     RECT  150.444 11.899 150.462 11.939 ;
     RECT  23.184 11.939 25.866 11.981 ;
     RECT  63.36 5.305 63.954 11.983 ;
     RECT  64.728 5.269 65.106 11.983 ;
     RECT  120.024 7.691 120.042 11.983 ;
     RECT  121.215 9.049 121.842 11.983 ;
     RECT  144.828 11.435 145.062 11.995 ;
     RECT  145.872 10.877 148.806 11.995 ;
     RECT  51.015 4.487 51.297 12.019 ;
     RECT  18.615 11.129 18.897 12.055 ;
     RECT  26.64 11.939 27.702 12.055 ;
     RECT  63.36 11.983 65.106 12.055 ;
     RECT  16.236 4.261 16.254 12.091 ;
     RECT  22.212 10.165 22.302 12.181 ;
     RECT  23.184 11.981 25.686 12.181 ;
     RECT  85.788 11.399 85.878 12.181 ;
     RECT  65.988 11.399 74.394 12.209 ;
     RECT  144.828 11.995 148.806 12.209 ;
     RECT  22.212 12.181 25.686 12.217 ;
     RECT  60.048 11.549 62.406 12.217 ;
     RECT  63.288 12.055 65.106 12.217 ;
     RECT  144.828 12.209 148.626 12.245 ;
     RECT  37.224 11.713 38.502 12.283 ;
     RECT  115.2 10.399 116.097 12.289 ;
     RECT  85.788 12.181 86.022 12.317 ;
     RECT  83.016 11.704 83.697 12.325 ;
     RECT  98.46 11.201 101.61 12.331 ;
     RECT  102.456 11.939 104.202 12.331 ;
     RECT  82.656 12.325 83.697 12.353 ;
     RECT  37.224 12.283 38.898 12.379 ;
     RECT  78.015 8.717 79.074 12.389 ;
     RECT  37.008 12.379 38.898 12.413 ;
     RECT  34.815 10.769 35.19 12.427 ;
     RECT  37.008 12.413 38.79 12.451 ;
     RECT  40.215 11.309 40.497 12.451 ;
     RECT  41.22 12.283 41.346 12.451 ;
     RECT  50.796 12.019 51.297 12.451 ;
     RECT  66.672 12.209 74.394 12.451 ;
     RECT  52.992 8.311 55.494 12.475 ;
     RECT  98.46 12.331 104.202 12.479 ;
     RECT  149.868 12.331 149.886 12.479 ;
     RECT  36.756 12.451 38.79 12.523 ;
     RECT  66.672 12.451 74.682 12.551 ;
     RECT  78.015 12.389 78.822 12.551 ;
     RECT  82.656 12.353 82.674 12.551 ;
     RECT  95.508 10.157 97.47 12.551 ;
     RECT  102.456 12.479 104.202 12.551 ;
     RECT  36.684 12.523 38.79 12.557 ;
     RECT  20.988 12.523 21.006 12.559 ;
     RECT  98.46 12.479 101.61 12.559 ;
     RECT  98.316 12.559 101.61 12.587 ;
     RECT  0.54 11.371 0.558 12.605 ;
     RECT  22.068 12.217 25.686 12.631 ;
     RECT  52.848 12.475 55.494 12.631 ;
     RECT  56.304 11.549 59.238 12.631 ;
     RECT  98.316 12.587 98.334 12.631 ;
     RECT  20.988 12.559 21.042 12.659 ;
     RECT  52.848 12.631 59.238 12.715 ;
     RECT  40.215 12.451 41.346 12.721 ;
     RECT  60.048 12.217 65.106 12.721 ;
     RECT  65.844 12.361 65.934 12.721 ;
     RECT  60.048 12.721 65.934 12.749 ;
     RECT  150.444 12.712 150.462 12.749 ;
     RECT  52.776 12.715 59.238 12.757 ;
     RECT  60.048 12.749 63.234 12.757 ;
     RECT  52.776 12.757 63.234 12.785 ;
     RECT  89.892 10.049 89.91 12.793 ;
     RECT  34.704 12.427 35.19 12.829 ;
     RECT  40.215 12.721 41.454 12.845 ;
     RECT  15.516 12.091 16.254 12.857 ;
     RECT  134.676 12.361 134.694 12.865 ;
     RECT  21.96 12.631 25.686 12.901 ;
     RECT  52.776 12.785 63.126 12.929 ;
     RECT  64.008 12.749 65.934 12.929 ;
     RECT  102.636 12.551 104.202 12.991 ;
     RECT  50.724 12.451 51.297 13.019 ;
     RECT  52.776 12.929 53.946 13.019 ;
     RECT  97.956 12.631 98.334 13.019 ;
     RECT  105.015 11.939 110.697 13.019 ;
     RECT  144.828 12.245 145.062 13.051 ;
     RECT  54.72 12.929 63.126 13.055 ;
     RECT  66.672 12.551 74.394 13.055 ;
     RECT  19.944 12.991 19.962 13.063 ;
     RECT  102.636 12.991 104.274 13.063 ;
     RECT  105.015 13.019 106.398 13.063 ;
     RECT  145.872 12.245 148.626 13.063 ;
     RECT  69.084 13.055 74.394 13.085 ;
     RECT  52.776 13.019 53.838 13.091 ;
     RECT  65.232 12.929 65.934 13.091 ;
     RECT  98.316 13.019 98.334 13.091 ;
     RECT  144.252 13.051 145.062 13.091 ;
     RECT  52.776 13.091 53.73 13.135 ;
     RECT  66.672 13.055 68.238 13.147 ;
     RECT  26.64 12.055 27.738 13.171 ;
     RECT  28.512 10.741 31.446 13.171 ;
     RECT  144.828 13.091 145.062 13.171 ;
     RECT  145.872 13.063 148.806 13.171 ;
     RECT  41.436 12.845 41.454 13.181 ;
     RECT  150.48 13.063 150.498 13.181 ;
     RECT  14.544 11.777 14.562 13.199 ;
     RECT  76.464 11.309 76.482 13.243 ;
     RECT  21.96 12.901 25.794 13.261 ;
     RECT  26.64 13.171 31.59 13.261 ;
     RECT  44.136 4.217 44.154 13.261 ;
     RECT  48.096 13.147 48.402 13.261 ;
     RECT  60.048 13.055 60.426 13.277 ;
     RECT  48.06 13.261 48.402 13.289 ;
     RECT  76.356 13.243 76.482 13.289 ;
     RECT  36.684 12.557 38.502 13.297 ;
     RECT  102.636 13.063 106.398 13.325 ;
     RECT  144.828 13.171 148.806 13.325 ;
     RECT  75.42 11.399 75.438 13.333 ;
     RECT  2.304 11.785 10.422 13.361 ;
     RECT  21.96 13.261 31.59 13.361 ;
     RECT  75.42 13.333 75.582 13.369 ;
     RECT  60.048 13.277 60.39 13.397 ;
     RECT  48.06 13.289 48.114 13.405 ;
     RECT  87.624 8.573 87.822 13.405 ;
     RECT  88.815 10.121 89.097 13.405 ;
     RECT  45.615 8.717 45.897 13.432 ;
     RECT  36.288 13.297 38.538 13.441 ;
     RECT  21.96 13.361 27.738 13.469 ;
     RECT  36.288 13.441 38.574 13.469 ;
     RECT  45.504 13.432 45.897 13.469 ;
     RECT  54.72 13.055 58.95 13.469 ;
     RECT  0.324 13.339 0.342 13.483 ;
     RECT  54.72 13.469 58.878 13.559 ;
     RECT  102.636 13.325 105.297 13.559 ;
     RECT  27.54 13.469 27.738 13.565 ;
     RECT  66.132 13.147 68.238 13.565 ;
     RECT  34.2 12.829 35.478 13.567 ;
     RECT  0.108 13.483 0.342 13.613 ;
     RECT  34.056 13.567 35.478 13.613 ;
     RECT  47.556 13.405 48.114 13.613 ;
     RECT  150.444 13.567 150.462 13.613 ;
     RECT  70.704 13.085 74.394 13.631 ;
     RECT  94.215 11.939 94.497 13.639 ;
     RECT  95.508 12.551 97.038 13.639 ;
     RECT  54.72 13.559 58.806 13.667 ;
     RECT  70.776 13.631 74.394 13.667 ;
     RECT  54.72 13.667 57.222 13.675 ;
     RECT  36.36 13.469 38.574 13.703 ;
     RECT  52.416 13.135 53.73 13.703 ;
     RECT  54.576 13.675 57.222 13.703 ;
     RECT  90.684 10.967 91.746 13.711 ;
     RECT  92.628 11.039 92.646 13.711 ;
     RECT  128.52 10.975 129.402 13.739 ;
     RECT  145.872 13.325 148.806 13.829 ;
     RECT  28.476 13.361 31.59 13.865 ;
     RECT  37.224 13.703 38.574 13.865 ;
     RECT  43.884 13.261 44.154 13.865 ;
     RECT  61.164 13.055 63.126 13.865 ;
     RECT  17.532 13.135 17.55 13.909 ;
     RECT  21.96 13.469 26.802 13.937 ;
     RECT  38.556 13.865 38.574 13.937 ;
     RECT  43.884 13.865 43.902 13.981 ;
     RECT  21.96 13.937 26.766 14.207 ;
     RECT  37.224 13.865 37.818 14.243 ;
     RECT  144.072 14.251 144.09 14.369 ;
     RECT  0.54 14.179 0.558 14.429 ;
     RECT  149.868 13.963 149.886 14.429 ;
     RECT  144.828 13.325 145.098 14.449 ;
     RECT  145.872 13.829 148.497 14.449 ;
     RECT  75.42 13.369 75.654 14.513 ;
     RECT  2.304 13.361 8.73 14.521 ;
     RECT  106.164 13.325 106.398 14.549 ;
     RECT  113.508 8.339 114.03 14.611 ;
     RECT  87.624 13.405 89.097 14.639 ;
     RECT  39.348 14.215 39.366 14.719 ;
     RECT  28.692 13.865 31.59 14.791 ;
     RECT  28.62 14.791 31.59 14.819 ;
     RECT  102.636 13.559 104.058 14.819 ;
     RECT  107.172 13.019 110.697 14.819 ;
     RECT  99.072 12.587 101.61 14.881 ;
     RECT  144.828 14.449 148.497 14.881 ;
     RECT  98.748 14.881 101.61 14.989 ;
     RECT  98.604 14.989 101.61 15.025 ;
     RECT  98.244 15.025 101.61 15.061 ;
     RECT  2.304 14.521 9.054 15.151 ;
     RECT  2.268 15.151 9.054 15.179 ;
     RECT  2.268 15.179 8.91 15.197 ;
     RECT  2.304 15.197 8.91 15.251 ;
     RECT  85.788 12.317 85.806 15.251 ;
     RECT  94.215 13.639 97.038 15.259 ;
     RECT  97.848 15.061 101.61 15.259 ;
     RECT  82.656 15.223 82.674 15.323 ;
     RECT  94.215 15.259 101.61 15.323 ;
     RECT  102.636 14.819 103.986 15.629 ;
     RECT  150.444 14.779 150.462 15.677 ;
     RECT  90.684 13.711 92.646 15.719 ;
     RECT  94.215 15.323 101.214 15.719 ;
     RECT  89.856 12.793 89.91 15.763 ;
     RECT  128.52 13.739 128.538 15.799 ;
     RECT  91.296 15.719 92.646 15.827 ;
     RECT  89.82 15.763 89.91 15.835 ;
     RECT  87.804 14.639 89.097 15.899 ;
     RECT  91.404 15.827 92.646 15.899 ;
     RECT  144.828 14.881 148.698 15.961 ;
     RECT  144.288 15.961 148.698 16.013 ;
     RECT  149.868 16.024 149.886 16.061 ;
     RECT  84.636 10.661 84.654 16.231 ;
     RECT  85.5 16.027 85.518 16.231 ;
     RECT  84.636 16.231 85.518 16.259 ;
     RECT  91.404 15.899 91.674 16.259 ;
     RECT  92.52 15.899 92.646 16.259 ;
     RECT  85.032 16.259 85.05 16.301 ;
     RECT  97.02 15.719 101.214 16.301 ;
     RECT  108.648 14.819 110.697 16.375 ;
     RECT  144.828 16.013 148.698 16.375 ;
     RECT  144.828 16.375 148.734 16.411 ;
     RECT  2.304 15.251 8.73 16.439 ;
     RECT  150.444 16.459 150.462 16.529 ;
     RECT  108.648 16.375 110.862 16.637 ;
     RECT  2.34 16.439 8.73 16.681 ;
     RECT  9.792 13.361 10.422 16.681 ;
     RECT  76.464 13.289 76.482 16.709 ;
     RECT  51.015 13.019 51.297 16.807 ;
     RECT  115.2 12.289 116.298 16.807 ;
     RECT  149.868 16.843 149.886 17.069 ;
     RECT  2.34 16.681 10.422 17.105 ;
     RECT  15.516 12.857 15.534 17.185 ;
     RECT  13.215 11.777 13.497 17.221 ;
     RECT  2.34 17.105 8.658 17.227 ;
     RECT  144.828 16.411 148.914 17.309 ;
     RECT  2.304 17.227 8.658 17.339 ;
     RECT  108.648 16.637 109.242 17.339 ;
     RECT  144.828 17.309 148.734 17.339 ;
     RECT  13.215 17.221 13.914 17.375 ;
     RECT  21.96 14.207 24.534 17.375 ;
     RECT  52.416 13.703 52.434 17.383 ;
     RECT  15.156 17.185 15.534 17.455 ;
     RECT  9.432 17.105 10.422 17.491 ;
     RECT  12.312 17.383 12.33 17.491 ;
     RECT  14.832 17.455 15.534 17.491 ;
     RECT  16.38 13.099 16.398 17.491 ;
     RECT  19.944 13.063 20.034 17.491 ;
     RECT  20.988 12.659 21.006 17.491 ;
     RECT  12.276 17.491 12.33 17.492 ;
     RECT  28.62 14.819 28.638 17.519 ;
     RECT  9.432 17.491 10.854 17.609 ;
     RECT  104.904 13.559 105.297 17.617 ;
     RECT  106.164 14.549 106.218 17.617 ;
     RECT  19.944 17.491 21.006 17.645 ;
     RECT  17.532 13.909 17.802 17.689 ;
     RECT  18.615 12.055 19.062 17.689 ;
     RECT  21.96 17.375 24.297 17.689 ;
     RECT  94.215 15.719 94.986 17.879 ;
     RECT  104.904 17.617 106.218 17.879 ;
     RECT  14.832 17.491 16.398 17.915 ;
     RECT  19.944 17.645 20.034 17.915 ;
     RECT  21.744 17.689 24.297 17.915 ;
     RECT  25.776 14.207 26.766 17.915 ;
     RECT  29.415 14.819 31.59 17.915 ;
     RECT  0.108 14.875 0.126 17.933 ;
     RECT  30.744 17.915 31.59 17.951 ;
     RECT  17.532 17.689 19.062 17.959 ;
     RECT  14.832 17.915 16.146 17.987 ;
     RECT  21.852 17.915 24.297 17.987 ;
     RECT  14.832 17.987 15.21 18.121 ;
     RECT  14.22 18.121 15.21 18.149 ;
     RECT  17.136 17.959 19.062 18.149 ;
     RECT  144.828 17.339 148.497 18.149 ;
     RECT  17.136 18.149 17.658 18.221 ;
     RECT  145.008 18.149 148.497 18.391 ;
     RECT  150.444 17.707 150.462 18.419 ;
     RECT  145.008 18.391 148.698 18.491 ;
     RECT  131.616 11.281 132.297 18.499 ;
     RECT  102.636 15.629 103.914 18.527 ;
     RECT  2.304 17.339 8.622 18.689 ;
     RECT  30.744 17.951 30.762 18.769 ;
     RECT  30.6 18.769 30.762 18.797 ;
     RECT  149.868 18.523 149.886 19.031 ;
     RECT  40.215 12.845 40.497 19.075 ;
     RECT  124.38 15.529 124.398 19.075 ;
     RECT  21.96 17.987 24.297 19.103 ;
     RECT  78.015 12.551 78.714 19.409 ;
     RECT  2.34 18.689 8.622 19.499 ;
     RECT  75.42 14.513 75.438 19.571 ;
     RECT  151.092 19.339 151.11 19.643 ;
     RECT  2.34 19.499 8.514 19.651 ;
     RECT  9.432 17.609 10.422 19.651 ;
     RECT  18.615 18.149 19.062 19.651 ;
     RECT  53.28 13.703 53.658 19.679 ;
     RECT  38.844 14.719 39.366 19.741 ;
     RECT  40.215 19.075 41.022 19.741 ;
     RECT  145.008 18.491 148.497 19.741 ;
     RECT  21.96 19.103 22.95 19.769 ;
     RECT  145.008 19.741 148.626 19.849 ;
     RECT  145.008 19.849 148.698 19.921 ;
     RECT  149.436 19.771 149.454 19.921 ;
     RECT  9.396 19.651 10.422 19.949 ;
     RECT  38.844 19.741 41.022 20.011 ;
     RECT  37.224 14.243 37.242 20.039 ;
     RECT  55.476 13.703 57.222 20.039 ;
     RECT  88.092 15.899 89.097 20.039 ;
     RECT  86.58 14.755 86.598 20.047 ;
     RECT  142.815 11.315 143.154 20.047 ;
     RECT  71.748 13.667 74.394 20.075 ;
     RECT  145.008 19.921 149.454 20.155 ;
     RECT  86.004 20.047 86.598 20.191 ;
     RECT  142.596 20.047 143.154 20.191 ;
     RECT  27.576 13.565 27.738 20.219 ;
     RECT  71.748 20.075 73.818 20.219 ;
     RECT  85.824 20.191 87.642 20.309 ;
     RECT  85.824 20.309 86.598 20.345 ;
     RECT  145.008 20.155 149.886 20.381 ;
     RECT  82.656 20.047 82.674 20.417 ;
     RECT  87.624 20.309 87.642 20.417 ;
     RECT  2.304 19.651 8.514 20.461 ;
     RECT  142.524 20.191 143.154 20.489 ;
     RECT  97.02 16.301 97.182 20.579 ;
     RECT  142.815 20.489 143.154 20.587 ;
     RECT  91.404 16.259 91.422 20.623 ;
     RECT  89.82 15.835 90.486 20.695 ;
     RECT  91.224 20.623 91.422 20.695 ;
     RECT  96.084 15.719 96.282 20.731 ;
     RECT  88.38 20.039 89.097 20.821 ;
     RECT  89.82 20.695 91.422 20.821 ;
     RECT  102.996 18.527 103.914 20.857 ;
     RECT  96.012 20.731 96.282 20.861 ;
     RECT  2.304 20.461 8.55 20.921 ;
     RECT  92.52 16.259 92.538 20.965 ;
     RECT  110.376 16.637 110.862 20.965 ;
     RECT  88.38 20.821 91.422 21.001 ;
     RECT  92.484 20.965 92.538 21.001 ;
     RECT  86.58 20.345 86.598 21.091 ;
     RECT  104.94 17.879 106.218 21.091 ;
     RECT  107.172 14.819 107.91 21.091 ;
     RECT  102.528 20.857 103.914 21.119 ;
     RECT  104.94 21.091 107.91 21.119 ;
     RECT  142.815 20.587 143.73 21.127 ;
     RECT  47.556 13.613 47.574 21.163 ;
     RECT  42.84 21.163 42.858 21.199 ;
     RECT  47.556 21.163 47.682 21.199 ;
     RECT  38.808 20.011 41.022 21.235 ;
     RECT  81.54 16.375 81.558 21.235 ;
     RECT  42.768 21.199 42.858 21.271 ;
     RECT  145.008 20.381 149.382 21.271 ;
     RECT  47.556 21.199 47.718 21.299 ;
     RECT  66.78 13.565 68.238 21.299 ;
     RECT  88.38 21.001 92.646 21.355 ;
     RECT  93.42 12.487 93.438 21.355 ;
     RECT  54.576 13.703 54.594 21.361 ;
     RECT  58.356 13.667 58.806 21.361 ;
     RECT  113.112 14.611 114.03 21.361 ;
     RECT  114.912 16.807 116.298 21.361 ;
     RECT  123.552 15.259 123.57 21.361 ;
     RECT  69.084 13.085 69.93 21.389 ;
     RECT  124.38 19.075 124.614 21.389 ;
     RECT  128.304 15.799 128.538 21.389 ;
     RECT  12.276 17.492 12.294 21.397 ;
     RECT  13.215 17.375 13.497 21.397 ;
     RECT  78.015 19.409 78.297 21.397 ;
     RECT  12.132 21.397 13.497 21.433 ;
     RECT  14.22 18.149 14.238 21.433 ;
     RECT  145.008 21.271 149.922 21.437 ;
     RECT  9.432 19.949 10.422 21.451 ;
     RECT  32.544 21.271 32.562 21.469 ;
     RECT  104.94 21.119 106.938 21.469 ;
     RECT  12.132 21.433 14.238 21.485 ;
     RECT  47.556 21.299 47.682 21.497 ;
     RECT  54.576 21.361 54.918 21.497 ;
     RECT  71.856 20.219 73.818 21.497 ;
     RECT  23.904 19.103 24.297 21.505 ;
     RECT  45.615 13.469 45.897 21.505 ;
     RECT  46.728 20.191 46.746 21.505 ;
     RECT  85.824 20.345 85.842 21.505 ;
     RECT  88.38 21.355 93.438 21.505 ;
     RECT  98.316 16.301 101.214 21.505 ;
     RECT  111.708 10.931 111.726 21.505 ;
     RECT  112.464 21.361 116.298 21.505 ;
     RECT  123.552 21.361 123.606 21.505 ;
     RECT  126.615 6.647 126.897 21.505 ;
     RECT  128.304 21.389 128.322 21.505 ;
     RECT  29.415 17.915 29.697 21.541 ;
     RECT  45.615 21.505 46.746 21.541 ;
     RECT  47.556 21.497 47.646 21.541 ;
     RECT  55.692 20.039 57.222 21.541 ;
     RECT  58.14 21.361 58.806 21.541 ;
     RECT  60.048 13.397 60.138 21.541 ;
     RECT  70.776 13.667 70.794 21.541 ;
     RECT  78.015 21.397 78.498 21.541 ;
     RECT  84.852 21.163 84.87 21.541 ;
     RECT  85.608 21.505 85.842 21.541 ;
     RECT  88.38 21.505 93.474 21.541 ;
     RECT  94.215 17.879 94.878 21.541 ;
     RECT  97.164 20.579 97.182 21.541 ;
     RECT  98.064 21.505 101.214 21.541 ;
     RECT  102.528 21.119 103.266 21.541 ;
     RECT  42.768 21.271 42.894 21.569 ;
     RECT  45.615 21.541 47.646 21.569 ;
     RECT  58.14 21.541 58.95 21.581 ;
     RECT  21.96 19.769 21.978 21.631 ;
     RECT  25.776 17.915 25.794 21.631 ;
     RECT  32.544 21.469 33.246 21.631 ;
     RECT  41.94 18.499 41.958 21.631 ;
     RECT  66.78 21.299 67.878 21.631 ;
     RECT  78.015 21.541 78.642 21.631 ;
     RECT  81.54 21.235 81.918 21.631 ;
     RECT  84.852 21.541 85.842 21.631 ;
     RECT  86.58 21.091 86.67 21.631 ;
     RECT  88.38 21.541 94.878 21.631 ;
     RECT  96.084 20.861 96.282 21.631 ;
     RECT  108.684 17.339 109.242 21.631 ;
     RECT  109.98 20.965 110.862 21.631 ;
     RECT  142.815 21.127 144.27 21.631 ;
     RECT  2.304 20.921 8.478 21.643 ;
     RECT  43.704 13.981 43.902 21.643 ;
     RECT  50.688 16.807 51.297 21.643 ;
     RECT  52.2 17.383 52.434 21.643 ;
     RECT  53.64 19.679 53.658 21.643 ;
     RECT  129.384 13.739 129.402 21.643 ;
     RECT  45.615 21.569 47.61 21.659 ;
     RECT  60.048 21.541 60.21 21.659 ;
     RECT  41.796 21.631 41.958 21.667 ;
     RECT  142.2 21.631 144.27 21.691 ;
     RECT  18.108 19.651 19.062 21.739 ;
     RECT  20.016 17.915 20.034 21.739 ;
     RECT  20.988 17.645 21.006 21.739 ;
     RECT  23.904 21.505 24.894 21.739 ;
     RECT  25.776 21.631 25.83 21.739 ;
     RECT  31.572 17.951 31.59 21.739 ;
     RECT  32.544 21.631 33.678 21.739 ;
     RECT  78.015 21.631 78.786 21.739 ;
     RECT  79.884 21.505 79.902 21.739 ;
     RECT  81.54 21.631 82.602 21.739 ;
     RECT  83.415 12.353 83.697 21.739 ;
     RECT  84.852 21.631 86.67 21.739 ;
     RECT  45.615 21.659 47.574 21.767 ;
     RECT  16.128 17.987 16.146 21.775 ;
     RECT  17.136 18.221 17.154 21.775 ;
     RECT  17.928 21.739 19.062 21.775 ;
     RECT  20.016 21.739 21.006 21.775 ;
     RECT  21.816 21.631 21.978 21.775 ;
     RECT  28.692 21.541 29.697 21.775 ;
     RECT  36.36 13.703 36.378 21.775 ;
     RECT  37.152 21.739 37.17 21.775 ;
     RECT  38.304 21.235 41.022 21.775 ;
     RECT  65.232 13.091 65.322 21.775 ;
     RECT  69.084 21.389 69.894 21.775 ;
     RECT  84.708 21.739 86.67 21.775 ;
     RECT  87.84 21.631 94.878 21.775 ;
     RECT  12.564 21.485 14.238 21.811 ;
     RECT  26.748 17.915 26.766 21.811 ;
     RECT  27.72 20.219 27.738 21.811 ;
     RECT  28.548 21.775 29.697 21.811 ;
     RECT  36.216 21.775 37.17 21.811 ;
     RECT  38.16 21.775 41.022 21.811 ;
     RECT  41.796 21.667 42.03 21.811 ;
     RECT  42.768 21.569 42.786 21.811 ;
     RECT  55.368 21.541 57.222 21.811 ;
     RECT  58.788 21.581 58.95 21.811 ;
     RECT  60.048 21.659 60.174 21.811 ;
     RECT  64.008 12.929 64.35 21.811 ;
     RECT  65.16 21.775 65.322 21.811 ;
     RECT  78.015 21.739 79.902 21.811 ;
     RECT  84.456 21.775 94.878 21.811 ;
     RECT  107.748 21.119 107.91 21.883 ;
     RECT  108.684 21.631 110.862 21.883 ;
     RECT  43.56 21.643 43.902 21.901 ;
     RECT  44.676 14.071 44.694 21.901 ;
     RECT  50.688 21.643 52.434 21.901 ;
     RECT  142.056 21.691 144.27 21.901 ;
     RECT  145.008 21.437 149.058 21.901 ;
     RECT  136.26 9.895 136.278 21.928 ;
     RECT  50.4 21.901 52.434 21.929 ;
     RECT  71.856 21.497 73.71 21.929 ;
     RECT  111.708 21.505 116.298 21.929 ;
     RECT  117.792 11.443 118.17 21.929 ;
     RECT  119.196 17.383 119.214 21.929 ;
     RECT  124.596 21.389 124.614 21.929 ;
     RECT  61.164 13.865 62.37 21.931 ;
     RECT  63.108 13.865 63.126 21.931 ;
     RECT  64.008 21.811 65.322 21.931 ;
     RECT  118.152 21.929 118.17 21.931 ;
     RECT  120.024 11.983 121.842 21.931 ;
     RECT  133.38 10.741 133.398 21.931 ;
     RECT  134.676 12.865 134.874 21.931 ;
     RECT  2.268 21.643 8.478 21.937 ;
     RECT  9.252 21.451 10.422 21.937 ;
     RECT  15.984 21.775 16.146 21.937 ;
     RECT  16.992 21.775 19.062 21.937 ;
     RECT  26.748 21.811 26.802 21.937 ;
     RECT  27.54 21.811 27.738 21.937 ;
     RECT  28.548 21.811 29.826 21.937 ;
     RECT  30.6 18.797 30.618 21.937 ;
     RECT  31.356 21.739 31.59 21.937 ;
     RECT  32.364 21.739 33.678 21.937 ;
     RECT  34.488 13.613 35.478 21.937 ;
     RECT  36.216 21.811 41.022 21.937 ;
     RECT  77.976 21.811 79.902 21.937 ;
     RECT  80.784 11.399 80.802 21.937 ;
     RECT  81.54 21.739 83.697 21.937 ;
     RECT  97.164 21.541 101.214 21.937 ;
     RECT  0.108 20.191 0.126 21.965 ;
     RECT  2.268 21.937 10.422 21.965 ;
     RECT  133.38 21.931 135.306 21.971 ;
     RECT  28.548 21.937 30.618 21.973 ;
     RECT  96.084 21.631 96.39 21.973 ;
     RECT  97.164 21.937 101.394 21.973 ;
     RECT  20.016 21.775 21.978 22.009 ;
     RECT  23.904 21.739 25.83 22.009 ;
     RECT  80.784 21.937 83.697 22.009 ;
     RECT  84.456 21.811 95.166 22.009 ;
     RECT  61.164 21.931 63.126 22.027 ;
     RECT  140.94 9.307 140.958 22.027 ;
     RECT  48.636 14.683 48.654 22.045 ;
     RECT  53.496 21.643 53.658 22.045 ;
     RECT  130.464 9.517 130.482 22.045 ;
     RECT  131.364 18.499 132.297 22.045 ;
     RECT  139.392 12.253 139.41 22.045 ;
     RECT  140.688 22.027 140.958 22.045 ;
     RECT  66.096 21.631 67.878 22.073 ;
     RECT  53.208 22.045 53.658 22.075 ;
     RECT  23.724 22.009 25.83 22.081 ;
     RECT  26.604 21.937 27.738 22.081 ;
     RECT  28.476 21.973 30.618 22.081 ;
     RECT  68.94 21.775 69.894 22.081 ;
     RECT  76.644 21.931 76.662 22.081 ;
     RECT  77.472 21.937 79.902 22.081 ;
     RECT  102.348 21.541 103.266 22.081 ;
     RECT  104.184 21.469 106.938 22.081 ;
     RECT  116.856 22.027 116.874 22.081 ;
     RECT  118.152 21.931 118.242 22.081 ;
     RECT  136.26 21.928 136.314 22.081 ;
     RECT  137.232 11.011 138.33 22.081 ;
     RECT  139.392 22.045 140.958 22.165 ;
     RECT  125.82 22.027 125.838 22.168 ;
     RECT  22.932 19.769 22.95 22.171 ;
     RECT  49.608 14.647 49.626 22.171 ;
     RECT  67.068 22.073 67.878 22.171 ;
     RECT  68.652 22.081 69.894 22.171 ;
     RECT  96.084 21.973 101.502 22.171 ;
     RECT  102.348 22.081 106.938 22.171 ;
     RECT  107.748 21.883 110.862 22.171 ;
     RECT  111.708 21.929 116.097 22.171 ;
     RECT  125.388 22.168 125.838 22.171 ;
     RECT  126.615 21.505 128.322 22.171 ;
     RECT  130.464 22.045 132.297 22.171 ;
     RECT  41.796 21.811 42.786 22.199 ;
     RECT  43.56 21.901 44.694 22.199 ;
     RECT  48.456 22.045 48.654 22.199 ;
     RECT  53.028 22.075 53.658 22.199 ;
     RECT  60.984 22.027 63.126 22.199 ;
     RECT  67.068 22.171 69.894 22.199 ;
     RECT  119.808 21.931 121.842 22.199 ;
     RECT  129.384 21.643 129.546 22.199 ;
     RECT  133.38 21.971 134.946 22.199 ;
     RECT  137.232 22.081 138.438 22.199 ;
     RECT  139.392 22.165 141.03 22.199 ;
     RECT  70.704 21.541 70.794 22.207 ;
     RECT  125.388 22.171 128.466 22.207 ;
     RECT  129.528 22.199 129.546 22.207 ;
     RECT  130.464 22.171 132.462 22.207 ;
     RECT  11.376 17.923 11.394 22.219 ;
     RECT  31.356 21.937 33.678 22.219 ;
     RECT  34.488 21.937 41.022 22.219 ;
     RECT  80.784 22.009 95.166 22.219 ;
     RECT  96.084 22.171 106.938 22.219 ;
     RECT  107.712 22.171 116.097 22.219 ;
     RECT  48.456 22.199 48.474 22.235 ;
     RECT  58.788 21.811 60.174 22.235 ;
     RECT  60.984 22.199 63.054 22.235 ;
     RECT  67.215 22.199 69.894 22.235 ;
     RECT  74.484 22.081 74.646 22.235 ;
     RECT  80.784 22.219 116.097 22.235 ;
     RECT  119.808 22.199 120.042 22.235 ;
     RECT  120.888 22.199 121.554 22.235 ;
     RECT  129.528 22.207 129.69 22.235 ;
     RECT  133.74 22.199 134.946 22.235 ;
     RECT  138.42 22.199 138.438 22.235 ;
     RECT  49.572 22.171 49.626 22.243 ;
     RECT  63.864 21.931 65.322 22.243 ;
     RECT  2.304 21.965 10.422 22.279 ;
     RECT  11.196 22.219 11.394 22.279 ;
     RECT  12.564 21.811 14.454 22.279 ;
     RECT  15.192 18.149 15.21 22.279 ;
     RECT  15.984 21.937 19.062 22.279 ;
     RECT  19.836 22.009 21.978 22.279 ;
     RECT  22.752 22.171 22.95 22.279 ;
     RECT  23.724 22.081 30.618 22.279 ;
     RECT  76.644 22.081 79.902 22.279 ;
     RECT  80.784 22.235 85.518 22.279 ;
     RECT  2.304 22.279 11.394 22.315 ;
     RECT  12.168 22.279 15.21 22.315 ;
     RECT  22.752 22.279 30.618 22.315 ;
     RECT  31.356 22.219 41.022 22.315 ;
     RECT  22.752 22.315 41.022 22.349 ;
     RECT  2.304 22.315 15.21 22.351 ;
     RECT  15.948 22.279 21.978 22.351 ;
     RECT  22.752 22.349 26.91 22.351 ;
     RECT  43.74 22.199 44.694 22.351 ;
     RECT  129.672 22.235 129.69 22.351 ;
     RECT  130.464 22.207 132.606 22.351 ;
     RECT  136.08 22.081 136.314 22.351 ;
     RECT  27.792 22.349 41.022 22.379 ;
     RECT  71.856 21.929 73.566 22.411 ;
     RECT  70.704 22.207 70.83 22.441 ;
     RECT  71.712 22.411 73.566 22.441 ;
     RECT  125.388 22.207 128.61 22.441 ;
     RECT  43.74 22.351 44.766 22.445 ;
     RECT  2.304 22.351 26.91 22.469 ;
     RECT  27.792 22.379 38.214 22.469 ;
     RECT  41.796 22.199 42.066 22.469 ;
     RECT  43.74 22.445 44.694 22.469 ;
     RECT  49.284 22.243 49.626 22.469 ;
     RECT  55.368 21.811 58.05 22.469 ;
     RECT  70.632 22.441 73.566 22.469 ;
     RECT  76.644 22.279 85.518 22.469 ;
     RECT  86.436 22.235 116.097 22.469 ;
     RECT  118.152 22.081 118.422 22.469 ;
     RECT  119.952 22.235 120.042 22.469 ;
     RECT  120.996 22.235 121.554 22.469 ;
     RECT  123.552 21.505 123.822 22.469 ;
     RECT  125.208 22.441 128.61 22.469 ;
     RECT  129.672 22.351 132.606 22.469 ;
     RECT  133.884 22.235 134.946 22.469 ;
     RECT  138.528 22.351 138.942 22.469 ;
     RECT  76.644 22.469 76.986 22.477 ;
     RECT  86.436 22.469 90.27 22.493 ;
     RECT  49.428 22.469 49.626 22.505 ;
     RECT  75.672 22.171 75.69 22.505 ;
     RECT  91.116 22.469 101.07 22.505 ;
     RECT  122.616 22.027 122.634 22.505 ;
     RECT  11.052 22.469 26.91 22.541 ;
     RECT  91.296 22.505 101.07 22.541 ;
     RECT  101.988 22.469 111.51 22.541 ;
     RECT  63.792 22.243 65.322 22.577 ;
     RECT  125.208 22.469 127.602 22.577 ;
     RECT  129.672 22.469 130.05 22.577 ;
     RECT  46.656 21.767 47.574 22.585 ;
     RECT  48.312 22.351 48.33 22.585 ;
     RECT  54.432 21.541 54.45 22.585 ;
     RECT  116.856 22.081 117.378 22.613 ;
     RECT  39.132 22.379 41.022 22.621 ;
     RECT  41.796 22.469 42.03 22.621 ;
     RECT  45.615 21.767 45.897 22.621 ;
     RECT  55.368 22.469 57.942 22.621 ;
     RECT  76.428 22.477 76.986 22.621 ;
     RECT  140.004 22.199 141.03 22.621 ;
     RECT  142.056 21.901 149.058 22.621 ;
     RECT  101.988 22.541 103.842 22.649 ;
     RECT  112.464 22.469 114.534 22.649 ;
     RECT  20.7 22.541 21.474 22.739 ;
     RECT  75.852 22.621 76.986 22.739 ;
     RECT  97.02 22.541 101.07 22.739 ;
     RECT  136.08 22.351 136.458 22.739 ;
     RECT  140.004 22.621 149.058 22.739 ;
     RECT  11.052 22.541 19.962 22.775 ;
     RECT  140.004 22.739 141.642 22.775 ;
     RECT  0.144 22.747 0.162 22.783 ;
     RECT  22.536 22.541 26.91 22.811 ;
     RECT  31.716 22.469 38.214 22.811 ;
     RECT  138.528 22.469 138.834 22.811 ;
     RECT  66.096 22.073 66.186 22.855 ;
     RECT  134.676 22.469 134.946 22.855 ;
     RECT  42.804 22.351 42.822 22.891 ;
     RECT  53.028 22.199 53.262 22.891 ;
     RECT  54.144 22.585 54.45 22.981 ;
     RECT  55.332 22.621 57.942 22.981 ;
     RECT  2.304 22.469 10.242 23.009 ;
     RECT  65.988 22.855 66.186 23.009 ;
     RECT  72.576 22.469 73.566 23.009 ;
     RECT  131.148 22.469 132.606 23.009 ;
     RECT  133.884 22.469 133.902 23.009 ;
     RECT  11.088 22.775 19.962 23.045 ;
     RECT  31.716 22.811 36.198 23.081 ;
     RECT  2.304 23.009 9.198 23.125 ;
     RECT  27.792 22.469 30.798 23.125 ;
     RECT  45.468 22.621 45.897 23.125 ;
     RECT  46.656 22.585 48.33 23.125 ;
     RECT  67.215 22.235 68.382 23.125 ;
     RECT  74.628 22.235 74.646 23.125 ;
     RECT  131.976 23.009 132.606 23.125 ;
     RECT  134.676 22.855 135.342 23.125 ;
     RECT  136.188 22.739 136.458 23.125 ;
     RECT  137.415 22.199 137.697 23.125 ;
     RECT  37.044 22.811 38.214 23.161 ;
     RECT  39.132 22.621 42.03 23.161 ;
     RECT  42.804 22.891 42.93 23.161 ;
     RECT  43.74 22.469 44.586 23.161 ;
     RECT  49.572 22.505 49.626 23.161 ;
     RECT  58.788 22.235 59.166 23.161 ;
     RECT  59.94 22.235 60.174 23.161 ;
     RECT  61.02 22.235 63.054 23.161 ;
     RECT  63.792 22.577 65.034 23.161 ;
     RECT  69.372 22.235 69.894 23.161 ;
     RECT  70.632 22.469 71.586 23.161 ;
     RECT  125.208 22.577 125.226 23.161 ;
     RECT  27.576 23.125 30.798 23.251 ;
     RECT  31.716 23.081 36.126 23.251 ;
     RECT  37.044 23.161 42.03 23.251 ;
     RECT  42.804 23.161 44.586 23.251 ;
     RECT  45.468 23.125 48.33 23.251 ;
     RECT  58.788 23.161 60.174 23.251 ;
     RECT  61.02 23.161 65.034 23.251 ;
     RECT  69.372 23.161 71.586 23.251 ;
     RECT  72.576 23.009 73.062 23.251 ;
     RECT  2.268 23.125 9.198 23.261 ;
     RECT  11.088 23.045 19.854 23.279 ;
     RECT  22.536 22.811 26.802 23.279 ;
     RECT  27.576 23.251 36.126 23.279 ;
     RECT  37.044 23.251 44.586 23.279 ;
     RECT  58.68 23.251 65.034 23.279 ;
     RECT  69.372 23.251 73.062 23.279 ;
     RECT  75.852 22.739 76.77 23.279 ;
     RECT  77.796 22.469 84.618 23.279 ;
     RECT  85.464 22.469 85.518 23.279 ;
     RECT  87.408 22.493 90.27 23.279 ;
     RECT  91.296 22.541 92.286 23.279 ;
     RECT  93.168 22.541 93.186 23.279 ;
     RECT  94.14 22.541 96.174 23.279 ;
     RECT  97.02 22.739 100.854 23.279 ;
     RECT  102.024 22.649 103.842 23.279 ;
     RECT  104.688 22.541 107.838 23.279 ;
     RECT  108.576 22.541 108.594 23.279 ;
     RECT  110.415 22.541 111.51 23.279 ;
     RECT  112.464 22.649 112.482 23.279 ;
     RECT  118.404 22.469 118.422 23.279 ;
     RECT  119.952 22.469 119.97 23.279 ;
     RECT  123.588 22.469 123.822 23.279 ;
     RECT  125.964 22.577 127.602 23.279 ;
     RECT  128.34 22.469 128.61 23.279 ;
     RECT  131.148 23.009 131.166 23.279 ;
     RECT  131.976 23.125 132.858 23.279 ;
     RECT  134.676 23.125 135.378 23.279 ;
     RECT  22.536 23.279 25.758 23.287 ;
     RECT  66.924 23.125 68.382 23.287 ;
     RECT  142.704 22.739 149.058 23.287 ;
     RECT  149.904 21.437 149.922 23.287 ;
     RECT  69.912 23.279 72.99 23.315 ;
     RECT  81.144 23.279 84.618 23.315 ;
     RECT  45.468 23.251 48.654 23.323 ;
     RECT  49.572 23.161 49.662 23.323 ;
     RECT  50.4 21.929 52.254 23.323 ;
     RECT  52.992 22.891 53.262 23.323 ;
     RECT  113.436 22.649 114.534 23.323 ;
     RECT  14.94 23.279 17.838 23.351 ;
     RECT  22.5 23.287 25.758 23.351 ;
     RECT  27.684 23.279 31.446 23.351 ;
     RECT  33.408 23.279 36.126 23.351 ;
     RECT  37.044 23.279 38.286 23.351 ;
     RECT  39.132 23.279 43.83 23.351 ;
     RECT  69.912 23.315 70.038 23.351 ;
     RECT  70.776 23.315 72.99 23.351 ;
     RECT  20.808 22.739 21.474 23.395 ;
     RECT  22.5 23.351 25.578 23.395 ;
     RECT  44.568 23.279 44.586 23.395 ;
     RECT  45.468 23.323 49.662 23.395 ;
     RECT  50.4 23.323 53.262 23.395 ;
     RECT  54.144 22.981 57.942 23.395 ;
     RECT  64.98 23.279 65.034 23.395 ;
     RECT  26.496 23.279 26.802 23.423 ;
     RECT  44.568 23.395 49.662 23.431 ;
     RECT  50.4 23.395 57.942 23.431 ;
     RECT  58.68 23.279 62.097 23.431 ;
     RECT  77.796 23.279 79.398 23.431 ;
     RECT  82.296 23.315 84.618 23.431 ;
     RECT  86.436 22.493 86.562 23.431 ;
     RECT  94.14 23.279 94.842 23.431 ;
     RECT  95.76 23.279 96.174 23.431 ;
     RECT  102.024 23.279 102.51 23.431 ;
     RECT  103.464 23.279 103.842 23.431 ;
     RECT  104.688 23.279 106.362 23.431 ;
     RECT  107.316 23.279 107.838 23.431 ;
     RECT  109.548 22.541 109.566 23.431 ;
     RECT  110.415 23.279 111.222 23.431 ;
     RECT  113.436 23.323 114.606 23.431 ;
     RECT  117.108 22.613 117.378 23.431 ;
     RECT  120.996 22.469 121.497 23.431 ;
     RECT  124.776 23.161 125.226 23.431 ;
     RECT  125.964 23.279 127.566 23.431 ;
     RECT  134.676 23.279 135.234 23.431 ;
     RECT  142.704 23.287 149.922 23.501 ;
     RECT  44.568 23.431 62.097 23.507 ;
     RECT  88.092 23.279 89.097 23.507 ;
     RECT  115.488 22.469 116.097 23.507 ;
     RECT  142.704 23.501 149.742 23.507 ;
     RECT  2.304 23.261 9.198 23.549 ;
     RECT  9.972 23.009 10.242 23.549 ;
     RECT  15.804 23.351 17.838 23.549 ;
     RECT  20.808 23.395 25.578 23.549 ;
     RECT  27.684 23.351 30.366 23.549 ;
     RECT  31.32 23.351 31.446 23.549 ;
     RECT  32.292 23.279 32.49 23.549 ;
     RECT  33.588 23.351 36.126 23.549 ;
     RECT  37.044 23.351 38.07 23.549 ;
     RECT  39.132 23.351 41.922 23.549 ;
     RECT  44.568 23.507 61.974 23.549 ;
     RECT  62.82 23.279 64.17 23.549 ;
     RECT  64.98 23.395 65.286 23.549 ;
     RECT  66.024 23.009 66.186 23.549 ;
     RECT  66.924 23.287 68.994 23.549 ;
     RECT  70.776 23.351 71.802 23.549 ;
     RECT  73.8 23.125 74.646 23.549 ;
     RECT  75.564 23.431 75.582 23.549 ;
     RECT  76.536 23.279 76.77 23.549 ;
     RECT  77.508 23.431 79.398 23.549 ;
     RECT  80.352 23.279 80.406 23.549 ;
     RECT  81.144 23.315 81.342 23.549 ;
     RECT  82.296 23.431 85.194 23.549 ;
     RECT  86.148 23.431 87.138 23.549 ;
     RECT  88.092 23.507 88.974 23.549 ;
     RECT  91.008 23.431 91.026 23.549 ;
     RECT  91.908 23.279 91.962 23.549 ;
     RECT  92.7 23.431 92.898 23.549 ;
     RECT  93.852 23.431 94.842 23.549 ;
     RECT  95.76 23.431 96.75 23.549 ;
     RECT  97.704 23.279 100.566 23.549 ;
     RECT  101.7 23.431 102.51 23.549 ;
     RECT  103.464 23.431 106.362 23.549 ;
     RECT  107.316 23.431 108.306 23.549 ;
     RECT  109.26 23.431 111.222 23.549 ;
     RECT  111.96 23.431 112.194 23.549 ;
     RECT  113.148 23.431 114.606 23.549 ;
     RECT  115.488 23.507 116.01 23.549 ;
     RECT  116.964 23.431 117.378 23.549 ;
     RECT  118.584 23.323 118.602 23.549 ;
     RECT  119.844 23.431 119.862 23.549 ;
     RECT  123.588 23.279 123.678 23.549 ;
     RECT  124.632 23.431 127.566 23.549 ;
     RECT  128.484 23.279 128.61 23.549 ;
     RECT  129.672 22.577 129.942 23.549 ;
     RECT  131.112 23.431 131.13 23.549 ;
     RECT  134.316 23.431 135.234 23.549 ;
     RECT  136.188 23.125 137.754 23.549 ;
     RECT  140.04 22.775 141.642 23.549 ;
     RECT  142.704 23.507 142.974 23.549 ;
     RECT  143.712 23.507 149.742 23.549 ;
     RECT  66.096 23.549 66.186 23.557 ;
     RECT  66.924 23.549 68.886 23.557 ;
     RECT  2.304 23.549 3.726 23.585 ;
     RECT  11.088 23.279 14.022 23.585 ;
     RECT  15.876 23.549 16.902 23.585 ;
     RECT  20.808 23.549 22.662 23.585 ;
     RECT  37.296 23.549 38.07 23.585 ;
     RECT  39.924 23.549 41.058 23.585 ;
     RECT  42.768 23.351 43.83 23.585 ;
     RECT  44.568 23.549 46.746 23.585 ;
     RECT  47.484 23.549 48.654 23.585 ;
     RECT  49.68 23.549 49.842 23.585 ;
     RECT  53.46 23.549 54.198 23.585 ;
     RECT  55.044 23.549 56.505 23.585 ;
     RECT  57.312 23.549 58.05 23.585 ;
     RECT  58.896 23.549 61.974 23.585 ;
     RECT  62.82 23.549 63.09 23.585 ;
     RECT  64.044 23.549 64.098 23.585 ;
     RECT  66.096 23.557 68.886 23.585 ;
     RECT  82.332 23.549 84.978 23.585 ;
     RECT  97.74 23.549 100.386 23.585 ;
     RECT  2.304 23.585 3.402 23.621 ;
     RECT  18.576 23.279 19.854 23.621 ;
     RECT  59.22 23.585 60.426 23.621 ;
     RECT  64.98 23.549 65.034 23.621 ;
     RECT  74.556 23.549 74.646 23.621 ;
     RECT  20.808 23.585 20.898 23.657 ;
     RECT  23.616 23.549 24.678 23.657 ;
     RECT  29.415 23.549 30.366 23.657 ;
     RECT  76.572 23.549 76.77 23.665 ;
     RECT  77.508 23.549 79.218 23.665 ;
     RECT  101.7 23.549 102.33 23.665 ;
     RECT  117 23.549 117.378 23.665 ;
     RECT  120.816 23.431 121.497 23.665 ;
     RECT  122.76 22.585 122.778 23.665 ;
     RECT  128.52 23.549 128.61 23.665 ;
     RECT  132.015 23.279 132.858 23.665 ;
     RECT  137.088 23.549 137.754 23.665 ;
     RECT  138.6 22.811 138.834 23.665 ;
     RECT  12.132 23.585 14.022 23.693 ;
     RECT  5.328 23.549 5.67 23.729 ;
     RECT  6.408 23.549 9.198 23.729 ;
     RECT  10.044 23.549 10.242 23.729 ;
     RECT  28.44 23.549 28.674 23.729 ;
     RECT  66.096 23.585 67.305 23.729 ;
     RECT  144.684 23.549 149.742 23.729 ;
     RECT  75.348 23.665 75.366 23.741 ;
     RECT  84.24 23.585 84.978 23.741 ;
     RECT  86.184 23.549 86.922 23.741 ;
     RECT  90.792 23.665 90.81 23.741 ;
     RECT  95.796 23.549 96.534 23.741 ;
     RECT  105.015 23.549 106.146 23.741 ;
     RECT  109.296 23.549 111.222 23.741 ;
     RECT  111.96 23.549 111.978 23.741 ;
     RECT  117 23.665 117.702 23.741 ;
     RECT  140.076 23.549 140.814 23.741 ;
     RECT  145.872 23.729 147.294 23.741 ;
     RECT  148.215 23.729 149.742 23.741 ;
     RECT  2.304 23.621 2.505 23.777 ;
     RECT  6.516 23.729 9.198 23.777 ;
     RECT  13.032 23.693 14.022 23.777 ;
     RECT  18.576 23.621 18.705 23.777 ;
     RECT  23.616 23.657 24.606 23.777 ;
     RECT  29.415 23.657 29.574 23.777 ;
     RECT  33.588 23.549 35.19 23.777 ;
     RECT  39.96 23.585 40.914 23.777 ;
     RECT  44.964 23.585 46.746 23.777 ;
     RECT  51.015 23.549 51.534 23.777 ;
     RECT  56.376 23.585 56.505 23.777 ;
     RECT  61.164 23.585 61.974 23.777 ;
     RECT  66.924 23.729 67.305 23.777 ;
     RECT  72.615 23.351 72.99 23.777 ;
     RECT  76.572 23.665 79.218 23.777 ;
     RECT  82.332 23.585 83.505 23.777 ;
     RECT  88.092 23.549 88.905 23.777 ;
     RECT  93.888 23.549 94.662 23.777 ;
     RECT  105.015 23.741 105.462 23.777 ;
     RECT  110.415 23.741 111.222 23.777 ;
     RECT  115.815 23.549 116.01 23.777 ;
     RECT  126.54 23.549 127.386 23.777 ;
     RECT  132.015 23.665 132.894 23.777 ;
     RECT  137.088 23.665 138.87 23.777 ;
     RECT  142.815 23.549 142.974 23.777 ;
     RECT  148.215 23.741 148.305 23.777 ;
     RECT  0.108 22.783 0.162 23.789 ;
     RECT  3.24 23.621 3.402 23.819 ;
     RECT  146.988 23.741 147.294 23.819 ;
     RECT  72.72 23.777 72.99 23.855 ;
     RECT  142.956 23.777 142.974 23.885 ;
     RECT  150.48 23.791 150.498 23.885 ;
     RECT  6.516 23.777 7.398 23.927 ;
     RECT  99.432 23.585 100.386 23.927 ;
     RECT  126.54 23.777 126.63 23.927 ;
     RECT  4.536 23.549 4.554 23.933 ;
     RECT  14.004 23.777 14.022 23.933 ;
     RECT  25.56 23.549 25.578 23.933 ;
     RECT  29.556 23.777 29.574 23.933 ;
     RECT  31.32 23.549 31.338 23.933 ;
     RECT  33.588 23.777 34.218 23.933 ;
     RECT  48.636 23.585 48.654 23.933 ;
     RECT  56.376 23.777 56.394 23.933 ;
     RECT  60.408 23.621 60.426 23.933 ;
     RECT  61.956 23.777 61.974 23.933 ;
     RECT  66.096 23.729 66.114 23.933 ;
     RECT  71.784 23.549 71.802 23.933 ;
     RECT  81.144 23.549 81.162 23.933 ;
     RECT  94.644 23.777 94.662 23.933 ;
     RECT  99.648 23.927 100.386 23.933 ;
     RECT  101.592 23.665 102.33 23.933 ;
     RECT  115.992 23.777 116.01 23.933 ;
     RECT  120.816 23.665 121.554 23.933 ;
     RECT  127.368 23.777 127.386 23.933 ;
     RECT  132.372 23.777 132.894 23.933 ;
     RECT  137.088 23.777 137.106 23.933 ;
     RECT  10.044 23.729 10.062 23.981 ;
     RECT  17.82 23.549 17.838 23.981 ;
     RECT  0.144 23.789 0.162 24.029 ;
     RECT  2.304 23.777 2.322 24.269 ;
     RECT  147.276 23.819 147.294 24.317 ;
     RECT  12.132 23.693 12.15 24.509 ;
     RECT  15.876 23.585 15.894 24.509 ;
     RECT  22.032 23.585 22.662 24.509 ;
     RECT  23.616 23.777 23.634 24.509 ;
     RECT  27.684 23.549 27.702 24.509 ;
     RECT  39.132 23.549 39.15 24.509 ;
     RECT  40.896 23.777 40.914 24.509 ;
     RECT  43.236 23.585 43.83 24.509 ;
     RECT  44.964 23.777 44.982 24.509 ;
     RECT  52.632 23.549 52.65 24.509 ;
     RECT  64.08 23.585 64.098 24.509 ;
     RECT  68.076 23.585 68.094 24.509 ;
     RECT  69.912 23.351 69.93 24.509 ;
     RECT  73.8 23.549 73.818 24.509 ;
     RECT  149.04 23.741 149.742 24.749 ;
     RECT  1.404 22.477 1.422 24.797 ;
     RECT  6.516 23.927 7.254 25.085 ;
     RECT  35.172 23.777 35.19 25.085 ;
     RECT  46.116 23.777 46.746 25.085 ;
     RECT  76.572 23.777 77.31 25.133 ;
     RECT  82.332 23.777 83.034 25.133 ;
     RECT  88.092 23.777 88.794 25.133 ;
     RECT  97.74 23.585 98.478 25.133 ;
     RECT  103.5 23.549 104.202 25.133 ;
     RECT  107.352 23.549 108.09 25.133 ;
     RECT  118.908 23.665 119.646 25.133 ;
     RECT  124.668 23.549 125.154 25.133 ;
     RECT  138.168 23.777 138.87 25.133 ;
     RECT  144.684 23.729 144.702 25.133 ;
     RECT  8.496 23.777 9.198 25.805 ;
     RECT  19.836 23.621 19.854 25.805 ;
     RECT  37.368 23.585 38.07 25.805 ;
     RECT  78.48 23.777 79.218 25.805 ;
     RECT  92.7 23.549 92.718 25.805 ;
     RECT  113.148 23.549 113.886 25.805 ;
     RECT  122.76 23.665 123.498 25.805 ;
     RECT  128.52 23.665 129.222 25.805 ;
     RECT  130.464 23.629 130.95 25.805 ;
     RECT  134.316 23.549 135.054 25.805 ;
     RECT  18.576 23.777 18.594 25.861 ;
     RECT  46.116 25.085 46.134 25.861 ;
     RECT  49.68 23.585 49.698 25.861 ;
     RECT  74.556 23.621 74.574 25.861 ;
     RECT  18.576 25.861 18.81 25.889 ;
     RECT  45.756 25.861 46.134 25.889 ;
     RECT  49.608 25.861 49.698 25.889 ;
     RECT  74.556 25.861 74.646 25.889 ;
     RECT  1.476 25.819 1.494 25.901 ;
     RECT  3.384 23.819 3.402 25.901 ;
     RECT  5.328 23.729 5.346 25.901 ;
     RECT  7.236 25.085 7.254 25.901 ;
     RECT  9.18 25.805 9.198 25.901 ;
     RECT  11.088 23.585 11.106 25.901 ;
     RECT  13.032 23.777 13.05 25.901 ;
     RECT  14.94 23.351 14.958 25.901 ;
     RECT  16.884 23.585 16.902 25.901 ;
     RECT  18.792 25.889 18.81 25.901 ;
     RECT  20.736 23.701 20.754 25.901 ;
     RECT  22.644 24.509 22.662 25.901 ;
     RECT  24.588 23.777 24.606 25.901 ;
     RECT  26.496 23.423 26.514 25.901 ;
     RECT  28.44 23.729 28.458 25.901 ;
     RECT  30.348 23.657 30.366 25.901 ;
     RECT  32.292 23.549 32.31 25.901 ;
     RECT  34.2 23.933 34.218 25.901 ;
     RECT  36.108 23.549 36.126 25.901 ;
     RECT  38.052 25.805 38.07 25.901 ;
     RECT  39.96 23.777 39.978 25.901 ;
     RECT  41.904 23.549 41.922 25.901 ;
     RECT  43.812 24.509 43.83 25.901 ;
     RECT  45.756 25.889 45.774 25.901 ;
     RECT  47.664 23.585 47.682 25.901 ;
     RECT  49.608 25.889 49.626 25.901 ;
     RECT  51.516 23.777 51.534 25.901 ;
     RECT  53.46 23.585 53.478 25.901 ;
     RECT  55.368 23.585 55.386 25.901 ;
     RECT  57.312 23.585 57.33 25.901 ;
     RECT  59.22 23.621 59.238 25.901 ;
     RECT  61.164 23.777 61.182 25.901 ;
     RECT  63.072 23.585 63.09 25.901 ;
     RECT  65.016 23.621 65.034 25.901 ;
     RECT  66.924 23.777 66.942 25.901 ;
     RECT  68.868 23.585 68.886 25.901 ;
     RECT  70.776 23.549 70.794 25.901 ;
     RECT  72.72 23.855 72.738 25.901 ;
     RECT  74.628 25.889 74.646 25.901 ;
     RECT  76.572 25.133 76.59 25.901 ;
     RECT  78.48 25.805 78.498 25.901 ;
     RECT  80.388 23.549 80.406 25.901 ;
     RECT  82.332 25.133 82.35 25.901 ;
     RECT  84.24 23.741 84.258 25.901 ;
     RECT  86.184 23.741 86.202 25.901 ;
     RECT  88.092 25.133 88.11 25.901 ;
     RECT  90.036 23.279 90.054 25.901 ;
     RECT  91.944 23.549 91.962 25.901 ;
     RECT  93.888 23.777 93.906 25.901 ;
     RECT  95.796 23.741 95.814 25.901 ;
     RECT  97.74 25.133 97.758 25.901 ;
     RECT  99.648 23.933 99.666 25.901 ;
     RECT  101.592 23.933 101.61 25.901 ;
     RECT  103.5 25.133 103.518 25.901 ;
     RECT  105.444 23.777 105.462 25.901 ;
     RECT  107.352 25.133 107.37 25.901 ;
     RECT  109.296 23.741 109.314 25.901 ;
     RECT  111.204 23.777 111.222 25.901 ;
     RECT  113.148 25.805 113.166 25.901 ;
     RECT  115.056 23.665 115.074 25.901 ;
     RECT  117 23.741 117.018 25.901 ;
     RECT  118.908 25.133 118.926 25.901 ;
     RECT  120.816 23.933 120.834 25.901 ;
     RECT  122.76 25.805 122.778 25.901 ;
     RECT  124.668 25.133 124.686 25.901 ;
     RECT  126.612 23.927 126.63 25.901 ;
     RECT  128.52 25.805 128.538 25.901 ;
     RECT  130.464 25.805 130.482 25.901 ;
     RECT  132.372 23.933 132.39 25.901 ;
     RECT  134.316 25.805 134.334 25.901 ;
     RECT  136.224 23.549 136.242 25.901 ;
     RECT  138.168 25.133 138.186 25.901 ;
     RECT  140.076 23.741 140.094 25.901 ;
     RECT  142.02 23.665 142.038 25.901 ;
     RECT  143.928 23.549 143.946 25.901 ;
     RECT  145.872 23.741 145.89 25.901 ;
     RECT  147.78 25.099 147.798 25.901 ;
     RECT  149.724 24.749 149.742 25.901 ;
    LAYER M4 ;
     RECT  0.06 1.104 1.433 24.792 ;
     RECT  1.436 25.824 1.523 25.848 ;
     RECT  1.433 1.104 2.333 24.264 ;
     RECT  2.333 1.104 2.437 23.772 ;
     RECT  2.437 0.816 2.512 23.772 ;
     RECT  2.512 0.816 2.704 23.592 ;
     RECT  2.704 7.632 2.765 8.184 ;
     RECT  2.704 12.048 2.765 12.072 ;
     RECT  2.704 18.528 2.765 19.656 ;
     RECT  2.704 0.816 2.801 5.832 ;
     RECT  2.765 8.16 2.801 8.184 ;
     RECT  2.704 13.056 2.801 15.816 ;
     RECT  2.437 25.776 2.819 25.8 ;
     RECT  2.801 2.064 2.837 5.304 ;
     RECT  2.801 13.056 2.837 13.608 ;
     RECT  2.765 19.056 2.837 19.656 ;
     RECT  2.704 16.8 2.909 17.112 ;
     RECT  2.909 17.088 2.981 17.112 ;
     RECT  2.704 21.12 3.089 23.592 ;
     RECT  2.801 14.976 3.125 15.816 ;
     RECT  3.125 14.976 3.341 15 ;
     RECT  3.089 21.12 3.841 23.4 ;
     RECT  2.837 19.152 3.949 19.656 ;
     RECT  3.841 20.832 3.949 23.4 ;
     RECT  3.949 19.152 3.971 23.4 ;
     RECT  2.837 2.064 4.261 5.16 ;
     RECT  2.801 0.816 4.277 0.84 ;
     RECT  4.261 2.064 4.337 5.736 ;
     RECT  4.337 1.728 4.345 5.736 ;
     RECT  2.837 13.344 4.345 13.368 ;
     RECT  4.345 1.728 4.385 5.784 ;
     RECT  4.385 1.728 4.421 1.752 ;
     RECT  4.385 2.832 4.499 5.784 ;
     RECT  4.309 12 4.501 12.024 ;
     RECT  4.489 10.608 4.525 10.632 ;
     RECT  4.501 11.664 4.525 12.024 ;
     RECT  4.093 15.936 4.561 15.96 ;
     RECT  4.357 23.904 4.565 23.928 ;
     RECT  3.971 19.152 4.787 22.872 ;
     RECT  4.561 15.936 4.889 16.92 ;
     RECT  4.525 10.608 4.921 12.024 ;
     RECT  4.499 2.832 5.177 4.824 ;
     RECT  4.597 8.976 5.209 9 ;
     RECT  4.093 14.592 5.213 14.616 ;
     RECT  4.381 17.904 5.213 17.928 ;
     RECT  4.345 7.68 5.281 7.704 ;
     RECT  5.281 7.2 5.429 7.704 ;
     RECT  5.389 18.816 5.507 18.84 ;
     RECT  5.209 8.688 5.573 9 ;
     RECT  4.787 20.16 5.573 22.872 ;
     RECT  5.177 2.88 5.701 4.824 ;
     RECT  5.573 20.88 5.897 22.728 ;
     RECT  4.345 13.104 5.965 13.368 ;
     RECT  5.897 22.464 5.969 22.728 ;
     RECT  4.921 10.128 5.989 12.024 ;
     RECT  4.889 16.032 5.996 16.92 ;
     RECT  5.701 2.88 6.185 5.352 ;
     RECT  5.965 13.104 6.217 13.704 ;
     RECT  6.185 4.128 6.361 5.352 ;
     RECT  5.429 7.2 6.361 7.416 ;
     RECT  6.361 4.128 6.365 7.416 ;
     RECT  6.325 0.096 6.409 0.12 ;
     RECT  5.996 15.648 6.437 16.92 ;
     RECT  6.365 4.128 6.473 6.312 ;
     RECT  6.277 25.056 6.545 25.08 ;
     RECT  6.217 13.056 6.793 13.704 ;
     RECT  6.437 15.648 6.793 16.104 ;
     RECT  5.573 8.688 6.829 8.712 ;
     RECT  6.365 7.392 6.853 7.416 ;
     RECT  6.829 8.688 6.853 8.808 ;
     RECT  6.793 13.056 6.937 14.232 ;
     RECT  6.853 7.392 6.949 8.808 ;
     RECT  5.989 10.08 6.949 12.024 ;
     RECT  6.949 7.392 7.117 12.024 ;
     RECT  6.937 13.056 7.117 14.28 ;
     RECT  5.969 22.464 7.117 22.488 ;
     RECT  6.185 2.88 7.808 3.144 ;
     RECT  6.473 4.128 7.808 4.536 ;
     RECT  6.473 6.288 7.808 6.312 ;
     RECT  7.117 7.392 7.808 14.28 ;
     RECT  6.793 15.312 7.808 16.104 ;
     RECT  6.685 18.24 7.808 18.264 ;
     RECT  7.117 19.632 7.808 19.656 ;
     RECT  5.897 20.88 7.808 21.432 ;
     RECT  7.117 22.464 7.808 22.872 ;
     RECT  7.808 2.148 7.912 23.772 ;
     RECT  7.912 2.148 8.104 23.502 ;
     RECT  8.104 6.288 8.273 6.312 ;
     RECT  8.197 1.728 8.291 1.752 ;
     RECT  8.104 19.632 8.339 22.872 ;
     RECT  8.104 16.032 8.381 16.104 ;
     RECT  8.339 19.632 8.381 22.824 ;
     RECT  8.381 20.448 8.387 22.824 ;
     RECT  8.104 8.688 8.417 13.368 ;
     RECT  8.197 25.776 8.525 25.8 ;
     RECT  8.387 21.408 8.669 22.824 ;
     RECT  8.669 21.408 9.281 21.912 ;
     RECT  10.033 23.952 10.163 23.976 ;
     RECT  10.141 0.096 10.225 0.12 ;
     RECT  9.281 21.408 11.113 21.48 ;
     RECT  11.113 21.408 11.225 22.44 ;
     RECT  12.037 24.48 12.161 24.504 ;
     RECT  12.121 0.096 12.205 0.12 ;
     RECT  8.104 3.12 13.208 4.248 ;
     RECT  8.417 8.688 13.208 12.312 ;
     RECT  8.417 13.344 13.208 13.368 ;
     RECT  8.381 16.032 13.208 16.056 ;
     RECT  11.225 21.408 13.208 22.248 ;
     RECT  13.208 2.148 13.312 23.772 ;
     RECT  13.312 2.418 13.504 23.772 ;
     RECT  13.949 23.904 14.033 23.928 ;
     RECT  13.504 21.408 14.105 22.776 ;
     RECT  14.029 0.096 14.113 0.12 ;
     RECT  14.105 22.752 15.901 22.776 ;
     RECT  15.865 24.48 15.949 24.504 ;
     RECT  14.105 21.408 15.973 21.432 ;
     RECT  15.901 22.704 15.973 22.776 ;
     RECT  15.973 21.408 16.019 22.776 ;
     RECT  15.937 0.096 16.021 0.12 ;
     RECT  16.019 21.408 16.049 22.728 ;
     RECT  13.504 3.12 16.156 4.248 ;
     RECT  16.156 3.12 17.701 3.192 ;
     RECT  17.701 3.12 17.845 3.24 ;
     RECT  16.156 4.224 17.845 4.248 ;
     RECT  17.804 23.952 17.891 23.976 ;
     RECT  16.049 21.408 17.953 22.248 ;
     RECT  17.909 0.096 17.993 0.12 ;
     RECT  17.845 3.12 18.608 4.248 ;
     RECT  13.504 8.688 18.608 12.312 ;
     RECT  13.504 13.344 18.608 13.368 ;
     RECT  13.504 16.032 18.608 16.056 ;
     RECT  17.953 21.408 18.608 22.488 ;
     RECT  18.608 2.148 18.712 23.772 ;
     RECT  18.712 2.418 18.904 23.502 ;
     RECT  18.904 21.408 18.965 22.488 ;
     RECT  19.765 25.776 19.865 25.8 ;
     RECT  19.825 1.728 19.909 1.752 ;
     RECT  18.904 3.12 21.809 4.248 ;
     RECT  21.805 0.096 21.889 0.12 ;
     RECT  21.685 24.48 22.061 24.504 ;
     RECT  18.904 8.688 22.813 12.312 ;
     RECT  18.904 13.344 22.813 13.368 ;
     RECT  23.605 24.48 23.689 24.504 ;
     RECT  23.749 1.728 23.861 1.752 ;
     RECT  21.809 3.12 24.008 3.144 ;
     RECT  21.809 4.128 24.008 4.248 ;
     RECT  22.813 8.688 24.008 13.368 ;
     RECT  18.904 16.032 24.008 16.056 ;
     RECT  18.965 21.408 24.008 22.2 ;
     RECT  24.008 2.148 24.112 23.772 ;
     RECT  24.112 2.418 24.304 23.502 ;
     RECT  24.304 21.408 24.659 22.152 ;
     RECT  24.304 8.688 24.977 13.656 ;
     RECT  25.505 23.904 25.589 23.928 ;
     RECT  24.304 3.12 25.621 3.144 ;
     RECT  24.304 4.128 25.621 4.248 ;
     RECT  24.659 21.408 25.621 21.432 ;
     RECT  25.649 0.096 25.733 0.12 ;
     RECT  25.621 21.408 26.593 22.248 ;
     RECT  25.621 3.12 26.953 4.248 ;
     RECT  26.593 21.408 27.059 22.344 ;
     RECT  26.953 2.784 27.173 4.248 ;
     RECT  27.173 3.12 27.241 4.248 ;
     RECT  27.241 3.12 27.325 4.536 ;
     RECT  24.977 8.688 27.529 13.512 ;
     RECT  27.601 1.728 27.685 1.752 ;
     RECT  27.445 24.48 27.713 24.504 ;
     RECT  27.325 3.12 29.408 4.248 ;
     RECT  27.529 8.688 29.408 13.56 ;
     RECT  24.304 16.032 29.408 16.056 ;
     RECT  27.059 22.32 29.408 22.344 ;
     RECT  29.365 23.904 29.408 23.928 ;
     RECT  29.408 2.148 29.512 23.928 ;
     RECT  29.512 2.418 29.585 23.928 ;
     RECT  29.545 0.096 29.629 0.12 ;
     RECT  29.585 2.418 29.704 23.502 ;
     RECT  29.704 3.12 30.769 4.248 ;
     RECT  29.704 8.688 30.845 13.656 ;
     RECT  30.769 3.12 31.025 4.296 ;
     RECT  31.265 23.904 31.349 23.928 ;
     RECT  29.704 22.32 31.421 22.344 ;
     RECT  31.417 0.096 31.523 0.12 ;
     RECT  31.025 3.12 33.325 4.248 ;
     RECT  33.433 0.096 33.517 0.12 ;
     RECT  33.205 23.904 33.617 23.928 ;
     RECT  33.325 3.024 33.689 4.248 ;
     RECT  32.389 22.224 34.693 22.248 ;
     RECT  33.689 3.12 34.808 4.248 ;
     RECT  30.845 8.688 34.808 13.608 ;
     RECT  29.704 16.032 34.808 16.056 ;
     RECT  34.693 21.936 34.808 22.248 ;
     RECT  34.808 2.148 34.912 23.772 ;
     RECT  34.912 2.418 35.104 23.502 ;
     RECT  35.104 3.12 35.219 4.68 ;
     RECT  35.161 25.056 35.245 25.08 ;
     RECT  35.104 21.792 35.345 21.96 ;
     RECT  35.333 1.152 35.417 1.176 ;
     RECT  35.345 21.792 36.961 21.816 ;
     RECT  35.219 3.12 37.141 4.44 ;
     RECT  37.249 0.096 37.333 0.12 ;
     RECT  37.141 3.12 37.357 4.776 ;
     RECT  37.093 25.776 37.397 25.8 ;
     RECT  37.357 3.12 37.537 4.872 ;
     RECT  36.961 21.792 37.577 22.632 ;
     RECT  35.104 8.688 37.58 13.608 ;
     RECT  37.58 8.688 37.667 13.656 ;
     RECT  37.537 3.12 37.789 4.968 ;
     RECT  37.789 3.12 38.149 5.832 ;
     RECT  38.149 3.12 38.185 6.072 ;
     RECT  38.185 3.024 38.257 6.072 ;
     RECT  38.257 3.024 38.549 6.168 ;
     RECT  37.577 21.792 38.684 22.008 ;
     RECT  38.684 21.408 38.771 22.008 ;
     RECT  38.549 3.12 39.125 6.168 ;
     RECT  39.013 24.48 39.161 24.504 ;
     RECT  39.221 0.096 39.305 0.12 ;
     RECT  39.125 6 39.409 6.168 ;
     RECT  39.125 3.12 39.589 4.776 ;
     RECT  39.589 3.072 39.625 4.776 ;
     RECT  38.771 21.888 39.733 22.008 ;
     RECT  39.625 2.88 39.805 4.776 ;
     RECT  39.409 6 40.165 6.792 ;
     RECT  39.805 2.832 40.208 4.776 ;
     RECT  40.165 5.76 40.208 6.792 ;
     RECT  37.667 8.688 40.208 10.632 ;
     RECT  37.667 11.664 40.208 13.464 ;
     RECT  35.104 16.032 40.208 16.056 ;
     RECT  39.733 21.888 40.208 22.056 ;
     RECT  39.877 23.28 40.208 23.304 ;
     RECT  40.208 2.148 40.312 23.772 ;
     RECT  40.312 2.418 40.504 23.502 ;
     RECT  40.504 2.88 40.781 6.024 ;
     RECT  40.504 21.648 40.889 22.056 ;
     RECT  40.889 21.648 40.961 22.008 ;
     RECT  40.885 24.48 40.979 24.504 ;
     RECT  40.781 2.88 41.285 5.496 ;
     RECT  41.285 3.408 41.465 5.496 ;
     RECT  41.173 0.096 41.537 0.12 ;
     RECT  41.465 3.408 41.537 5.448 ;
     RECT  41.537 3.408 41.573 4.248 ;
     RECT  41.537 5.28 41.573 5.448 ;
     RECT  41.573 5.424 41.717 5.448 ;
     RECT  43.081 0.096 43.187 0.12 ;
     RECT  42.853 24.48 43.265 24.504 ;
     RECT  41.573 3.648 43.549 4.248 ;
     RECT  40.961 21.648 43.589 21.672 ;
     RECT  43.729 22.032 43.981 22.2 ;
     RECT  44.773 24.48 44.993 24.504 ;
     RECT  44.989 0.096 45.107 0.12 ;
     RECT  43.549 3.408 45.608 4.248 ;
     RECT  40.504 8.688 45.608 10.632 ;
     RECT  40.504 11.664 45.608 13.464 ;
     RECT  40.504 16.032 45.608 16.056 ;
     RECT  43.981 22.032 45.608 22.44 ;
     RECT  45.608 2.148 45.712 23.772 ;
     RECT  45.712 2.418 45.904 23.502 ;
     RECT  45.904 3.408 46.451 4.44 ;
     RECT  46.673 25.056 46.757 25.08 ;
     RECT  46.933 0.096 47.027 0.12 ;
     RECT  45.904 21.648 47.365 21.672 ;
     RECT  47.365 21.648 47.405 22.2 ;
     RECT  46.451 3.408 47.837 4.248 ;
     RECT  45.904 11.664 48.085 13.464 ;
     RECT  47.405 22.176 48.485 22.2 ;
     RECT  48.581 23.904 48.665 23.928 ;
     RECT  48.949 0.096 49.033 0.12 ;
     RECT  50.821 0.096 50.915 0.12 ;
     RECT  47.837 3.6 51.008 4.248 ;
     RECT  45.904 8.688 51.008 10.632 ;
     RECT  48.085 11.664 51.008 13.608 ;
     RECT  45.904 16.032 51.008 16.056 ;
     RECT  50.497 21.984 51.008 22.008 ;
     RECT  50.533 23.376 51.008 23.4 ;
     RECT  51.008 2.148 51.112 23.772 ;
     RECT  51.112 2.418 51.304 23.502 ;
     RECT  51.304 21.648 51.553 22.104 ;
     RECT  51.553 21.984 52.265 22.104 ;
     RECT  52.453 24.48 52.661 24.504 ;
     RECT  52.765 0.096 52.849 0.12 ;
     RECT  52.265 22.08 53.057 22.104 ;
     RECT  51.304 3.6 53.269 4.248 ;
     RECT  51.304 11.664 53.315 13.608 ;
     RECT  53.269 3.6 53.353 5.112 ;
     RECT  53.353 3.6 53.521 4.248 ;
     RECT  54.421 23.376 54.713 23.4 ;
     RECT  51.304 8.688 54.749 10.632 ;
     RECT  54.709 0.096 54.803 0.12 ;
     RECT  53.485 21.648 56.401 21.672 ;
     RECT  56.321 23.904 56.405 23.928 ;
     RECT  53.521 3.552 56.408 4.248 ;
     RECT  53.269 6.24 56.408 6.264 ;
     RECT  54.749 8.784 56.408 10.632 ;
     RECT  53.315 11.664 56.408 13.368 ;
     RECT  51.304 16.032 56.408 16.056 ;
     RECT  56.401 21.648 56.408 21.816 ;
     RECT  56.408 2.148 56.512 23.772 ;
     RECT  56.512 2.418 56.704 23.502 ;
     RECT  56.677 0.528 56.765 0.552 ;
     RECT  56.704 4.128 58.057 4.248 ;
     RECT  58.057 4.032 58.093 4.248 ;
     RECT  56.704 21.792 58.172 21.816 ;
     RECT  58.172 21.552 58.213 21.816 ;
     RECT  58.213 21.552 58.259 22.776 ;
     RECT  58.259 22.752 58.261 22.776 ;
     RECT  58.604 0.096 58.691 0.12 ;
     RECT  58.093 4.032 58.693 4.536 ;
     RECT  58.261 22.752 58.709 23.4 ;
     RECT  58.693 3.888 58.988 4.536 ;
     RECT  58.988 3.408 59.075 4.536 ;
     RECT  59.075 3.888 59.285 4.536 ;
     RECT  56.704 8.688 59.509 10.632 ;
     RECT  56.704 11.664 59.509 13.368 ;
     RECT  59.509 8.688 59.596 13.368 ;
     RECT  58.709 22.752 60.073 22.776 ;
     RECT  60.073 22.176 60.113 22.776 ;
     RECT  60.181 23.904 60.437 23.928 ;
     RECT  59.596 11.616 60.653 13.368 ;
     RECT  60.565 0.096 60.869 0.12 ;
     RECT  60.113 22.176 60.973 22.2 ;
     RECT  59.285 3.888 61.808 4.248 ;
     RECT  56.704 6.24 61.808 6.264 ;
     RECT  59.596 8.688 61.808 10.632 ;
     RECT  60.653 11.664 61.808 13.368 ;
     RECT  56.704 16.032 61.808 16.056 ;
     RECT  60.973 22.032 61.808 22.2 ;
     RECT  61.808 2.148 61.912 23.772 ;
     RECT  61.912 2.418 61.945 23.772 ;
     RECT  61.945 2.418 62.104 23.928 ;
     RECT  62.104 23.904 62.147 23.928 ;
     RECT  62.104 21.936 62.201 22.056 ;
     RECT  62.485 0.096 62.569 0.12 ;
     RECT  62.104 3.888 63.209 4.536 ;
     RECT  63.209 3.888 63.565 4.44 ;
     RECT  64.021 24.48 64.109 24.504 ;
     RECT  64.453 0.096 64.541 0.12 ;
     RECT  63.565 3.6 64.973 4.44 ;
     RECT  62.201 21.936 65.189 21.96 ;
     RECT  65.941 23.904 66.125 23.928 ;
     RECT  62.104 11.664 66.161 13.56 ;
     RECT  66.365 0.096 66.449 0.12 ;
     RECT  64.973 3.6 66.812 4.248 ;
     RECT  66.812 3.6 67.208 4.632 ;
     RECT  62.104 6.24 67.208 6.264 ;
     RECT  62.104 8.688 67.208 10.632 ;
     RECT  66.161 11.664 67.208 13.368 ;
     RECT  62.104 16.032 67.208 16.056 ;
     RECT  67.208 2.148 67.312 23.772 ;
     RECT  67.312 2.418 67.504 23.502 ;
     RECT  67.861 24.48 68.105 24.504 ;
     RECT  68.245 0.096 68.339 0.12 ;
     RECT  67.504 3.6 69.613 4.248 ;
     RECT  67.504 21.792 69.74 21.816 ;
     RECT  69.74 21.552 69.781 21.816 ;
     RECT  69.781 21.552 69.827 22.488 ;
     RECT  69.781 24.48 69.941 24.504 ;
     RECT  67.504 6.24 70.076 6.264 ;
     RECT  69.613 3.6 70.117 4.536 ;
     RECT  70.076 6.24 70.163 6.312 ;
     RECT  70.261 0.096 70.345 0.12 ;
     RECT  70.117 3.6 70.513 5.16 ;
     RECT  70.163 6.24 70.513 6.264 ;
     RECT  70.513 3.6 71.129 6.264 ;
     RECT  69.827 22.464 71.273 22.488 ;
     RECT  71.729 23.904 71.813 23.928 ;
     RECT  67.504 11.664 71.9 13.368 ;
     RECT  71.701 22.416 71.941 22.44 ;
     RECT  71.129 3.6 72.277 5.16 ;
     RECT  71.129 6.192 72.277 6.264 ;
     RECT  72.181 0.096 72.281 0.12 ;
     RECT  72.277 3.6 72.608 6.264 ;
     RECT  67.504 8.688 72.608 10.632 ;
     RECT  71.9 11.664 72.608 14.04 ;
     RECT  67.504 16.032 72.608 16.056 ;
     RECT  71.941 21.888 72.608 22.44 ;
     RECT  72.608 2.148 72.712 23.772 ;
     RECT  72.712 2.418 72.904 23.502 ;
     RECT  72.904 4.128 72.965 4.248 ;
     RECT  72.904 22.032 73.577 22.2 ;
     RECT  72.904 5.28 73.829 6.744 ;
     RECT  73.669 24.48 73.829 24.504 ;
     RECT  72.965 4.224 74.053 4.248 ;
     RECT  73.829 5.28 74.053 6.408 ;
     RECT  74.053 4.224 74.099 6.408 ;
     RECT  74.077 0.096 74.161 0.12 ;
     RECT  74.099 4.224 74.297 5.304 ;
     RECT  74.099 6.288 74.693 6.408 ;
     RECT  74.297 4.224 75.193 4.248 ;
     RECT  74.693 6.384 75.193 6.408 ;
     RECT  72.904 11.664 75.593 13.368 ;
     RECT  75.337 23.712 75.635 23.736 ;
     RECT  75.193 3.552 75.733 4.248 ;
     RECT  75.733 3.408 75.817 4.248 ;
     RECT  74.297 5.28 76.093 5.304 ;
     RECT  75.193 6.384 76.093 6.888 ;
     RECT  75.841 1.728 76.115 1.752 ;
     RECT  76.093 5.28 76.403 6.888 ;
     RECT  75.593 11.664 76.403 13.272 ;
     RECT  73.577 22.176 76.633 22.2 ;
     RECT  75.817 3.552 76.741 4.248 ;
     RECT  76.403 5.28 76.741 6.408 ;
     RECT  76.741 3.552 76.853 6.408 ;
     RECT  76.853 5.28 76.883 6.408 ;
     RECT  77.281 25.104 77.555 25.128 ;
     RECT  76.633 21.936 77.557 22.2 ;
     RECT  77.785 1.728 78.008 1.752 ;
     RECT  76.853 3.552 78.008 4.248 ;
     RECT  76.883 5.28 78.008 6.312 ;
     RECT  72.904 8.688 78.008 10.632 ;
     RECT  76.403 11.664 78.008 12.504 ;
     RECT  72.904 16.032 78.008 16.056 ;
     RECT  77.557 21.936 78.008 22.248 ;
     RECT  78.008 1.728 78.035 23.772 ;
     RECT  78.035 2.148 78.112 23.772 ;
     RECT  78.112 2.418 78.304 23.502 ;
     RECT  78.304 21.408 79.235 22.488 ;
     RECT  79.189 25.776 79.475 25.8 ;
     RECT  79.945 0.576 80.029 0.6 ;
     RECT  78.304 3.6 80.093 4.248 ;
     RECT  79.235 21.408 80.809 21.432 ;
     RECT  79.235 22.464 80.809 22.488 ;
     RECT  80.809 21.408 80.849 22.488 ;
     RECT  81.133 23.904 81.395 23.928 ;
     RECT  81.673 1.728 81.923 1.752 ;
     RECT  80.093 3.936 82.069 4.248 ;
     RECT  80.849 21.408 82.165 22.2 ;
     RECT  82.069 3.6 82.969 4.248 ;
     RECT  83.005 25.104 83.315 25.128 ;
     RECT  82.969 3.408 83.408 4.248 ;
     RECT  78.304 5.28 83.408 6.312 ;
     RECT  78.304 8.688 83.408 10.632 ;
     RECT  78.304 11.664 83.408 12.504 ;
     RECT  78.304 16.032 83.408 16.056 ;
     RECT  82.165 21.408 83.408 22.824 ;
     RECT  83.408 2.148 83.512 23.772 ;
     RECT  83.512 2.418 83.704 23.502 ;
     RECT  83.797 0.576 83.881 0.6 ;
     RECT  83.704 5.28 84.371 6.552 ;
     RECT  83.704 16.032 85.021 16.056 ;
     RECT  83.704 21.408 85.201 21.432 ;
     RECT  83.704 22.464 85.201 22.488 ;
     RECT  84.949 23.712 85.235 23.736 ;
     RECT  85.021 16.032 85.529 16.296 ;
     RECT  85.561 1.728 85.811 1.752 ;
     RECT  83.704 8.688 86.681 10.632 ;
     RECT  86.893 23.712 87.155 23.736 ;
     RECT  87.116 20.208 87.203 20.232 ;
     RECT  83.704 3.408 87.725 4.248 ;
     RECT  87.433 1.728 87.731 1.752 ;
     RECT  87.725 3.696 88.808 4.248 ;
     RECT  84.371 5.28 88.808 5.304 ;
     RECT  84.371 6.288 88.808 6.552 ;
     RECT  86.681 8.736 88.808 10.632 ;
     RECT  83.704 11.712 88.808 12.504 ;
     RECT  85.529 16.272 88.808 16.296 ;
     RECT  85.201 21.408 88.808 22.488 ;
     RECT  88.808 2.148 88.912 23.772 ;
     RECT  88.912 2.418 89.104 23.502 ;
     RECT  88.765 25.104 89.123 25.128 ;
     RECT  89.104 6.288 89.507 6.552 ;
     RECT  89.104 21.36 89.525 22.488 ;
     RECT  89.521 0.576 89.651 0.6 ;
     RECT  89.525 21.36 90.637 21.432 ;
     RECT  89.104 4.08 90.716 4.248 ;
     RECT  90.716 3.312 90.803 4.248 ;
     RECT  90.781 23.712 91.043 23.736 ;
     RECT  90.637 21.072 91.139 21.432 ;
     RECT  89.525 22.464 91.18 22.488 ;
     RECT  91.321 1.728 91.619 1.752 ;
     RECT  91.139 21.36 92.437 21.432 ;
     RECT  92.437 20.976 92.524 21.432 ;
     RECT  89.104 8.736 92.833 10.632 ;
     RECT  92.689 25.776 92.963 25.8 ;
     RECT  92.524 21.36 93.053 21.432 ;
     RECT  92.833 8.496 93.157 10.632 ;
     RECT  89.507 6.528 93.203 6.552 ;
     RECT  93.481 0.576 93.565 0.6 ;
     RECT  93.053 21.408 93.589 21.432 ;
     RECT  90.803 4.08 93.625 4.248 ;
     RECT  93.589 21.408 93.985 22.152 ;
     RECT  93.157 7.872 94.049 10.632 ;
     RECT  93.625 3.84 94.208 4.248 ;
     RECT  89.104 5.28 94.208 5.304 ;
     RECT  94.049 7.584 94.208 10.632 ;
     RECT  89.104 11.712 94.208 12.504 ;
     RECT  91.357 14.64 94.208 14.664 ;
     RECT  89.104 16.272 94.208 16.296 ;
     RECT  93.985 21.408 94.208 22.248 ;
     RECT  94.208 2.148 94.312 23.772 ;
     RECT  94.312 2.418 94.504 23.772 ;
     RECT  94.633 23.904 94.883 23.928 ;
     RECT  95.281 1.728 95.507 1.752 ;
     RECT  94.504 7.872 95.708 10.632 ;
     RECT  95.708 7.632 95.795 10.632 ;
     RECT  94.504 21.408 96.001 22.248 ;
     RECT  96.001 20.832 96.365 22.248 ;
     RECT  95.795 8.736 96.565 10.632 ;
     RECT  94.504 11.712 96.565 12.504 ;
     RECT  94.504 14.64 96.611 14.664 ;
     RECT  96.505 23.712 96.803 23.736 ;
     RECT  97.153 1.728 97.427 1.752 ;
     RECT  96.365 20.832 97.477 22.152 ;
     RECT  97.477 20.832 97.523 22.824 ;
     RECT  94.504 16.272 97.769 16.296 ;
     RECT  97.523 22.128 97.913 22.824 ;
     RECT  98.161 15.792 98.417 15.816 ;
     RECT  98.449 25.104 98.723 25.128 ;
     RECT  99.169 0.576 99.347 0.6 ;
     RECT  94.504 3.84 99.385 4.248 ;
     RECT  99.385 3.696 99.608 4.248 ;
     RECT  94.504 5.28 99.608 5.304 ;
     RECT  96.565 8.736 99.608 12.504 ;
     RECT  98.557 15.168 99.608 15.192 ;
     RECT  97.523 20.832 99.608 20.856 ;
     RECT  97.913 22.272 99.608 22.776 ;
     RECT  99.608 2.148 99.712 23.772 ;
     RECT  99.712 2.418 99.904 23.772 ;
     RECT  99.904 3.696 100.613 4.248 ;
     RECT  100.357 23.904 100.643 23.928 ;
     RECT  99.904 8.736 101.113 12.504 ;
     RECT  101.041 1.728 101.315 1.752 ;
     RECT  101.113 8.448 101.459 12.504 ;
     RECT  101.459 8.448 101.605 10.2 ;
     RECT  100.613 3.696 101.653 4.2 ;
     RECT  101.605 8.256 101.653 10.2 ;
     RECT  101.653 7.968 101.737 10.2 ;
     RECT  101.653 3.696 102.373 4.248 ;
     RECT  101.737 8.448 102.517 10.2 ;
     RECT  101.459 11.712 102.517 12.504 ;
     RECT  99.904 21.072 102.557 21.096 ;
     RECT  102.301 23.904 102.563 23.928 ;
     RECT  102.373 3.408 103.093 4.248 ;
     RECT  99.904 5.28 103.093 5.304 ;
     RECT  102.517 8.448 103.093 12.504 ;
     RECT  103.157 1.728 103.241 1.752 ;
     RECT  103.093 3.408 103.313 5.304 ;
     RECT  99.904 22.272 103.597 22.296 ;
     RECT  103.597 22.176 103.637 22.296 ;
     RECT  103.313 3.792 103.669 5.304 ;
     RECT  103.093 8.4 103.717 12.504 ;
     RECT  104.173 25.104 104.483 25.128 ;
     RECT  102.949 21.12 104.497 21.144 ;
     RECT  103.637 22.176 104.497 22.2 ;
     RECT  104.893 1.728 105.008 1.752 ;
     RECT  103.669 3.792 105.008 5.736 ;
     RECT  103.717 7.392 105.008 12.504 ;
     RECT  104.497 21.12 105.008 22.2 ;
     RECT  105.008 1.728 105.112 23.772 ;
     RECT  105.112 1.728 105.155 23.502 ;
     RECT  105.155 2.418 105.304 23.502 ;
     RECT  105.304 7.872 105.329 10.68 ;
     RECT  105.304 21.12 105.581 22.248 ;
     RECT  105.304 11.76 105.797 13.032 ;
     RECT  105.797 11.76 106.157 12.504 ;
     RECT  105.304 4.176 106.297 5.304 ;
     RECT  105.329 7.872 106.297 10.2 ;
     RECT  106.117 23.712 106.403 23.736 ;
     RECT  106.297 3.936 106.837 5.304 ;
     RECT  106.837 1.728 107.123 1.752 ;
     RECT  106.297 7.872 107.125 10.872 ;
     RECT  107.125 7.392 107.597 10.872 ;
     RECT  106.157 11.904 107.948 12.504 ;
     RECT  106.837 3.936 108.025 5.736 ;
     RECT  107.948 11.904 108.035 12.984 ;
     RECT  108.061 25.104 108.371 25.128 ;
     RECT  107.597 7.392 108.38 10.728 ;
     RECT  105.581 21.12 108.421 21.144 ;
     RECT  105.581 22.224 108.421 22.248 ;
     RECT  108.38 6.816 108.467 10.728 ;
     RECT  108.467 7.104 108.893 10.728 ;
     RECT  108.889 0.576 109.043 0.6 ;
     RECT  108.893 8.352 109.073 10.728 ;
     RECT  109.073 8.736 109.429 10.728 ;
     RECT  108.025 3.312 110.408 5.736 ;
     RECT  108.893 7.104 110.408 7.128 ;
     RECT  109.429 8.736 110.408 10.92 ;
     RECT  108.035 12.384 110.408 12.504 ;
     RECT  108.421 21.12 110.408 22.248 ;
     RECT  110.005 23.712 110.408 23.736 ;
     RECT  110.408 2.148 110.512 23.772 ;
     RECT  110.512 2.148 110.653 23.502 ;
     RECT  110.653 1.728 110.704 23.502 ;
     RECT  110.704 2.88 110.837 5.304 ;
     RECT  110.704 1.728 110.963 1.752 ;
     RECT  110.704 7.104 111.413 9.336 ;
     RECT  111.413 7.2 111.683 9.336 ;
     RECT  111.949 23.712 112.211 23.736 ;
     RECT  110.704 21.696 112.268 22.392 ;
     RECT  112.268 21.696 112.355 22.44 ;
     RECT  112.885 0.576 112.969 0.6 ;
     RECT  111.683 7.2 113.069 7.224 ;
     RECT  112.355 21.696 113.941 22.056 ;
     RECT  113.941 21.696 113.987 22.488 ;
     RECT  113.987 21.936 114.028 22.488 ;
     RECT  110.837 3.312 114.109 5.304 ;
     RECT  113.857 25.776 114.131 25.8 ;
     RECT  114.028 21.936 114.365 22.056 ;
     RECT  114.109 2.976 114.689 5.304 ;
     RECT  114.793 0.576 114.877 0.6 ;
     RECT  114.689 3.312 115.808 5.304 ;
     RECT  111.683 8.688 115.808 9.336 ;
     RECT  114.365 22.032 115.808 22.056 ;
     RECT  115.808 2.148 115.981 23.772 ;
     RECT  115.981 2.148 116.065 23.928 ;
     RECT  116.065 2.148 116.104 23.502 ;
     RECT  116.557 1.728 116.819 1.752 ;
     RECT  117.673 23.712 117.971 23.736 ;
     RECT  116.104 22.032 118.213 22.056 ;
     RECT  118.213 21.936 118.253 22.056 ;
     RECT  118.573 0.576 118.739 0.6 ;
     RECT  118.253 21.936 119.797 21.96 ;
     RECT  119.797 21.936 119.837 22.056 ;
     RECT  119.617 25.104 119.891 25.128 ;
     RECT  120.373 1.728 120.659 1.752 ;
     RECT  116.104 3.312 121.208 5.304 ;
     RECT  116.104 8.688 121.208 9.336 ;
     RECT  119.837 22.032 121.208 22.056 ;
     RECT  121.208 2.148 121.312 23.772 ;
     RECT  121.312 2.418 121.504 23.772 ;
     RECT  121.525 23.904 121.811 23.928 ;
     RECT  121.504 3.312 122.533 5.304 ;
     RECT  121.504 22.032 122.605 22.056 ;
     RECT  122.605 22.032 122.645 22.2 ;
     RECT  122.569 0.576 122.653 0.6 ;
     RECT  122.533 3.12 122.681 5.304 ;
     RECT  123.469 25.776 123.731 25.8 ;
     RECT  124.261 1.728 124.547 1.752 ;
     RECT  122.645 22.176 125.417 22.2 ;
     RECT  125.125 25.104 125.699 25.128 ;
     RECT  122.681 3.312 126.457 5.304 ;
     RECT  126.205 1.728 126.467 1.752 ;
     RECT  126.457 2.88 126.608 5.304 ;
     RECT  121.504 8.688 126.608 9.336 ;
     RECT  125.809 22.032 126.608 22.056 ;
     RECT  126.608 2.148 126.712 23.772 ;
     RECT  126.712 2.418 126.904 23.772 ;
     RECT  127.357 23.904 127.619 23.928 ;
     RECT  128.365 0.576 128.449 0.6 ;
     RECT  126.904 21.648 128.477 22.2 ;
     RECT  128.477 21.648 129.517 21.672 ;
     RECT  129.193 25.776 129.539 25.8 ;
     RECT  129.517 21.648 129.557 22.2 ;
     RECT  130.093 1.728 130.355 1.752 ;
     RECT  130.921 25.776 131.459 25.8 ;
     RECT  126.904 3.312 132.008 5.304 ;
     RECT  126.904 8.688 132.008 9.336 ;
     RECT  129.557 22.176 132.008 22.2 ;
     RECT  132.008 2.148 132.112 23.772 ;
     RECT  132.112 2.418 132.304 23.772 ;
     RECT  132.253 0.576 132.337 0.6 ;
     RECT  132.865 23.904 133.379 23.928 ;
     RECT  132.304 22.176 133.769 22.2 ;
     RECT  133.981 1.728 134.243 1.752 ;
     RECT  135.025 25.776 135.299 25.8 ;
     RECT  135.889 1.728 136.163 1.752 ;
     RECT  137.077 23.904 137.219 23.928 ;
     RECT  132.304 3.312 137.408 5.304 ;
     RECT  132.304 8.688 137.408 9.336 ;
     RECT  133.981 21.936 137.408 21.96 ;
     RECT  137.408 2.148 137.512 23.772 ;
     RECT  137.512 2.418 137.704 23.502 ;
     RECT  138.013 0.576 138.131 0.6 ;
     RECT  138.841 25.104 139.139 25.128 ;
     RECT  139.777 1.728 140.051 1.752 ;
     RECT  137.704 22.176 140.677 22.2 ;
     RECT  137.704 8.688 140.969 9.336 ;
     RECT  140.785 23.712 141.059 23.736 ;
     RECT  141.893 0.576 141.977 0.6 ;
     RECT  140.677 22.032 142.045 22.2 ;
     RECT  140.969 8.688 142.693 8.76 ;
     RECT  137.704 3.312 142.808 5.304 ;
     RECT  142.693 8.688 142.808 8.808 ;
     RECT  142.045 21.696 142.808 22.2 ;
     RECT  142.808 2.148 142.94 23.772 ;
     RECT  142.94 2.148 143.027 23.88 ;
     RECT  143.027 2.148 143.104 23.502 ;
     RECT  143.104 21.696 143.561 22.056 ;
     RECT  143.104 3.312 143.669 5.304 ;
     RECT  143.665 1.728 143.939 1.752 ;
     RECT  143.669 3.408 144.029 5.304 ;
     RECT  143.104 14.256 144.229 14.28 ;
     RECT  144.229 13.056 144.275 14.28 ;
     RECT  144.275 13.056 144.316 13.848 ;
     RECT  143.104 8.736 144.428 8.808 ;
     RECT  144.277 15.984 144.469 16.008 ;
     RECT  144.428 8.736 144.515 8.904 ;
     RECT  143.561 22.032 144.515 22.056 ;
     RECT  144.673 25.104 144.947 25.128 ;
     RECT  144.029 3.408 145.001 3.432 ;
     RECT  143.104 11.28 145.58 11.304 ;
     RECT  145.58 10.848 145.609 11.304 ;
     RECT  145.609 10.848 145.667 12.024 ;
     RECT  145.667 12 145.693 12.024 ;
     RECT  145.609 1.728 145.859 1.752 ;
     RECT  144.316 13.824 145.861 13.848 ;
     RECT  144.469 15.984 145.865 16.536 ;
     RECT  145.861 13.632 145.907 13.848 ;
     RECT  144.029 4.416 146.113 5.304 ;
     RECT  145.825 21.264 146.329 21.288 ;
     RECT  145.213 22.608 146.329 22.776 ;
     RECT  145.907 13.632 146.333 13.656 ;
     RECT  146.329 21.264 146.341 22.776 ;
     RECT  144.515 8.736 146.405 8.808 ;
     RECT  146.341 21.264 146.413 23.016 ;
     RECT  146.413 22.752 146.509 23.016 ;
     RECT  145.865 15.984 146.513 16.008 ;
     RECT  145.789 2.736 146.585 2.76 ;
     RECT  146.113 3.936 146.833 5.304 ;
     RECT  145.833 14.88 146.837 14.904 ;
     RECT  146.509 22.752 146.867 23.736 ;
     RECT  146.413 21.264 146.915 21.768 ;
     RECT  146.833 2.832 146.945 5.304 ;
     RECT  146.185 10.8 147.089 10.824 ;
     RECT  146.869 25.104 147.265 25.128 ;
     RECT  147.725 1.728 147.809 1.752 ;
     RECT  147.265 24.288 147.809 25.128 ;
     RECT  147.337 21.12 147.949 21.144 ;
     RECT  146.867 22.752 147.949 23.016 ;
     RECT  146.945 2.832 148.208 3.288 ;
     RECT  146.945 4.272 148.208 5.304 ;
     RECT  146.405 8.736 148.208 8.76 ;
     RECT  147.949 21.12 148.208 23.016 ;
     RECT  147.809 24.288 148.208 24.312 ;
     RECT  148.208 2.148 148.504 24.312 ;
     RECT  148.504 19.776 148.925 24.312 ;
     RECT  148.925 24.288 149.029 24.312 ;
     RECT  148.504 4.896 149.497 6.168 ;
     RECT  149.029 1.584 149.66 1.608 ;
     RECT  149.66 1.584 149.857 2.28 ;
     RECT  148.504 3.264 149.857 3.672 ;
     RECT  149.497 4.896 149.857 6.984 ;
     RECT  148.504 8.208 149.857 8.232 ;
     RECT  148.504 9.456 149.857 10.296 ;
     RECT  148.504 17.28 149.857 17.304 ;
     RECT  148.925 19.776 149.857 23.064 ;
     RECT  149.857 1.2 149.893 10.296 ;
     RECT  149.857 18.528 149.893 23.064 ;
     RECT  149.029 24.288 149.893 24.744 ;
     RECT  149.893 1.2 150.433 11.112 ;
     RECT  149.857 12.336 150.433 12.36 ;
     RECT  149.857 13.968 150.433 14.424 ;
     RECT  149.857 16.032 150.433 17.304 ;
     RECT  149.893 18.528 150.433 24.744 ;
     RECT  150.433 1.2 151.164 24.744 ;
    LAYER M5 ;
     RECT  6.336 0.016 6.36 0.131 ;
     RECT  10.176 0.016 10.2 0.131 ;
     RECT  12.144 0.016 12.168 0.131 ;
     RECT  14.064 0.016 14.088 0.131 ;
     RECT  15.984 0.016 16.008 0.131 ;
     RECT  17.952 0.016 17.976 0.131 ;
     RECT  21.84 0.016 21.864 0.131 ;
     RECT  25.68 0.016 25.704 0.131 ;
     RECT  29.568 0.016 29.592 0.131 ;
     RECT  31.488 0.016 31.512 0.131 ;
     RECT  33.456 0.016 33.48 0.131 ;
     RECT  37.296 0.016 37.32 0.131 ;
     RECT  39.264 0.016 39.288 0.131 ;
     RECT  41.184 0.016 41.208 0.131 ;
     RECT  43.152 0.016 43.176 0.131 ;
     RECT  45.072 0.016 45.096 0.131 ;
     RECT  46.992 0.016 47.016 0.131 ;
     RECT  48.96 0.016 48.984 0.131 ;
     RECT  50.88 0.016 50.904 0.131 ;
     RECT  52.8 0.016 52.824 0.131 ;
     RECT  54.768 0.016 54.792 0.131 ;
     RECT  58.656 0.016 58.68 0.131 ;
     RECT  60.576 0.016 60.6 0.131 ;
     RECT  62.496 0.016 62.52 0.131 ;
     RECT  64.464 0.016 64.488 0.131 ;
     RECT  66.384 0.016 66.408 0.131 ;
     RECT  68.304 0.016 68.328 0.131 ;
     RECT  70.272 0.016 70.296 0.131 ;
     RECT  72.192 0.016 72.216 0.131 ;
     RECT  74.112 0.016 74.136 0.131 ;
     RECT  56.688 0.016 56.712 0.563 ;
     RECT  79.968 0.016 79.992 0.611 ;
     RECT  83.808 0.016 83.832 0.611 ;
     RECT  89.616 0.016 89.64 0.611 ;
     RECT  93.504 0.016 93.528 0.611 ;
     RECT  99.312 0.016 99.336 0.611 ;
     RECT  109.008 0.016 109.032 0.611 ;
     RECT  112.896 0.016 112.92 0.611 ;
     RECT  114.816 0.016 114.84 0.611 ;
     RECT  118.704 0.016 118.728 0.611 ;
     RECT  122.592 0.016 122.616 0.611 ;
     RECT  128.4 0.016 128.424 0.611 ;
     RECT  132.288 0.016 132.312 0.611 ;
     RECT  138.096 0.016 138.12 0.611 ;
     RECT  141.936 0.016 141.96 0.611 ;
     RECT  2.448 0.016 2.472 0.851 ;
     RECT  35.376 0.016 35.4 1.187 ;
     RECT  4.368 0.016 4.392 1.763 ;
     RECT  8.256 0.016 8.28 1.763 ;
     RECT  19.872 0.016 19.896 1.763 ;
     RECT  23.76 0.016 23.784 1.763 ;
     RECT  27.648 0.016 27.672 1.763 ;
     RECT  76.08 0.016 76.104 1.763 ;
     RECT  81.888 0.016 81.912 1.763 ;
     RECT  85.776 0.016 85.8 1.763 ;
     RECT  87.696 0.016 87.72 1.763 ;
     RECT  91.584 0.016 91.608 1.763 ;
     RECT  95.472 0.016 95.496 1.763 ;
     RECT  97.392 0.016 97.416 1.763 ;
     RECT  101.28 0.016 101.304 1.763 ;
     RECT  103.2 0.016 103.224 1.763 ;
     RECT  107.088 0.016 107.112 1.763 ;
     RECT  110.928 0.016 110.952 1.763 ;
     RECT  116.784 0.016 116.808 1.763 ;
     RECT  120.624 0.016 120.648 1.763 ;
     RECT  124.512 0.016 124.536 1.763 ;
     RECT  126.432 0.016 126.456 1.763 ;
     RECT  130.32 0.016 130.344 1.763 ;
     RECT  134.208 0.016 134.232 1.763 ;
     RECT  136.128 0.016 136.152 1.763 ;
     RECT  140.016 0.016 140.04 1.763 ;
     RECT  143.904 0.016 143.928 1.763 ;
     RECT  145.824 0.016 145.848 1.763 ;
     RECT  147.744 0.016 147.768 1.763 ;
     RECT  2.304 2.053 2.328 2.137 ;
     RECT  78 0.016 78.024 2.137 ;
     RECT  105.12 0.016 105.144 2.137 ;
     RECT  2.304 2.137 2.52 2.151 ;
     RECT  13.2 2.137 13.32 2.151 ;
     RECT  18.6 2.137 18.72 2.151 ;
     RECT  24 2.137 24.12 2.151 ;
     RECT  29.4 2.137 29.52 2.151 ;
     RECT  34.8 2.137 34.92 2.151 ;
     RECT  40.2 2.137 40.32 2.151 ;
     RECT  45.6 2.137 45.72 2.151 ;
     RECT  51 2.137 51.12 2.151 ;
     RECT  56.4 2.137 56.52 2.151 ;
     RECT  61.8 2.137 61.92 2.151 ;
     RECT  67.2 2.137 67.32 2.151 ;
     RECT  72.6 2.137 72.72 2.151 ;
     RECT  78 2.137 78.12 2.151 ;
     RECT  83.4 2.137 83.52 2.151 ;
     RECT  88.8 2.137 88.92 2.151 ;
     RECT  94.2 2.137 94.32 2.151 ;
     RECT  99.6 2.137 99.72 2.151 ;
     RECT  105 2.137 105.144 2.151 ;
     RECT  121.2 2.137 121.32 2.151 ;
     RECT  126.6 2.137 126.72 2.151 ;
     RECT  132 2.137 132.12 2.151 ;
     RECT  137.4 2.137 137.52 2.151 ;
     RECT  142.8 2.137 142.92 2.151 ;
     RECT  148.2 2.137 148.32 2.151 ;
     RECT  2.304 2.151 2.712 2.245 ;
     RECT  149.712 0.016 149.736 2.291 ;
     RECT  0.144 1.381 0.168 2.339 ;
     RECT  2.304 2.245 3.192 3.397 ;
     RECT  4.272 2.821 4.536 3.397 ;
     RECT  45.6 2.151 45.912 3.397 ;
     RECT  121.2 2.151 121.512 3.397 ;
     RECT  137.4 2.151 137.712 3.397 ;
     RECT  34.8 2.151 35.112 3.589 ;
     RECT  67.2 2.151 67.512 3.589 ;
     RECT  78 2.151 78.312 3.589 ;
     RECT  110.4 2.137 110.712 3.685 ;
     RECT  103.2 3.397 103.224 3.781 ;
     RECT  105 2.151 105.312 3.781 ;
     RECT  59.04 3.397 59.064 3.877 ;
     RECT  58.704 3.877 59.064 3.923 ;
     RECT  137.184 3.397 137.712 3.923 ;
     RECT  83.4 2.151 83.712 3.925 ;
     RECT  78 3.589 78.408 3.971 ;
     RECT  58.704 3.923 58.728 4.067 ;
     RECT  16.08 3.157 16.104 4.115 ;
     RECT  90.768 3.301 90.792 4.115 ;
     RECT  103.2 3.781 105.312 4.115 ;
     RECT  110.208 3.685 110.712 4.115 ;
     RECT  124.656 3.397 124.68 4.115 ;
     RECT  94.2 2.151 94.512 4.117 ;
     RECT  2.304 3.397 4.536 4.165 ;
     RECT  45.6 3.397 46.44 4.451 ;
     RECT  2.304 4.165 5.4 4.595 ;
     RECT  121.2 3.397 121.656 4.595 ;
     RECT  66.864 3.589 67.512 4.643 ;
     RECT  34.8 3.589 35.208 4.691 ;
     RECT  104.16 4.115 105.312 4.931 ;
     RECT  2.4 4.595 3.048 5.171 ;
     RECT  2.4 5.171 2.808 5.219 ;
     RECT  114.576 4.693 114.6 5.219 ;
     RECT  4.272 4.595 5.4 5.317 ;
     RECT  4.272 5.317 5.736 5.747 ;
     RECT  83.4 3.925 83.928 5.749 ;
     RECT  4.464 5.747 5.736 5.795 ;
     RECT  74.064 5.029 74.088 6.035 ;
     RECT  75.744 3.397 75.768 6.277 ;
     RECT  76.752 4.789 76.776 6.277 ;
     RECT  88.8 2.151 89.112 6.277 ;
     RECT  70.128 5.125 70.152 6.323 ;
     RECT  75.744 6.277 76.872 6.419 ;
     RECT  94.08 4.117 94.512 6.517 ;
     RECT  83.4 5.749 84.36 6.563 ;
     RECT  75.744 6.419 76.392 6.899 ;
     RECT  108.432 6.805 108.456 7.139 ;
     RECT  5.376 5.795 5.736 7.381 ;
     RECT  7.8 2.137 8.112 7.381 ;
     RECT  110.304 4.115 110.712 7.765 ;
     RECT  5.376 7.381 8.112 8.003 ;
     RECT  101.664 4.213 101.688 8.003 ;
     RECT  107.136 7.381 107.16 8.147 ;
     RECT  103.728 7.381 103.752 8.483 ;
     RECT  93.168 6.517 94.512 8.485 ;
     RECT  92.928 8.485 94.512 8.531 ;
     RECT  142.8 2.151 143.112 8.677 ;
     RECT  110.304 7.765 111.672 8.723 ;
     RECT  142.704 8.677 143.112 8.819 ;
     RECT  5.376 8.003 6.072 8.965 ;
     RECT  92.928 8.531 92.952 9.155 ;
     RECT  95.76 7.621 95.784 9.251 ;
     RECT  4.608 8.965 6.072 9.493 ;
     RECT  7.8 8.003 8.112 9.493 ;
     RECT  101.616 8.245 101.64 9.637 ;
     RECT  101.424 9.637 101.64 9.875 ;
     RECT  75.744 6.899 75.768 9.877 ;
     RECT  75.264 9.877 75.768 9.923 ;
     RECT  75.264 9.923 75.288 10.163 ;
     RECT  88.8 6.277 89.496 10.307 ;
     RECT  101.424 9.875 101.448 11.171 ;
     RECT  4.608 9.493 8.112 11.365 ;
     RECT  4.608 11.365 8.232 11.653 ;
     RECT  105 4.931 105.312 11.749 ;
     RECT  145.632 10.837 145.656 12.035 ;
     RECT  96.576 10.213 96.6 12.229 ;
     RECT  94.08 8.531 94.512 12.275 ;
     RECT  25.872 11.941 25.896 12.467 ;
     RECT  27.264 4.501 27.288 12.469 ;
     RECT  27.024 12.469 27.288 12.515 ;
     RECT  4.512 11.653 8.232 12.563 ;
     RECT  59.52 11.509 59.544 12.563 ;
     RECT  108 8.341 108.024 12.995 ;
     RECT  105 11.749 105.432 13.043 ;
     RECT  144.48 4.645 144.504 13.045 ;
     RECT  4.512 12.563 8.112 13.187 ;
     RECT  76.368 12.469 76.392 13.283 ;
     RECT  2.4 5.219 2.712 13.333 ;
     RECT  51 2.151 51.312 13.573 ;
     RECT  53.28 5.077 53.304 13.619 ;
     RECT  72.6 2.151 72.912 14.005 ;
     RECT  4.608 13.187 8.112 14.291 ;
     RECT  144.24 13.045 144.504 14.291 ;
     RECT  96.576 12.229 97.512 14.675 ;
     RECT  145.872 13.621 145.896 14.915 ;
     RECT  4.608 14.291 6.072 18.851 ;
     RECT  1.488 13.333 2.712 19.141 ;
     RECT  4.608 18.851 4.776 19.333 ;
     RECT  1.488 19.141 3.432 19.669 ;
     RECT  4.416 19.333 4.776 19.669 ;
     RECT  1.488 19.669 4.776 20.195 ;
     RECT  7.44 14.291 8.112 20.437 ;
     RECT  1.488 20.195 4.632 20.579 ;
     RECT  110.304 8.723 110.712 21.109 ;
     RECT  1.488 20.579 4.44 21.203 ;
     RECT  6.048 18.851 6.072 21.395 ;
     RECT  92.448 20.965 92.472 21.395 ;
     RECT  24 2.151 24.312 21.397 ;
     RECT  27.024 12.515 27.048 21.443 ;
     RECT  83.4 6.563 83.712 21.637 ;
     RECT  51 13.573 51.528 21.683 ;
     RECT  109.968 21.109 110.712 21.685 ;
     RECT  109.968 21.685 111.336 21.731 ;
     RECT  88.8 10.307 89.112 21.733 ;
     RECT  7.44 20.437 8.376 21.923 ;
     RECT  34.8 4.691 35.112 21.925 ;
     RECT  78 3.971 78.312 21.925 ;
     RECT  37.632 10.117 37.656 21.971 ;
     RECT  38.736 21.397 38.76 22.019 ;
     RECT  110.304 21.731 111.336 22.067 ;
     RECT  144.48 14.291 144.504 22.067 ;
     RECT  148.2 2.151 148.512 22.117 ;
     RECT  24 21.397 24.648 22.163 ;
     RECT  82.608 21.637 83.712 22.165 ;
     RECT  146.88 21.733 146.904 22.165 ;
     RECT  1.488 21.203 4.2 22.213 ;
     RECT  148.2 22.117 148.632 22.213 ;
     RECT  1.488 22.213 4.776 22.259 ;
     RECT  34.704 21.925 35.112 22.259 ;
     RECT  77.568 21.925 79.224 22.259 ;
     RECT  88.176 21.733 89.112 22.259 ;
     RECT  110.4 22.067 111.336 22.259 ;
     RECT  71.952 14.005 72.912 22.451 ;
     RECT  112.32 21.685 112.344 22.451 ;
     RECT  69.792 21.541 69.816 22.499 ;
     RECT  78 22.259 79.224 22.499 ;
     RECT  87.168 20.197 87.192 22.499 ;
     RECT  91.104 21.061 91.128 22.499 ;
     RECT  113.952 21.685 113.976 22.499 ;
     RECT  148.2 22.213 149.352 22.691 ;
     RECT  15.984 22.165 16.008 22.787 ;
     RECT  58.224 21.541 58.248 22.787 ;
     RECT  1.488 22.259 2.856 22.835 ;
     RECT  3.936 22.259 4.776 22.835 ;
     RECT  7.44 21.923 8.328 22.835 ;
     RECT  82.176 22.165 83.712 22.835 ;
     RECT  97.488 14.675 97.512 22.835 ;
     RECT  3.936 22.835 4.2 22.883 ;
     RECT  7.8 22.835 8.328 22.883 ;
     RECT  146.352 22.165 146.904 23.027 ;
     RECT  51 21.683 51.312 23.365 ;
     RECT  3.936 22.883 3.96 23.411 ;
     RECT  110.4 22.259 110.712 23.701 ;
     RECT  148.2 22.691 148.632 23.701 ;
     RECT  7.8 22.883 8.112 23.769 ;
     RECT  18.6 2.151 18.912 23.769 ;
     RECT  24 22.163 24.312 23.769 ;
     RECT  29.4 2.151 29.712 23.769 ;
     RECT  34.8 22.259 35.112 23.769 ;
     RECT  45.6 4.451 45.912 23.769 ;
     RECT  50.544 23.365 51.312 23.769 ;
     RECT  56.4 2.151 56.712 23.769 ;
     RECT  78 22.499 78.312 23.769 ;
     RECT  83.4 22.835 83.712 23.769 ;
     RECT  88.8 22.259 89.112 23.769 ;
     RECT  105 13.043 105.312 23.769 ;
     RECT  110.256 23.701 110.712 23.769 ;
     RECT  115.8 2.137 116.112 23.769 ;
     RECT  132 2.151 132.312 23.769 ;
     RECT  137.4 3.923 137.712 23.769 ;
     RECT  142.8 8.819 143.112 23.769 ;
     RECT  1.488 22.835 2.808 23.783 ;
     RECT  7.8 23.769 7.92 23.783 ;
     RECT  13.2 2.151 13.512 23.783 ;
     RECT  18.6 23.769 18.72 23.783 ;
     RECT  24 23.769 24.12 23.783 ;
     RECT  29.4 23.769 29.52 23.783 ;
     RECT  34.8 23.769 34.92 23.783 ;
     RECT  40.2 2.151 40.512 23.783 ;
     RECT  45.6 23.769 45.72 23.783 ;
     RECT  50.544 23.769 51.12 23.783 ;
     RECT  56.4 23.769 56.52 23.783 ;
     RECT  61.8 2.151 62.112 23.783 ;
     RECT  67.2 4.643 67.512 23.783 ;
     RECT  72.6 22.451 72.912 23.783 ;
     RECT  78 23.769 78.12 23.783 ;
     RECT  83.4 23.769 83.52 23.783 ;
     RECT  88.8 23.769 88.92 23.783 ;
     RECT  94.2 12.275 94.512 23.783 ;
     RECT  99.6 2.151 99.912 23.783 ;
     RECT  105 23.769 105.12 23.783 ;
     RECT  110.256 23.769 110.52 23.783 ;
     RECT  115.8 23.769 116.04 23.783 ;
     RECT  121.2 4.595 121.512 23.783 ;
     RECT  126.6 2.151 126.912 23.783 ;
     RECT  132 23.769 132.12 23.783 ;
     RECT  137.4 23.769 137.52 23.783 ;
     RECT  142.8 23.769 143.016 23.783 ;
     RECT  148.2 23.701 148.776 23.783 ;
     RECT  0.144 21.781 0.168 24.563 ;
     RECT  146.832 23.027 146.904 25.139 ;
     RECT  1.488 23.783 1.512 25.765 ;
     RECT  2.784 23.783 2.808 25.765 ;
     RECT  1.488 25.765 2.808 25.811 ;
     RECT  1.488 25.811 2.472 25.859 ;
     RECT  2.448 25.859 2.472 25.872 ;
     RECT  4.368 23.893 4.392 25.872 ;
     RECT  6.288 25.045 6.312 25.872 ;
     RECT  8.208 25.765 8.232 25.872 ;
     RECT  10.128 23.941 10.152 25.872 ;
     RECT  12.048 24.469 12.072 25.872 ;
     RECT  13.968 23.893 13.992 25.872 ;
     RECT  15.888 24.469 15.912 25.872 ;
     RECT  17.856 23.941 17.88 25.872 ;
     RECT  19.776 25.765 19.8 25.872 ;
     RECT  21.696 24.469 21.72 25.872 ;
     RECT  23.616 24.469 23.64 25.872 ;
     RECT  25.536 23.893 25.56 25.872 ;
     RECT  27.456 24.469 27.48 25.872 ;
     RECT  29.376 23.893 29.4 25.872 ;
     RECT  31.296 23.893 31.32 25.872 ;
     RECT  33.216 23.893 33.24 25.872 ;
     RECT  35.184 25.045 35.208 25.872 ;
     RECT  37.104 25.765 37.128 25.872 ;
     RECT  39.024 24.469 39.048 25.872 ;
     RECT  40.944 24.469 40.968 25.872 ;
     RECT  42.864 24.469 42.888 25.872 ;
     RECT  44.784 24.469 44.808 25.872 ;
     RECT  46.704 25.045 46.728 25.872 ;
     RECT  48.624 23.893 48.648 25.872 ;
     RECT  50.544 23.783 50.568 25.872 ;
     RECT  52.464 24.469 52.488 25.872 ;
     RECT  54.432 23.365 54.456 25.872 ;
     RECT  56.352 23.893 56.376 25.872 ;
     RECT  58.272 23.365 58.296 25.872 ;
     RECT  60.192 23.893 60.216 25.872 ;
     RECT  62.112 23.893 62.136 25.872 ;
     RECT  64.032 24.469 64.056 25.872 ;
     RECT  65.952 23.893 65.976 25.872 ;
     RECT  67.872 24.469 67.896 25.872 ;
     RECT  69.792 24.469 69.816 25.872 ;
     RECT  71.76 23.893 71.784 25.872 ;
     RECT  73.68 24.469 73.704 25.872 ;
     RECT  75.6 23.701 75.624 25.872 ;
     RECT  77.52 25.093 77.544 25.872 ;
     RECT  79.44 25.765 79.464 25.872 ;
     RECT  81.36 23.893 81.384 25.872 ;
     RECT  83.28 25.093 83.304 25.872 ;
     RECT  85.2 23.701 85.224 25.872 ;
     RECT  87.12 23.701 87.144 25.872 ;
     RECT  89.088 25.093 89.112 25.872 ;
     RECT  91.008 23.701 91.032 25.872 ;
     RECT  92.928 25.765 92.952 25.872 ;
     RECT  94.848 23.893 94.872 25.872 ;
     RECT  96.768 23.701 96.792 25.872 ;
     RECT  98.688 25.093 98.712 25.872 ;
     RECT  100.608 23.893 100.632 25.872 ;
     RECT  102.528 23.893 102.552 25.872 ;
     RECT  104.448 25.093 104.472 25.872 ;
     RECT  106.368 23.701 106.392 25.872 ;
     RECT  108.336 25.093 108.36 25.872 ;
     RECT  110.256 23.783 110.28 25.872 ;
     RECT  112.176 23.701 112.2 25.872 ;
     RECT  114.096 25.765 114.12 25.872 ;
     RECT  116.016 23.783 116.04 25.872 ;
     RECT  117.936 23.701 117.96 25.872 ;
     RECT  119.856 25.093 119.88 25.872 ;
     RECT  121.776 23.893 121.8 25.872 ;
     RECT  123.696 25.765 123.72 25.872 ;
     RECT  125.664 25.093 125.688 25.872 ;
     RECT  127.584 23.893 127.608 25.872 ;
     RECT  129.504 25.765 129.528 25.872 ;
     RECT  131.424 25.765 131.448 25.872 ;
     RECT  133.344 23.893 133.368 25.872 ;
     RECT  135.264 25.765 135.288 25.872 ;
     RECT  137.184 23.893 137.208 25.872 ;
     RECT  139.104 25.093 139.128 25.872 ;
     RECT  141.024 23.701 141.048 25.872 ;
     RECT  142.992 23.783 143.016 25.872 ;
     RECT  144.912 25.093 144.936 25.872 ;
     RECT  146.832 25.139 146.856 25.872 ;
     RECT  148.752 23.783 148.776 25.872 ;
  END
END qkd_static_kv_landing_row
END LIBRARY
